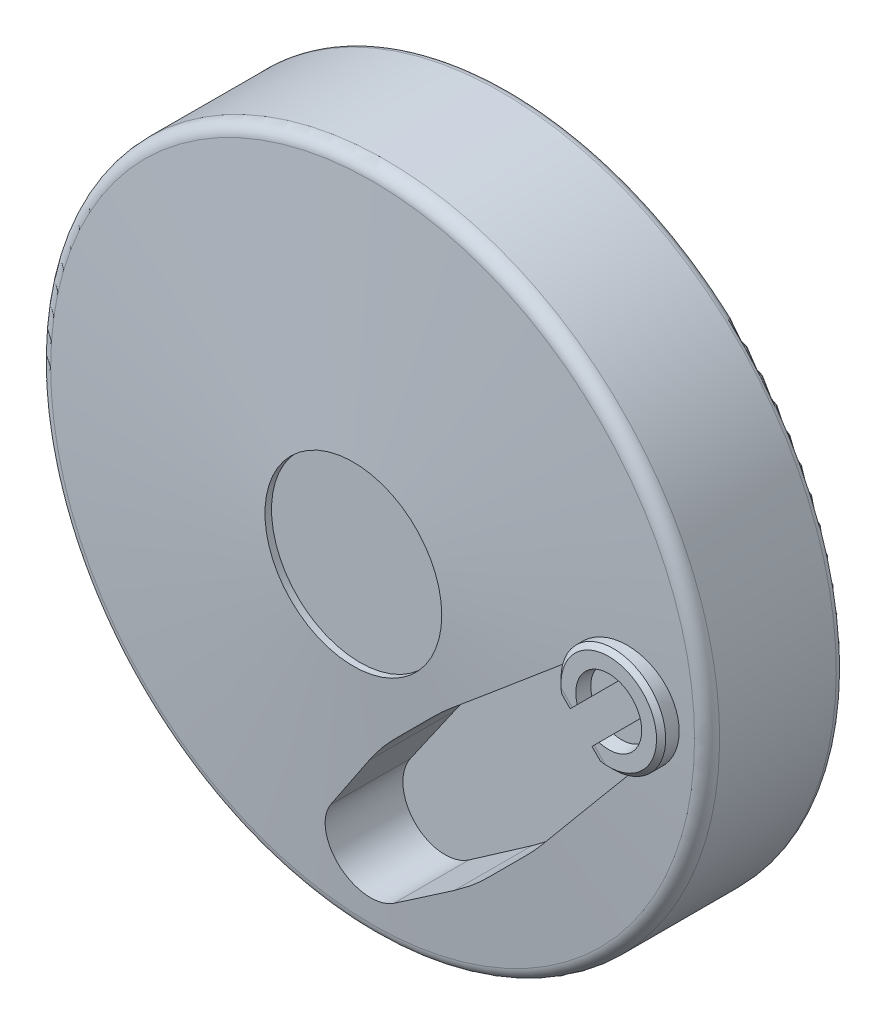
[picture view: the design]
ISO-10303-21;
HEADER;
FILE_DESCRIPTION(('STEP AP214'),'2;1');
FILE_NAME('part.step','',(''),(''),'','','');
FILE_SCHEMA(('AUTOMOTIVE_DESIGN { 1 0 10303 214 1 1 1 1 }'));
ENDSEC;
DATA;
#1=APPLICATION_CONTEXT('core data for automotive mechanical design processes');
#2=APPLICATION_PROTOCOL_DEFINITION('international standard','automotive_design',2000,#1);
#3=PRODUCT_CONTEXT('',#1,'mechanical');
#4=PRODUCT('Part','Part','',(#3));
#5=PRODUCT_RELATED_PRODUCT_CATEGORY('part','',(#4));
#6=PRODUCT_DEFINITION_FORMATION('','',#4);
#7=PRODUCT_DEFINITION_CONTEXT('part definition',#1,'design');
#8=PRODUCT_DEFINITION('design','',#6,#7);
#9=PRODUCT_DEFINITION_SHAPE('','',#8);
#10=(LENGTH_UNIT() NAMED_UNIT(*) SI_UNIT(.MILLI.,.METRE.));
#11=(NAMED_UNIT(*) PLANE_ANGLE_UNIT() SI_UNIT($,.RADIAN.));
#12=(NAMED_UNIT(*) SI_UNIT($,.STERADIAN.) SOLID_ANGLE_UNIT());
#13=UNCERTAINTY_MEASURE_WITH_UNIT(LENGTH_MEASURE(1.E-05),#10,'distance_accuracy_value','');
#14=(GEOMETRIC_REPRESENTATION_CONTEXT(3) GLOBAL_UNCERTAINTY_ASSIGNED_CONTEXT((#13)) GLOBAL_UNIT_ASSIGNED_CONTEXT((#10,
#11,#12)) REPRESENTATION_CONTEXT('',''));
#15=CARTESIAN_POINT('',(0.,0.,0.));
#16=DIRECTION('',(0.,0.,1.));
#17=DIRECTION('',(1.,0.,0.));
#18=AXIS2_PLACEMENT_3D('',#15,#16,#17);
#19=CARTESIAN_POINT('',(39.,0.,20.0000000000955));
#20=DIRECTION('',(0.,0.,-1.));
#21=DIRECTION('',(-0.707106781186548,0.707106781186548,0.));
#22=AXIS2_PLACEMENT_3D('',#19,#20,#21);
#23=CONICAL_SURFACE('',#22,1.9999999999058,0.785398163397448);
#24=CARTESIAN_POINT('',(39.,0.,20.0000000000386));
#25=DIRECTION('',(0.,0.,1.));
#26=DIRECTION('',(-0.707106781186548,0.707106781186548,0.));
#27=AXIS2_PLACEMENT_3D('',#24,#25,#26);
#28=CIRCLE('',#27,1.99999999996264);
#29=CARTESIAN_POINT('',(37.5857864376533,1.41421356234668,20.0000000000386));
#30=VERTEX_POINT('',#29);
#31=EDGE_CURVE('E739',#30,#30,#28,.F.);
#32=ORIENTED_EDGE('',*,*,#31,.T.);
#33=EDGE_LOOP('',(#32));
#34=FACE_BOUND('',#33,.T.);
#35=CARTESIAN_POINT('',(39.,0.,20.3790000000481));
#36=DIRECTION('',(0.,0.,1.));
#37=DIRECTION('',(-0.707106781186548,-0.707106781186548,0.));
#38=AXIS2_PLACEMENT_3D('',#35,#36,#37);
#39=CIRCLE('',#38,1.62099999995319);
#40=CARTESIAN_POINT('',(37.8537799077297,-1.14622009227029,20.3790000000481));
#41=VERTEX_POINT('',#40);
#42=EDGE_CURVE('E689',#41,#41,#39,.T.);
#43=ORIENTED_EDGE('',*,*,#42,.T.);
#44=EDGE_LOOP('',(#43));
#45=FACE_BOUND('',#44,.T.);
#46=ADVANCED_FACE('F16',(#34,#45),#23,.F.);
#47=CARTESIAN_POINT('',(39.,0.,22.));
#48=DIRECTION('',(0.,0.,-1.));
#49=DIRECTION('',(-0.707106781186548,0.707106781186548,0.));
#50=AXIS2_PLACEMENT_3D('',#47,#48,#49);
#51=CYLINDRICAL_SURFACE('',#50,1.621);
#52=CARTESIAN_POINT('',(39.,0.,23.6209999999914));
#53=DIRECTION('',(0.,0.,-1.));
#54=DIRECTION('',(-0.707106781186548,-0.707106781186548,0.));
#55=AXIS2_PLACEMENT_3D('',#52,#53,#54);
#56=CIRCLE('',#55,1.62100000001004);
#57=CARTESIAN_POINT('',(37.8537799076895,-1.14622009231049,23.6209999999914));
#58=VERTEX_POINT('',#57);
#59=EDGE_CURVE('E692',#58,#58,#56,.T.);
#60=ORIENTED_EDGE('',*,*,#59,.F.);
#61=EDGE_LOOP('',(#60));
#62=FACE_BOUND('',#61,.T.);
#63=ORIENTED_EDGE('',*,*,#42,.F.);
#64=EDGE_LOOP('',(#63));
#65=FACE_BOUND('',#64,.T.);
#66=ADVANCED_FACE('F414',(#62,#65),#51,.F.);
#67=CARTESIAN_POINT('',(39.,0.,20.7));
#68=DIRECTION('',(0.,0.,1.));
#69=DIRECTION('',(0.707106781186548,-0.707106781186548,0.));
#70=AXIS2_PLACEMENT_3D('',#67,#68,#69);
#71=CONICAL_SURFACE('',#70,8.,0.78539816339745);
#72=CARTESIAN_POINT('',(46.296517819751,0.225450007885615,20.));
#73=CARTESIAN_POINT('',(46.3518118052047,0.280743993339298,20.0569771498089));
#74=CARTESIAN_POINT('',(46.4069082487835,0.335840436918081,20.1143364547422));
#75=CARTESIAN_POINT('',(46.5167301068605,0.445662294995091,20.2297502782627));
#76=CARTESIAN_POINT('',(46.5714555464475,0.500387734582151,20.2878047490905));
#77=CARTESIAN_POINT('',(46.680566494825,0.609498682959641,20.4045470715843));
#78=CARTESIAN_POINT('',(46.734952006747,0.663884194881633,20.4632349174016));
#79=CARTESIAN_POINT('',(46.8434116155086,0.77234380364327,20.5811942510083));
#80=CARTESIAN_POINT('',(46.8974856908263,0.826417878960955,20.6404657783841));
#81=CARTESIAN_POINT('',(46.9514143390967,0.880346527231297,20.7));
#82=B_SPLINE_CURVE_WITH_KNOTS('',3,(#72,#73,#74,#75,#76,#77,#78,#79,#80,#81),.UNSPECIFIED.,.F.,
.F.,(4,2,2,2,4),(0.,0.290258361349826,0.580496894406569,0.870732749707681,1.16098842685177),.UNSPECIFIED.);
#83=CARTESIAN_POINT('',(46.296517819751,0.225450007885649,20.));
#84=VERTEX_POINT('',#83);
#85=CARTESIAN_POINT('',(46.9514143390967,0.880346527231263,20.7));
#86=VERTEX_POINT('',#85);
#87=EDGE_CURVE('E797',#84,#86,#82,.T.);
#88=ORIENTED_EDGE('',*,*,#87,.F.);
#89=CARTESIAN_POINT('',(39.,0.,20.));
#90=DIRECTION('',(0.,0.,-1.));
#91=DIRECTION('',(0.707106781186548,-0.707106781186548,0.));
#92=AXIS2_PLACEMENT_3D('',#89,#90,#91);
#93=CIRCLE('',#92,7.3);
#94=CARTESIAN_POINT('',(39.2254500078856,7.29651781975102,20.));
#95=VERTEX_POINT('',#94);
#96=EDGE_CURVE('E869',#95,#84,#93,.T.);
#97=ORIENTED_EDGE('',*,*,#96,.F.);
#98=CARTESIAN_POINT('',(39.8803465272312,7.95141433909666,20.7));
#99=CARTESIAN_POINT('',(39.8264178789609,7.89748569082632,20.6404657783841));
#100=CARTESIAN_POINT('',(39.7723438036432,7.84341161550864,20.5811942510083));
#101=CARTESIAN_POINT('',(39.6638841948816,7.73495200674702,20.4632349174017));
#102=CARTESIAN_POINT('',(39.6094986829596,7.68056649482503,20.4045470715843));
#103=CARTESIAN_POINT('',(39.5003877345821,7.57145554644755,20.2878047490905));
#104=CARTESIAN_POINT('',(39.4456622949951,7.51673010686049,20.2297502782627));
#105=CARTESIAN_POINT('',(39.3358404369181,7.40690824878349,20.1143364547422));
#106=CARTESIAN_POINT('',(39.2807439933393,7.35181180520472,20.056977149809));
#107=CARTESIAN_POINT('',(39.2254500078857,7.29651781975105,20.));
#108=B_SPLINE_CURVE_WITH_KNOTS('',3,(#98,#99,#100,#101,#102,#103,#104,#105,#106,#107),
.UNSPECIFIED.,.F.,.F.,(4,2,2,2,4),(0.,0.290255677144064,0.580491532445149,0.870730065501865,
1.16098842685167),.UNSPECIFIED.);
#109=CARTESIAN_POINT('',(39.8803465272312,7.95141433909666,20.7));
#110=VERTEX_POINT('',#109);
#111=EDGE_CURVE('E598',#110,#95,#108,.T.);
#112=ORIENTED_EDGE('',*,*,#111,.F.);
#113=CARTESIAN_POINT('',(39.,0.,20.7));
#114=DIRECTION('',(0.,0.,1.));
#115=DIRECTION('',(-0.707106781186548,0.707106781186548,0.));
#116=AXIS2_PLACEMENT_3D('',#113,#114,#115);
#117=CIRCLE('',#116,8.);
#118=EDGE_CURVE('E787',#110,#86,#117,.F.);
#119=ORIENTED_EDGE('',*,*,#118,.T.);
#120=EDGE_LOOP('',(#88,#97,#112,#119));
#121=FACE_BOUND('',#120,.T.);
#122=ADVANCED_FACE('F421',(#121),#71,.T.);
#123=CARTESIAN_POINT('',(39.,0.,27.));
#124=DIRECTION('',(0.,0.,-1.));
#125=DIRECTION('',(-0.707106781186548,0.707106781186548,0.));
#126=AXIS2_PLACEMENT_3D('',#123,#124,#125);
#127=CYLINDRICAL_SURFACE('',#126,8.);
#128=CARTESIAN_POINT('',(39.,0.,21.7));
#129=DIRECTION('',(0.,0.,1.));
#130=DIRECTION('',(-0.707106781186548,0.707106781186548,0.));
#131=AXIS2_PLACEMENT_3D('',#128,#129,#130);
#132=CIRCLE('',#131,8.);
#133=CARTESIAN_POINT('',(31.0485856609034,-0.880346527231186,21.7));
#134=VERTEX_POINT('',#133);
#135=CARTESIAN_POINT('',(31.2290449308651,1.90059393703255,21.7));
#136=VERTEX_POINT('',#135);
#137=EDGE_CURVE('E1031',#134,#136,#132,.F.);
#138=ORIENTED_EDGE('',*,*,#137,.F.);
#139=DIRECTION('',(0.,0.,1.));
#140=VECTOR('',#139,1.);
#141=CARTESIAN_POINT('',(31.0485856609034,-0.880346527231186,21.7));
#142=LINE('',#141,#140);
#143=CARTESIAN_POINT('',(31.0485856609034,-0.880346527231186,20.7));
#144=VERTEX_POINT('',#143);
#145=EDGE_CURVE('E686',#144,#134,#142,.T.);
#146=ORIENTED_EDGE('',*,*,#145,.F.);
#147=CARTESIAN_POINT('',(39.,0.,20.7));
#148=DIRECTION('',(0.,0.,1.));
#149=DIRECTION('',(-0.707106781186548,0.707106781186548,0.));
#150=AXIS2_PLACEMENT_3D('',#147,#148,#149);
#151=CIRCLE('',#150,8.);
#152=CARTESIAN_POINT('',(31.3116397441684,-2.21113468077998,20.7));
#153=VERTEX_POINT('',#152);
#154=EDGE_CURVE('E732',#153,#144,#151,.F.);
#155=ORIENTED_EDGE('',*,*,#154,.F.);
#156=DIRECTION('',(0.,0.,1.));
#157=VECTOR('',#156,1.);
#158=CARTESIAN_POINT('',(31.3116397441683,-2.21113468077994,32.5));
#159=LINE('',#158,#157);
#160=CARTESIAN_POINT('',(31.3116397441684,-2.21113468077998,32.5));
#161=VERTEX_POINT('',#160);
#162=EDGE_CURVE('E796',#161,#153,#159,.F.);
#163=ORIENTED_EDGE('',*,*,#162,.F.);
#164=CARTESIAN_POINT('',(31.3116397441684,-2.21113468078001,32.5));
#165=CARTESIAN_POINT('',(31.3116427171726,-2.21114242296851,32.5227173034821));
#166=CARTESIAN_POINT('',(31.3113448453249,-2.21010946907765,32.5454212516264));
#167=CARTESIAN_POINT('',(31.3101749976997,-2.20603682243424,32.5906042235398));
#168=CARTESIAN_POINT('',(31.3093037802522,-2.20299978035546,32.6130835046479));
#169=CARTESIAN_POINT('',(31.3059063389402,-2.1911165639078,32.6792728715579));
#170=CARTESIAN_POINT('',(31.3025944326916,-2.17949295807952,32.7224622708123));
#171=CARTESIAN_POINT('',(31.2931287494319,-2.14581287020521,32.8180990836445));
#172=CARTESIAN_POINT('',(31.2864398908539,-2.12175040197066,32.8697675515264));
#173=CARTESIAN_POINT('',(31.2712617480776,-2.06578125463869,32.9689084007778));
#174=CARTESIAN_POINT('',(31.2627552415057,-2.03379903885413,33.0163340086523));
#175=CARTESIAN_POINT('',(31.2450338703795,-1.96512617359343,33.1055959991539));
#176=CARTESIAN_POINT('',(31.2358401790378,-1.92856287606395,33.1475370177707));
#177=CARTESIAN_POINT('',(31.2172452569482,-1.8521046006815,33.2268366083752));
#178=CARTESIAN_POINT('',(31.2078502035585,-1.81227675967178,33.2642609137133));
#179=CARTESIAN_POINT('',(31.1985194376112,-1.77112987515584,33.3));
#180=B_SPLINE_CURVE_WITH_KNOTS('',3,(#164,#165,#166,#167,#168,#169,#170,#171,#172,#173,#174,
#175,#176,#177,#178,#179),.UNSPECIFIED.,.F.,.F.,(4,2,2,2,2,2,2,4),(0.,0.0681022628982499,
0.13611463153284,0.269988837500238,0.441214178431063,0.614140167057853,0.783029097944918,
0.949049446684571),.UNSPECIFIED.);
#181=CARTESIAN_POINT('',(31.1985194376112,-1.77112987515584,33.3));
#182=VERTEX_POINT('',#181);
#183=EDGE_CURVE('E519',#161,#182,#180,.T.);
#184=ORIENTED_EDGE('',*,*,#183,.T.);
#185=CARTESIAN_POINT('',(39.,0.,33.3));
#186=DIRECTION('',(0.,0.,1.));
#187=DIRECTION('',(-0.707106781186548,0.707106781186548,0.));
#188=AXIS2_PLACEMENT_3D('',#185,#186,#187);
#189=CIRCLE('',#188,8.);
#190=CARTESIAN_POINT('',(37.2288701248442,-7.80148056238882,33.3));
#191=VERTEX_POINT('',#190);
#192=EDGE_CURVE('E809',#191,#182,#189,.T.);
#193=ORIENTED_EDGE('',*,*,#192,.F.);
#194=CARTESIAN_POINT('',(37.2288701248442,-7.80148056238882,33.3));
#195=CARTESIAN_POINT('',(37.2037214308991,-7.79577165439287,33.2781899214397));
#196=CARTESIAN_POINT('',(37.1791163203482,-7.7900570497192,33.2557657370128));
#197=CARTESIAN_POINT('',(37.1311438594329,-7.77868792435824,33.2095314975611));
#198=CARTESIAN_POINT('',(37.1077788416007,-7.77303353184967,33.1857189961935));
#199=CARTESIAN_POINT('',(37.0390422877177,-7.75608687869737,33.1111472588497));
#200=CARTESIAN_POINT('',(36.996006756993,-7.74503578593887,33.0580775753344));
#201=CARTESIAN_POINT('',(36.9282187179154,-7.72713744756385,32.9586689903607));
#202=CARTESIAN_POINT('',(36.9015504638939,-7.71991465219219,32.9137163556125));
#203=CARTESIAN_POINT('',(36.8556321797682,-7.70728538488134,32.8203594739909));
#204=CARTESIAN_POINT('',(36.8363113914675,-7.70186165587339,32.7719937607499));
#205=CARTESIAN_POINT('',(36.8110494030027,-7.69471405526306,32.6864246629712));
#206=CARTESIAN_POINT('',(36.8028688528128,-7.69237742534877,32.6499379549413));
#207=CARTESIAN_POINT('',(36.7917114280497,-7.68917895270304,32.5756695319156));
#208=CARTESIAN_POINT('',(36.7887991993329,-7.68833543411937,32.5378774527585));
#209=CARTESIAN_POINT('',(36.7888653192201,-7.68836025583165,32.5));
#210=B_SPLINE_CURVE_WITH_KNOTS('',3,(#194,#195,#196,#197,#198,#199,#200,#201,#202,#203,#204,
#205,#206,#207,#208,#209),.UNSPECIFIED.,.F.,.F.,(4,2,2,2,2,2,2,4),(0.,0.101292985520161,
0.202770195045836,0.409597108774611,0.56739941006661,0.723641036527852,0.83564649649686,
0.949017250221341),.UNSPECIFIED.);
#211=CARTESIAN_POINT('',(36.7888653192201,-7.68836025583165,32.5));
#212=VERTEX_POINT('',#211);
#213=EDGE_CURVE('E536',#191,#212,#210,.T.);
#214=ORIENTED_EDGE('',*,*,#213,.T.);
#215=DIRECTION('',(0.,0.,-1.));
#216=VECTOR('',#215,1.);
#217=CARTESIAN_POINT('',(36.7888653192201,-7.68836025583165,27.));
#218=LINE('',#217,#216);
#219=CARTESIAN_POINT('',(36.7888653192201,-7.68836025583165,20.7));
#220=VERTEX_POINT('',#219);
#221=EDGE_CURVE('E806',#220,#212,#218,.F.);
#222=ORIENTED_EDGE('',*,*,#221,.F.);
#223=CARTESIAN_POINT('',(39.,0.,20.7));
#224=DIRECTION('',(0.,0.,-1.));
#225=DIRECTION('',(-0.707106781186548,-0.707106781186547,0.));
#226=AXIS2_PLACEMENT_3D('',#223,#224,#225);
#227=CIRCLE('',#226,8.);
#228=CARTESIAN_POINT('',(38.1196534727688,-7.95141433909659,20.7));
#229=VERTEX_POINT('',#228);
#230=EDGE_CURVE('E743',#220,#229,#227,.F.);
#231=ORIENTED_EDGE('',*,*,#230,.T.);
#232=DIRECTION('',(0.,0.,1.));
#233=VECTOR('',#232,1.);
#234=CARTESIAN_POINT('',(38.1196534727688,-7.95141433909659,20.));
#235=LINE('',#234,#233);
#236=CARTESIAN_POINT('',(38.1196534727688,-7.95141433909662,21.7));
#237=VERTEX_POINT('',#236);
#238=EDGE_CURVE('E725',#237,#229,#235,.F.);
#239=ORIENTED_EDGE('',*,*,#238,.F.);
#240=CARTESIAN_POINT('',(39.,0.,21.7));
#241=DIRECTION('',(0.,0.,1.));
#242=DIRECTION('',(-0.707106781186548,0.707106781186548,0.));
#243=AXIS2_PLACEMENT_3D('',#240,#241,#242);
#244=CIRCLE('',#243,8.);
#245=CARTESIAN_POINT('',(40.9005939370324,-7.77095506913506,21.7));
#246=VERTEX_POINT('',#245);
#247=EDGE_CURVE('E792',#246,#237,#244,.F.);
#248=ORIENTED_EDGE('',*,*,#247,.F.);
#249=DIRECTION('',(0.,0.,-1.));
#250=VECTOR('',#249,1.);
#251=CARTESIAN_POINT('',(40.9005939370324,-7.77095506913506,27.));
#252=LINE('',#251,#250);
#253=CARTESIAN_POINT('',(40.9005939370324,-7.77095506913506,31.6812185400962));
#254=VERTEX_POINT('',#253);
#255=EDGE_CURVE('E485',#254,#246,#252,.T.);
#256=ORIENTED_EDGE('',*,*,#255,.F.);
#257=CARTESIAN_POINT('',(31.7898495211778,-3.46608281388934,32.4769445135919));
#258=CARTESIAN_POINT('',(31.6928486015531,-3.26435756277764,32.4866964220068));
#259=CARTESIAN_POINT('',(31.6043429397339,-3.05851151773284,32.4956463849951));
#260=CARTESIAN_POINT('',(31.4448682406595,-2.64007722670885,32.5118412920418));
#261=CARTESIAN_POINT('',(31.3738986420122,-2.42748919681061,32.5190862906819));
#262=CARTESIAN_POINT('',(31.2500780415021,-1.99720366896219,32.5317664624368));
#263=CARTESIAN_POINT('',(31.1972147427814,-1.77950974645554,32.5372028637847));
#264=CARTESIAN_POINT('',(31.109919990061,-1.34042289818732,32.5461989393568));
#265=CARTESIAN_POINT('',(31.0754882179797,-1.11903003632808,32.549758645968));
#266=CARTESIAN_POINT('',(31.0252958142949,-0.673993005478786,32.5549527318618));
#267=CARTESIAN_POINT('',(31.0095453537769,-0.450347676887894,32.5565860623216));
#268=CARTESIAN_POINT('',(30.9968648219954,-0.00251492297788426,32.5579007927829));
#269=CARTESIAN_POINT('',(30.9999350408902,0.221672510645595,32.5575821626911));
#270=CARTESIAN_POINT('',(31.0248711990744,0.668936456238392,32.5549977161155));
#271=CARTESIAN_POINT('',(31.0467328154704,0.892013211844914,32.5527323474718));
#272=CARTESIAN_POINT('',(31.1090851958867,1.33551840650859,32.5462870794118));
#273=CARTESIAN_POINT('',(31.1495758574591,1.55594686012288,32.5421071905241));
#274=CARTESIAN_POINT('',(31.2488312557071,1.9923343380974,32.5318971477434));
#275=CARTESIAN_POINT('',(31.3075745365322,2.20829829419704,32.5258691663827));
#276=CARTESIAN_POINT('',(31.4429458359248,2.634569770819,32.5120408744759));
#277=CARTESIAN_POINT('',(31.5195800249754,2.84487531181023,32.5042399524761));
#278=CARTESIAN_POINT('',(31.690165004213,3.25826796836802,32.4869700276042));
#279=CARTESIAN_POINT('',(31.7841156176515,3.46135515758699,32.4775010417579));
#280=CARTESIAN_POINT('',(31.988657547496,3.85889187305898,32.4570152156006));
#281=CARTESIAN_POINT('',(32.0992491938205,4.05334122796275,32.445998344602));
#282=CARTESIAN_POINT('',(32.3365809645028,4.43272363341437,32.4225211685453));
#283=CARTESIAN_POINT('',(32.4633616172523,4.61763110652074,32.4100572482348));
#284=CARTESIAN_POINT('',(32.7319427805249,4.9761048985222,32.3838539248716));
#285=CARTESIAN_POINT('',(32.8737436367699,5.14967095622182,32.3701144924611));
#286=CARTESIAN_POINT('',(33.1713144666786,5.48420718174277,32.341516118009));
#287=CARTESIAN_POINT('',(33.3270810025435,5.64518043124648,32.3266574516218));
#288=CARTESIAN_POINT('',(33.6515638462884,5.95351478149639,32.2959680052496));
#289=CARTESIAN_POINT('',(33.8202846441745,6.10087112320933,32.2801368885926));
#290=CARTESIAN_POINT('',(34.1701796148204,6.38148422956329,32.2475947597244));
#291=CARTESIAN_POINT('',(34.3514037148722,6.51467834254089,32.230880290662));
#292=CARTESIAN_POINT('',(34.7244430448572,6.76536265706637,32.1967847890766));
#293=CARTESIAN_POINT('',(34.9162621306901,6.88284708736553,32.1794035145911));
#294=CARTESIAN_POINT('',(35.3090563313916,7.10122696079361,32.1441358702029));
#295=CARTESIAN_POINT('',(35.5100306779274,7.20212379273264,32.1262495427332));
#296=CARTESIAN_POINT('',(35.9197341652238,7.38663934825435,32.0901197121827));
#297=CARTESIAN_POINT('',(36.1284635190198,7.47025759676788,32.0718761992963));
#298=CARTESIAN_POINT('',(36.557680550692,7.6215603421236,32.034701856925));
#299=CARTESIAN_POINT('',(36.7783326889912,7.68877738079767,32.0157654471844));
#300=CARTESIAN_POINT('',(37.2246179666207,7.80391756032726,31.977816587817));
#301=CARTESIAN_POINT('',(37.4502513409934,7.85183978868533,31.958804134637));
#302=CARTESIAN_POINT('',(37.9047723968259,7.92802398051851,31.9208488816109));
#303=CARTESIAN_POINT('',(38.1336594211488,7.95628985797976,31.9019060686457));
#304=CARTESIAN_POINT('',(38.5931160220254,7.99297028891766,31.8642129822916));
#305=CARTESIAN_POINT('',(38.8236861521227,8.00137798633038,31.8454627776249));
#306=CARTESIAN_POINT('',(39.2794787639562,7.99829026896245,31.8087096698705));
#307=CARTESIAN_POINT('',(39.5047038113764,7.98724238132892,31.7906994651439));
#308=CARTESIAN_POINT('',(39.9534539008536,7.94617458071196,31.7550990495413));
#309=CARTESIAN_POINT('',(40.1769789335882,7.91615456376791,31.7375088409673));
#310=CARTESIAN_POINT('',(40.6207167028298,7.83734978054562,31.7028530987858));
#311=CARTESIAN_POINT('',(40.8409297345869,7.78856669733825,31.6857875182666));
#312=CARTESIAN_POINT('',(41.2765020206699,7.67257025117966,31.6522747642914));
#313=CARTESIAN_POINT('',(41.4918611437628,7.60535639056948,31.6358276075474));
#314=CARTESIAN_POINT('',(41.9161678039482,7.45297097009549,31.6036423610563));
#315=CARTESIAN_POINT('',(42.1251157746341,7.36780062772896,31.5879042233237));
#316=CARTESIAN_POINT('',(42.5351931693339,7.1800612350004,31.5572128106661));
#317=CARTESIAN_POINT('',(42.7363198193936,7.07748607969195,31.542259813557));
#318=CARTESIAN_POINT('',(43.1291568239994,6.85572163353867,31.5132263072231));
#319=CARTESIAN_POINT('',(43.3208708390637,6.73653887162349,31.499145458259));
#320=CARTESIAN_POINT('',(43.6936741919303,6.48231046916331,31.4719132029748));
#321=CARTESIAN_POINT('',(43.8747586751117,6.34725766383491,31.4587622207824));
#322=CARTESIAN_POINT('',(44.224597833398,6.06253678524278,31.4334821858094));
#323=CARTESIAN_POINT('',(44.3933734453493,5.91289459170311,31.4213513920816));
#324=CARTESIAN_POINT('',(44.7176529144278,5.59992840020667,31.3981484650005));
#325=CARTESIAN_POINT('',(44.8731627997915,5.43661068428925,31.3870758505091));
#326=CARTESIAN_POINT('',(45.1699342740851,5.09732556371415,31.3660298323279));
#327=CARTESIAN_POINT('',(45.3111902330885,4.92135320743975,31.3560568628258));
#328=CARTESIAN_POINT('',(45.5783155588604,4.55813203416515,31.337263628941));
#329=CARTESIAN_POINT('',(45.7041903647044,4.37088723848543,31.3284429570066));
#330=CARTESIAN_POINT('',(45.9394195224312,3.98685824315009,31.3120091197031));
#331=CARTESIAN_POINT('',(46.048812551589,3.79009785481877,31.3043931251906));
#332=CARTESIAN_POINT('',(46.2506449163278,3.38802976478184,31.2903768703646));
#333=CARTESIAN_POINT('',(46.3430846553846,3.18272226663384,31.2839765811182));
#334=CARTESIAN_POINT('',(46.5103463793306,2.76501566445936,31.2724192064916));
#335=CARTESIAN_POINT('',(46.585168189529,2.55261649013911,31.2672621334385));
#336=CARTESIAN_POINT('',(46.7166504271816,2.12224682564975,31.2582135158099));
#337=CARTESIAN_POINT('',(46.7733111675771,1.90427643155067,31.2543219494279));
#338=CARTESIAN_POINT('',(46.8679769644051,1.46471536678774,31.2478267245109));
#339=CARTESIAN_POINT('',(46.9060155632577,1.24313195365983,31.2452207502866));
#340=CARTESIAN_POINT('',(46.9633053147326,0.797616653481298,31.2412979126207));
#341=CARTESIAN_POINT('',(46.9825630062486,0.573685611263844,31.2399806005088));
#342=CARTESIAN_POINT('',(47.0021766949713,0.124953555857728,31.2386389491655));
#343=CARTESIAN_POINT('',(47.0025293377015,-0.0998476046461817,31.2386148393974));
#344=CARTESIAN_POINT('',(46.9843221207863,-0.5486741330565,31.2398602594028));
#345=CARTESIAN_POINT('',(46.9657626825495,-0.77269951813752,31.2411297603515));
#346=CARTESIAN_POINT('',(46.9098901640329,-1.21819142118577,31.244955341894));
#347=CARTESIAN_POINT('',(46.8725932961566,-1.43965998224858,31.2475103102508));
#348=CARTESIAN_POINT('',(46.7795236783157,-1.87865799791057,31.2538954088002));
#349=CARTESIAN_POINT('',(46.7237512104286,-2.09618751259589,31.2577255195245));
#350=CARTESIAN_POINT('',(46.5941198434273,-2.52580625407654,31.266645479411));
#351=CARTESIAN_POINT('',(46.5202576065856,-2.7378944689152,31.2717355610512));
#352=CARTESIAN_POINT('',(46.3550120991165,-3.1550123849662,31.2831513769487));
#353=CARTESIAN_POINT('',(46.2636348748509,-3.36004449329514,31.2894766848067));
#354=CARTESIAN_POINT('',(46.0639359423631,-3.76180319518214,31.3033412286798));
#355=CARTESIAN_POINT('',(45.9556035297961,-3.95852444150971,31.310881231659));
#356=CARTESIAN_POINT('',(45.7228167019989,-4.34212733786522,31.327139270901));
#357=CARTESIAN_POINT('',(45.5983626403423,-4.5290092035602,31.3358572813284));
#358=CARTESIAN_POINT('',(45.3342225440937,-4.89161924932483,31.3544330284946));
#359=CARTESIAN_POINT('',(45.1945364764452,-5.06734740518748,31.3642907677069));
#360=CARTESIAN_POINT('',(44.9009341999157,-5.40640975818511,31.3851016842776));
#361=CARTESIAN_POINT('',(44.7470181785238,-5.56974411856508,31.3960548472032));
#362=CARTESIAN_POINT('',(44.4257618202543,-5.88315888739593,31.4190277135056));
#363=CARTESIAN_POINT('',(44.2583976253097,-6.03321470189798,31.4310493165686));
#364=CARTESIAN_POINT('',(43.9117451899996,-6.31863516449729,31.4560817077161));
#365=CARTESIAN_POINT('',(43.7324610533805,-6.45400482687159,31.469092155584));
#366=CARTESIAN_POINT('',(43.3631491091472,-6.70919675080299,31.4960473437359));
#367=CARTESIAN_POINT('',(43.1731186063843,-6.82901508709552,31.5099923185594));
#368=CARTESIAN_POINT('',(42.7837117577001,-7.05222587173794,31.5387452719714));
#369=CARTESIAN_POINT('',(42.5843356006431,-7.15561865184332,31.5535532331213));
#370=CARTESIAN_POINT('',(42.1771387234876,-7.34550079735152,31.5839963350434));
#371=CARTESIAN_POINT('',(41.9692980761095,-7.43194711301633,31.5996334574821));
#372=CARTESIAN_POINT('',(41.5471254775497,-7.58700994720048,31.6316192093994));
#373=CARTESIAN_POINT('',(41.3327936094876,-7.6556266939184,31.6479678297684));
#374=CARTESIAN_POINT('',(40.8991488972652,-7.77456003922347,31.6812896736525));
#375=CARTESIAN_POINT('',(40.6798358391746,-7.82487585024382,31.6982629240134));
#376=CARTESIAN_POINT('',(40.237868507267,-7.90684374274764,31.732732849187));
#377=CARTESIAN_POINT('',(40.0152154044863,-7.93850221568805,31.7502293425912));
#378=CARTESIAN_POINT('',(39.5674690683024,-7.98302755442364,31.785697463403));
#379=CARTESIAN_POINT('',(39.3423708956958,-7.99584384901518,31.8036702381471));
#380=CARTESIAN_POINT('',(38.8919205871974,-8.00244066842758,31.8399365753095));
#381=CARTESIAN_POINT('',(38.6665684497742,-7.99622107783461,31.858230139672));
#382=CARTESIAN_POINT('',(38.2171627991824,-7.96479217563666,31.8950253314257));
#383=CARTESIAN_POINT('',(37.9931095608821,-7.93957898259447,31.9135270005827));
#384=CARTESIAN_POINT('',(37.5479391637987,-7.87034064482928,31.950610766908));
#385=CARTESIAN_POINT('',(37.3268219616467,-7.82631577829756,31.969192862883));
#386=CARTESIAN_POINT('',(36.8888192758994,-7.71970071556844,32.006329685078));
#387=CARTESIAN_POINT('',(36.6719392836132,-7.65708793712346,32.0248843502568));
#388=CARTESIAN_POINT('',(36.244226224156,-7.51375999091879,32.0618055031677));
#389=CARTESIAN_POINT('',(36.0333932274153,-7.43304461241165,32.0801719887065));
#390=CARTESIAN_POINT('',(35.6191337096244,-7.25401042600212,32.1165849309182));
#391=CARTESIAN_POINT('',(35.4157124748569,-7.15567933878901,32.1346311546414));
#392=CARTESIAN_POINT('',(35.0178590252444,-6.94216304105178,32.1702394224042));
#393=CARTESIAN_POINT('',(34.823427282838,-6.8269769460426,32.187801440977));
#394=CARTESIAN_POINT('',(34.6342146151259,-6.70372418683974,32.2050449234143));
#395=B_SPLINE_CURVE_WITH_KNOTS('',3,(#257,#258,#259,#260,#261,#262,#263,#264,#265,#266,#267,
#268,#269,#270,#271,#272,#273,#274,#275,#276,#277,#278,#279,#280,#281,#282,#283,#284,#285,#286,
#287,#288,#289,#290,#291,#292,#293,#294,#295,#296,#297,#298,#299,#300,#301,#302,#303,#304,#305,
#306,#307,#308,#309,#310,#311,#312,#313,#314,#315,#316,#317,#318,#319,#320,#321,#322,#323,#324,
#325,#326,#327,#328,#329,#330,#331,#332,#333,#334,#335,#336,#337,#338,#339,#340,#341,#342,#343,
#344,#345,#346,#347,#348,#349,#350,#351,#352,#353,#354,#355,#356,#357,#358,#359,#360,#361,#362,
#363,#364,#365,#366,#367,#368,#369,#370,#371,#372,#373,#374,#375,#376,#377,#378,#379,#380,#381,
#382,#383,#384,#385,#386,#387,#388,#389,#390,#391,#392,#393,#394),.UNSPECIFIED.,.F.,.F.,(4,2,2,
2,2,2,2,2,2,2,2,2,2,2,2,2,2,2,2,2,2,2,2,2,2,2,2,2,2,2,2,2,2,2,2,2,2,2,2,2,2,2,2,2,2,2,2,2,2,2,2,
2,2,2,2,2,2,2,2,2,2,2,2,2,2,2,2,2,4),(0.,0.671941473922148,1.34386143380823,2.01532415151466,
2.68677528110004,3.3585918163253,4.03041870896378,4.70209109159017,5.37375978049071,
6.04464189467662,6.71575573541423,7.38686272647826,8.05798302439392,8.7308176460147,
9.40366775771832,10.0763526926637,10.7492718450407,11.4250538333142,12.1010834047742,
12.7770563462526,13.4530478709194,14.1465036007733,14.8399921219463,15.5333425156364,
16.2269322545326,16.9047754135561,17.5826222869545,18.2604083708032,18.9382127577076,
19.6159712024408,20.2939678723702,20.9716987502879,21.6497367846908,22.3265932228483,
23.0031404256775,23.6799538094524,24.3565271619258,25.0314872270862,25.7064312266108,
26.3813819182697,27.0563209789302,27.7300398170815,28.4035240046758,29.0771276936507,
29.7507163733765,30.4237232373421,31.0967198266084,31.7698406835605,32.4427295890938,
33.116045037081,33.7893457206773,34.4626478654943,35.1359411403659,35.8104564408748,
36.4847407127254,37.1591948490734,37.8336353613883,38.5097675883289,39.1858911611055,
39.8620438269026,40.5379647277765,41.2156964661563,41.8934323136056,42.5713066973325,
43.2491710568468,43.9278623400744,44.6065615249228,45.2857356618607,45.9649454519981),.UNSPECIFIED.);
#396=CARTESIAN_POINT('',(31.2290449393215,1.90059397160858,32.5339343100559));
#397=VERTEX_POINT('',#396);
#398=EDGE_CURVE('E488',#254,#397,#395,.F.);
#399=ORIENTED_EDGE('',*,*,#398,.T.);
#400=DIRECTION('',(0.,0.,-1.));
#401=VECTOR('',#400,1.);
#402=CARTESIAN_POINT('',(31.2290449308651,1.90059393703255,27.));
#403=LINE('',#402,#401);
#404=EDGE_CURVE('E483',#136,#397,#403,.F.);
#405=ORIENTED_EDGE('',*,*,#404,.F.);
#406=EDGE_LOOP('',(#138,#146,#155,#163,#184,#193,#214,#222,#231,#239,#248,#256,#399,#405));
#407=FACE_BOUND('',#406,.T.);
#408=ADVANCED_FACE('F499',(#407),#127,.T.);
#409=CARTESIAN_POINT('',(20.6152236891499,-4.24264068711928,21.7));
#410=DIRECTION('',(0.,0.,1.));
#411=DIRECTION('',(0.707106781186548,-0.707106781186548,0.));
#412=AXIS2_PLACEMENT_3D('',#409,#410,#411);
#413=PLANE('',#412);
#414=DIRECTION('',(-0.707106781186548,-0.707106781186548,0.));
#415=VECTOR('',#414,1.);
#416=CARTESIAN_POINT('',(24.1507575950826,-7.77817459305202,21.7));
#417=LINE('',#416,#415);
#418=CARTESIAN_POINT('',(39.8803465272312,7.95141433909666,21.7));
#419=VERTEX_POINT('',#418);
#420=EDGE_CURVE('E596',#419,#134,#417,.T.);
#421=ORIENTED_EDGE('',*,*,#420,.T.);
#422=ORIENTED_EDGE('',*,*,#137,.T.);
#423=EDGE_CURVE('E141',#136,#419,#132,.F.);
#424=ORIENTED_EDGE('',*,*,#423,.T.);
#425=EDGE_LOOP('',(#421,#422,#424));
#426=FACE_BOUND('',#425,.T.);
#427=ADVANCED_FACE('F503',(#426),#413,.F.);
#428=CARTESIAN_POINT('',(31.2218254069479,-14.8492424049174,21.7));
#429=DIRECTION('',(0.,0.,1.));
#430=DIRECTION('',(0.707106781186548,-0.707106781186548,0.));
#431=AXIS2_PLACEMENT_3D('',#428,#429,#430);
#432=PLANE('',#431);
#433=DIRECTION('',(-0.707106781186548,-0.707106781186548,0.));
#434=VECTOR('',#433,1.);
#435=CARTESIAN_POINT('',(31.2218254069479,-14.8492424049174,21.7));
#436=LINE('',#435,#434);
#437=CARTESIAN_POINT('',(46.9514143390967,0.880346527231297,21.7));
#438=VERTEX_POINT('',#437);
#439=EDGE_CURVE('E793',#237,#438,#436,.F.);
#440=ORIENTED_EDGE('',*,*,#439,.T.);
#441=EDGE_CURVE('E810',#438,#246,#244,.F.);
#442=ORIENTED_EDGE('',*,*,#441,.T.);
#443=ORIENTED_EDGE('',*,*,#247,.T.);
#444=EDGE_LOOP('',(#440,#442,#443));
#445=FACE_BOUND('',#444,.T.);
#446=ADVANCED_FACE('F859',(#445),#432,.F.);
#447=CARTESIAN_POINT('',(31.2218254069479,-14.8492424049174,20.));
#448=DIRECTION('',(-0.707106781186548,0.707106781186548,0.));
#449=DIRECTION('',(0.707106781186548,0.707106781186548,0.));
#450=AXIS2_PLACEMENT_3D('',#447,#448,#449);
#451=PLANE('',#450);
#452=ORIENTED_EDGE('',*,*,#87,.T.);
#453=DIRECTION('',(0.,0.,1.));
#454=VECTOR('',#453,1.);
#455=CARTESIAN_POINT('',(46.9514143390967,0.880346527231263,20.));
#456=LINE('',#455,#454);
#457=EDGE_CURVE('E728',#86,#438,#456,.T.);
#458=ORIENTED_EDGE('',*,*,#457,.T.);
#459=ORIENTED_EDGE('',*,*,#439,.F.);
#460=ORIENTED_EDGE('',*,*,#238,.T.);
#461=CARTESIAN_POINT('',(38.1196534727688,-7.95141433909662,20.7));
#462=CARTESIAN_POINT('',(38.1735821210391,-7.89748569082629,20.6404657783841));
#463=CARTESIAN_POINT('',(38.2276561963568,-7.84341161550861,20.5811942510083));
#464=CARTESIAN_POINT('',(38.3361158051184,-7.73495200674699,20.4632349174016));
#465=CARTESIAN_POINT('',(38.3905013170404,-7.680566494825,20.4045470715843));
#466=CARTESIAN_POINT('',(38.4996122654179,-7.57145554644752,20.2878047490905));
#467=CARTESIAN_POINT('',(38.5543377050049,-7.51673010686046,20.2297502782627));
#468=CARTESIAN_POINT('',(38.6641595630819,-7.40690824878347,20.1143364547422));
#469=CARTESIAN_POINT('',(38.7192560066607,-7.3518118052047,20.0569771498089));
#470=CARTESIAN_POINT('',(38.7745499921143,-7.29651781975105,20.));
#471=B_SPLINE_CURVE_WITH_KNOTS('',3,(#461,#462,#463,#464,#465,#466,#467,#468,#469,#470),
.UNSPECIFIED.,.F.,.F.,(4,2,2,2,4),(0.,0.290255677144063,0.580491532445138,0.870730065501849,
1.16098842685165),.UNSPECIFIED.);
#472=CARTESIAN_POINT('',(38.7745499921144,-7.29651781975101,20.));
#473=VERTEX_POINT('',#472);
#474=EDGE_CURVE('E746',#229,#473,#471,.T.);
#475=ORIENTED_EDGE('',*,*,#474,.T.);
#476=DIRECTION('',(-0.707106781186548,-0.707106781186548,0.));
#477=VECTOR('',#476,1.);
#478=CARTESIAN_POINT('',(39.9545941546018,-6.11647365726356,20.));
#479=LINE('',#478,#477);
#480=EDGE_CURVE('E735',#473,#84,#479,.F.);
#481=ORIENTED_EDGE('',*,*,#480,.T.);
#482=EDGE_LOOP('',(#452,#458,#459,#460,#475,#481));
#483=FACE_BOUND('',#482,.T.);
#484=ADVANCED_FACE('F875',(#483),#451,.F.);
#485=CARTESIAN_POINT('',(39.,0.,20.7));
#486=DIRECTION('',(0.,0.,1.));
#487=DIRECTION('',(0.707106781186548,-0.707106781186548,0.));
#488=AXIS2_PLACEMENT_3D('',#485,#486,#487);
#489=CONICAL_SURFACE('',#488,8.,0.78539816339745);
#490=ORIENTED_EDGE('',*,*,#474,.F.);
#491=ORIENTED_EDGE('',*,*,#230,.F.);
#492=CARTESIAN_POINT('',(35.5148343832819,-6.41432931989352,20.));
#493=CARTESIAN_POINT('',(35.6246881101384,-6.52418304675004,20.0440794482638));
#494=CARTESIAN_POINT('',(35.7336630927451,-6.63315802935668,20.0923666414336));
#495=CARTESIAN_POINT('',(35.9496178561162,-6.84911279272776,20.1963057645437));
#496=CARTESIAN_POINT('',(36.0566010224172,-6.95609595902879,20.2519435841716));
#497=CARTESIAN_POINT('',(36.268720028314,-7.16821496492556,20.369690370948));
#498=CARTESIAN_POINT('',(36.3738563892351,-7.27335132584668,20.4317974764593));
#499=CARTESIAN_POINT('',(36.5825698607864,-7.48206479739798,20.5617890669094));
#500=CARTESIAN_POINT('',(36.6861436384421,-7.58563857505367,20.629684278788));
#501=CARTESIAN_POINT('',(36.7888653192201,-7.68836025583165,20.7));
#502=B_SPLINE_CURVE_WITH_KNOTS('',3,(#492,#493,#494,#495,#496,#497,#498,#499,#500,#501),
.UNSPECIFIED.,.F.,.F.,(4,2,2,2,4),(0.,0.484340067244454,0.967763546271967,1.45104829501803,
1.93524902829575),.UNSPECIFIED.);
#503=CARTESIAN_POINT('',(35.5148343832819,-6.41432931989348,20.));
#504=VERTEX_POINT('',#503);
#505=EDGE_CURVE('E573',#504,#220,#502,.T.);
#506=ORIENTED_EDGE('',*,*,#505,.F.);
#507=CARTESIAN_POINT('',(39.,0.,20.));
#508=DIRECTION('',(0.,0.,-1.));
#509=DIRECTION('',(0.707106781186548,-0.707106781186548,0.));
#510=AXIS2_PLACEMENT_3D('',#507,#508,#509);
#511=CIRCLE('',#510,7.3);
#512=EDGE_CURVE('E891',#473,#504,#511,.T.);
#513=ORIENTED_EDGE('',*,*,#512,.F.);
#514=EDGE_LOOP('',(#490,#491,#506,#513));
#515=FACE_BOUND('',#514,.T.);
#516=ADVANCED_FACE('F879',(#515),#489,.T.);
#517=CARTESIAN_POINT('',(45.3639610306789,-16.2634559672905,32.5));
#518=DIRECTION('',(0.707106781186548,0.707106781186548,0.));
#519=DIRECTION('',(0.707106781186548,-0.707106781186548,0.));
#520=AXIS2_PLACEMENT_3D('',#517,#518,#519);
#521=PLANE('',#520);
#522=DIRECTION('',(0.707106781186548,-0.707106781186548,0.));
#523=VECTOR('',#522,1.);
#524=CARTESIAN_POINT('',(45.3639610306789,-16.2634559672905,24.));
#525=LINE('',#524,#523);
#526=CARTESIAN_POINT('',(35.7119534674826,-6.61144840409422,24.));
#527=VERTEX_POINT('',#526);
#528=CARTESIAN_POINT('',(32.3885515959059,-3.28804653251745,24.));
#529=VERTEX_POINT('',#528);
#530=EDGE_CURVE('E752',#527,#529,#525,.F.);
#531=ORIENTED_EDGE('',*,*,#530,.T.);
#532=DIRECTION('',(0.,0.,1.));
#533=VECTOR('',#532,1.);
#534=CARTESIAN_POINT('',(32.3885515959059,-3.28804653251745,32.5));
#535=LINE('',#534,#533);
#536=CARTESIAN_POINT('',(32.3885515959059,-3.28804653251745,32.5));
#537=VERTEX_POINT('',#536);
#538=EDGE_CURVE('E572',#529,#537,#535,.T.);
#539=ORIENTED_EDGE('',*,*,#538,.T.);
#540=DIRECTION('',(0.707106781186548,-0.707106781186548,0.));
#541=VECTOR('',#540,1.);
#542=CARTESIAN_POINT('',(45.3639610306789,-16.2634559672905,32.5));
#543=LINE('',#542,#541);
#544=EDGE_CURVE('E720',#537,#161,#543,.F.);
#545=ORIENTED_EDGE('',*,*,#544,.T.);
#546=ORIENTED_EDGE('',*,*,#162,.T.);
#547=CARTESIAN_POINT('',(31.3116397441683,-2.21113468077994,20.7));
#548=CARTESIAN_POINT('',(31.4143614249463,-2.31385636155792,20.629684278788));
#549=CARTESIAN_POINT('',(31.517935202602,-2.41743013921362,20.5617890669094));
#550=CARTESIAN_POINT('',(31.7266486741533,-2.62614361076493,20.4317974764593));
#551=CARTESIAN_POINT('',(31.8317850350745,-2.73127997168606,20.369690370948));
#552=CARTESIAN_POINT('',(32.0439040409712,-2.94339897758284,20.2519435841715));
#553=CARTESIAN_POINT('',(32.1508872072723,-3.05038214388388,20.1963057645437));
#554=CARTESIAN_POINT('',(32.3668419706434,-3.26633690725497,20.0923666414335));
#555=CARTESIAN_POINT('',(32.47581695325,-3.37531188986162,20.0440794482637));
#556=CARTESIAN_POINT('',(32.5856706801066,-3.48516561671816,20.));
#557=B_SPLINE_CURVE_WITH_KNOTS('',3,(#547,#548,#549,#550,#551,#552,#553,#554,#555,#556),
.UNSPECIFIED.,.F.,.F.,(4,2,2,2,4),(0.,0.484200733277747,0.967485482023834,1.45090896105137,
1.93524902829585),.UNSPECIFIED.);
#558=CARTESIAN_POINT('',(32.5856706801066,-3.48516561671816,20.));
#559=VERTEX_POINT('',#558);
#560=EDGE_CURVE('E802',#153,#559,#557,.T.);
#561=ORIENTED_EDGE('',*,*,#560,.T.);
#562=DIRECTION('',(0.707106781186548,-0.707106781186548,0.));
#563=VECTOR('',#562,1.);
#564=CARTESIAN_POINT('',(45.3639610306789,-16.2634559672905,20.));
#565=LINE('',#564,#563);
#566=EDGE_CURVE('E803',#559,#504,#565,.T.);
#567=ORIENTED_EDGE('',*,*,#566,.T.);
#568=ORIENTED_EDGE('',*,*,#505,.T.);
#569=ORIENTED_EDGE('',*,*,#221,.T.);
#570=DIRECTION('',(0.707106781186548,-0.707106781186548,0.));
#571=VECTOR('',#570,1.);
#572=CARTESIAN_POINT('',(45.3639610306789,-16.2634559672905,32.5));
#573=LINE('',#572,#571);
#574=CARTESIAN_POINT('',(35.7119534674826,-6.61144840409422,32.5));
#575=VERTEX_POINT('',#574);
#576=EDGE_CURVE('E753',#212,#575,#573,.F.);
#577=ORIENTED_EDGE('',*,*,#576,.T.);
#578=DIRECTION('',(0.,0.,1.));
#579=VECTOR('',#578,1.);
#580=CARTESIAN_POINT('',(35.7119534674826,-6.61144840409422,32.5));
#581=LINE('',#580,#579);
#582=EDGE_CURVE('E749',#575,#527,#581,.F.);
#583=ORIENTED_EDGE('',*,*,#582,.T.);
#584=EDGE_LOOP('',(#531,#539,#545,#546,#561,#567,#568,#569,#577,#583));
#585=FACE_BOUND('',#584,.T.);
#586=ADVANCED_FACE('F554',(#585),#521,.F.);
#587=CARTESIAN_POINT('',(46.4246212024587,-15.2027957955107,32.5));
#588=DIRECTION('',(0.707106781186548,-0.707106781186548,0.));
#589=DIRECTION('',(-0.707106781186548,-0.707106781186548,0.));
#590=AXIS2_PLACEMENT_3D('',#587,#588,#589);
#591=CYLINDRICAL_SURFACE('',#590,1.5);
#592=ORIENTED_EDGE('',*,*,#213,.F.);
#593=CARTESIAN_POINT('',(37.2288701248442,-7.80148056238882,33.3));
#594=CARTESIAN_POINT('',(37.2238322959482,-7.77054921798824,33.3290432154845));
#595=CARTESIAN_POINT('',(37.2212164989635,-7.73947215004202,33.3587477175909));
#596=CARTESIAN_POINT('',(37.2223140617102,-7.67778852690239,33.419103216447));
#597=CARTESIAN_POINT('',(37.2260929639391,-7.64719012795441,33.449760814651));
#598=CARTESIAN_POINT('',(37.239984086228,-7.59419229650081,33.5045258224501));
#599=CARTESIAN_POINT('',(37.2485838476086,-7.57142987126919,33.5286440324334));
#600=CARTESIAN_POINT('',(37.2711456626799,-7.52798820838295,33.5760434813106));
#601=CARTESIAN_POINT('',(37.2850819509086,-7.50729955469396,33.5993281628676));
#602=CARTESIAN_POINT('',(37.3182324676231,-7.46854551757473,33.6444545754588));
#603=CARTESIAN_POINT('',(37.3374644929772,-7.45048929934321,33.6662911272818));
#604=CARTESIAN_POINT('',(37.3804320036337,-7.41745322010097,33.7078125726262));
#605=CARTESIAN_POINT('',(37.4041767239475,-7.40247980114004,33.7274929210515));
#606=CARTESIAN_POINT('',(37.4627718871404,-7.37154051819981,33.7699362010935));
#607=CARTESIAN_POINT('',(37.4988084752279,-7.35664594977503,33.7918292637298));
#608=CARTESIAN_POINT('',(37.5745087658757,-7.33130494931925,33.8314763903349));
#609=CARTESIAN_POINT('',(37.6141799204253,-7.32086791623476,33.8492216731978));
#610=CARTESIAN_POINT('',(37.724271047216,-7.29737476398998,33.8922398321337));
#611=CARTESIAN_POINT('',(37.796717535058,-7.28762782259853,33.9140458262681));
#612=CARTESIAN_POINT('',(37.9442266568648,-7.27463891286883,33.9495046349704));
#613=CARTESIAN_POINT('',(38.019299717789,-7.27142682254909,33.9631198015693));
#614=CARTESIAN_POINT('',(38.1632307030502,-7.26952589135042,33.9827869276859));
#615=CARTESIAN_POINT('',(38.2320081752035,-7.27043958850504,33.9894303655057));
#616=CARTESIAN_POINT('',(38.3689165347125,-7.27501229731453,33.997986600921));
#617=CARTESIAN_POINT('',(38.4370447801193,-7.27863690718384,33.999957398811));
#618=CARTESIAN_POINT('',(38.5050252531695,-7.28319984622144,34.));
#619=B_SPLINE_CURVE_WITH_KNOTS('',3,(#593,#594,#595,#596,#597,#598,#599,#600,#601,#602,#603,
#604,#605,#606,#607,#608,#609,#610,#611,#612,#613,#614,#615,#616,#617,#618),.UNSPECIFIED.,.F.,
.F.,(4,2,2,2,2,2,2,2,2,2,2,2,4),(0.,0.128540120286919,0.258405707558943,0.360740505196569,
0.462587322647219,0.564780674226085,0.667185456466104,0.800584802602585,0.934264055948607,
1.16183461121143,1.39044332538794,1.59752440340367,1.80202126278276),.UNSPECIFIED.);
#620=CARTESIAN_POINT('',(38.5050252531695,-7.28319984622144,34.));
#621=VERTEX_POINT('',#620);
#622=EDGE_CURVE('E563',#191,#621,#619,.T.);
#623=ORIENTED_EDGE('',*,*,#622,.T.);
#624=DIRECTION('',(0.707106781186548,-0.707106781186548,0.));
#625=VECTOR('',#624,1.);
#626=CARTESIAN_POINT('',(35.110912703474,-3.88908729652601,34.));
#627=LINE('',#626,#625);
#628=CARTESIAN_POINT('',(36.7726136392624,-5.5507882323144,34.));
#629=VERTEX_POINT('',#628);
#630=EDGE_CURVE('E779',#621,#629,#627,.F.);
#631=ORIENTED_EDGE('',*,*,#630,.T.);
#632=CARTESIAN_POINT('',(36.7726136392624,-5.5507882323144,32.5));
#633=DIRECTION('',(-0.707106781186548,0.707106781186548,0.));
#634=DIRECTION('',(-0.707106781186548,-0.707106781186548,0.));
#635=AXIS2_PLACEMENT_3D('',#632,#633,#634);
#636=CIRCLE('',#635,1.5);
#637=EDGE_CURVE('E545',#575,#629,#636,.T.);
#638=ORIENTED_EDGE('',*,*,#637,.F.);
#639=ORIENTED_EDGE('',*,*,#576,.F.);
#640=EDGE_LOOP('',(#592,#623,#631,#638,#639));
#641=FACE_BOUND('',#640,.T.);
#642=ADVANCED_FACE('F548',(#641),#591,.T.);
#643=CARTESIAN_POINT('',(39.,0.,33.3));
#644=DIRECTION('',(0.,0.,-1.));
#645=DIRECTION('',(-0.707106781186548,0.707106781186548,0.));
#646=AXIS2_PLACEMENT_3D('',#643,#644,#645);
#647=CONICAL_SURFACE('',#646,8.,0.785398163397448);
#648=ORIENTED_EDGE('',*,*,#622,.F.);
#649=ORIENTED_EDGE('',*,*,#192,.T.);
#650=CARTESIAN_POINT('',(31.7168001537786,-0.494974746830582,34.));
#651=CARTESIAN_POINT('',(31.7209944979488,-0.557277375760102,33.9999699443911));
#652=CARTESIAN_POINT('',(31.7243843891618,-0.619691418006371,33.998309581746));
#653=CARTESIAN_POINT('',(31.7289649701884,-0.744866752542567,33.9911783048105));
#654=CARTESIAN_POINT('',(31.7301381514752,-0.807626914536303,33.9856775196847));
#655=CARTESIAN_POINT('',(31.7296027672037,-0.934253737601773,33.9700990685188));
#656=CARTESIAN_POINT('',(31.7278184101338,-0.998106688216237,33.9599060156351));
#657=CARTESIAN_POINT('',(31.7200771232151,-1.12429439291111,33.9340295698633));
#658=CARTESIAN_POINT('',(31.714135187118,-1.18663377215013,33.9183660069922));
#659=CARTESIAN_POINT('',(31.6994390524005,-1.28683460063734,33.8869915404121));
#660=CARTESIAN_POINT('',(31.6924218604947,-1.32555793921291,33.8732552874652));
#661=CARTESIAN_POINT('',(31.6752211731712,-1.40089401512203,33.8425446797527));
#662=CARTESIAN_POINT('',(31.6650460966,-1.43751206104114,33.8255789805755));
#663=CARTESIAN_POINT('',(31.6405761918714,-1.50802176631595,33.7877300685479));
#664=CARTESIAN_POINT('',(31.6262234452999,-1.54186587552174,33.7667933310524));
#665=CARTESIAN_POINT('',(31.5928293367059,-1.60427018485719,33.7211395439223));
#666=CARTESIAN_POINT('',(31.5737999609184,-1.63284357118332,33.6964322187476));
#667=CARTESIAN_POINT('',(31.5329902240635,-1.68055694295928,33.6462311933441));
#668=CARTESIAN_POINT('',(31.5116044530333,-1.70030947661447,33.6210023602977));
#669=CARTESIAN_POINT('',(31.4657132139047,-1.73300372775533,33.5689806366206));
#670=CARTESIAN_POINT('',(31.4412038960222,-1.74593693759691,33.5421858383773));
#671=CARTESIAN_POINT('',(31.3878171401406,-1.76608397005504,33.4856308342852));
#672=CARTESIAN_POINT('',(31.3587456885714,-1.7726450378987,33.4558288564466));
#673=CARTESIAN_POINT('',(31.2995117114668,-1.77910842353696,33.3966628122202));
#674=CARTESIAN_POINT('',(31.2693482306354,-1.77900476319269,33.3672991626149));
#675=CARTESIAN_POINT('',(31.2255531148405,-1.77505985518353,33.3254877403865));
#676=CARTESIAN_POINT('',(31.2120325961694,-1.77332380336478,33.3126919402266));
#677=CARTESIAN_POINT('',(31.1985194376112,-1.77112987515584,33.3));
#678=B_SPLINE_CURVE_WITH_KNOTS('',3,(#650,#651,#652,#653,#654,#655,#656,#657,#658,#659,#660,
#661,#662,#663,#664,#665,#666,#667,#668,#669,#670,#671,#672,#673,#674,#675,#676,#677),
.UNSPECIFIED.,.F.,.F.,(4,2,2,2,2,2,2,2,2,2,2,2,2,4),(0.,0.187392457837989,0.376258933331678,
0.570040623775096,0.763127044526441,0.887947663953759,1.01243833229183,1.13874457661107,
1.26473041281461,1.37952362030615,1.49445970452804,1.62021182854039,1.74607675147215,
1.80212241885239),.UNSPECIFIED.);
#679=CARTESIAN_POINT('',(31.7168001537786,-0.494974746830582,34.));
#680=VERTEX_POINT('',#679);
#681=EDGE_CURVE('E589',#680,#182,#678,.T.);
#682=ORIENTED_EDGE('',*,*,#681,.F.);
#683=CARTESIAN_POINT('',(39.,0.,34.));
#684=DIRECTION('',(0.,0.,1.));
#685=DIRECTION('',(-0.707106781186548,0.707106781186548,0.));
#686=AXIS2_PLACEMENT_3D('',#683,#684,#685);
#687=CIRCLE('',#686,7.3);
#688=EDGE_CURVE('E571',#621,#680,#687,.T.);
#689=ORIENTED_EDGE('',*,*,#688,.F.);
#690=EDGE_LOOP('',(#648,#649,#682,#689));
#691=FACE_BOUND('',#690,.T.);
#692=ADVANCED_FACE('F553',(#691),#647,.T.);
#693=CARTESIAN_POINT('',(46.4246212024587,-15.2027957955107,32.5));
#694=DIRECTION('',(0.707106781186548,-0.707106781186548,0.));
#695=DIRECTION('',(-0.707106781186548,-0.707106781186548,0.));
#696=AXIS2_PLACEMENT_3D('',#693,#694,#695);
#697=CYLINDRICAL_SURFACE('',#696,1.5);
#698=ORIENTED_EDGE('',*,*,#681,.T.);
#699=ORIENTED_EDGE('',*,*,#183,.F.);
#700=ORIENTED_EDGE('',*,*,#544,.F.);
#701=CARTESIAN_POINT('',(33.4492117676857,-2.22738636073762,32.5));
#702=DIRECTION('',(-0.707106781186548,0.707106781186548,0.));
#703=DIRECTION('',(-0.707106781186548,-0.707106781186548,0.));
#704=AXIS2_PLACEMENT_3D('',#701,#702,#703);
#705=CIRCLE('',#704,1.5);
#706=CARTESIAN_POINT('',(33.4492117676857,-2.22738636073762,34.));
#707=VERTEX_POINT('',#706);
#708=EDGE_CURVE('E769',#707,#537,#705,.F.);
#709=ORIENTED_EDGE('',*,*,#708,.F.);
#710=DIRECTION('',(0.707106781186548,-0.707106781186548,0.));
#711=VECTOR('',#710,1.);
#712=CARTESIAN_POINT('',(35.110912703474,-3.88908729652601,34.));
#713=LINE('',#712,#711);
#714=EDGE_CURVE('E776',#707,#680,#713,.F.);
#715=ORIENTED_EDGE('',*,*,#714,.T.);
#716=EDGE_LOOP('',(#698,#699,#700,#709,#715));
#717=FACE_BOUND('',#716,.T.);
#718=ADVANCED_FACE('F583',(#717),#697,.T.);
#719=CARTESIAN_POINT('',(39.,0.,20.7));
#720=DIRECTION('',(0.,0.,1.));
#721=DIRECTION('',(0.707106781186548,-0.707106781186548,0.));
#722=AXIS2_PLACEMENT_3D('',#719,#720,#721);
#723=CONICAL_SURFACE('',#722,8.,0.785398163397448);
#724=CARTESIAN_POINT('',(31.703482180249,-0.225450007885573,20.));
#725=CARTESIAN_POINT('',(31.6481881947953,-0.280743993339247,20.0569771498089));
#726=CARTESIAN_POINT('',(31.5930917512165,-0.335840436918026,20.1143364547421));
#727=CARTESIAN_POINT('',(31.4832698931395,-0.44566229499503,20.2297502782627));
#728=CARTESIAN_POINT('',(31.4285444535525,-0.500387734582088,20.2878047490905));
#729=CARTESIAN_POINT('',(31.319433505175,-0.609498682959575,20.4045470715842));
#730=CARTESIAN_POINT('',(31.265047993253,-0.663884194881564,20.4632349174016));
#731=CARTESIAN_POINT('',(31.1565883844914,-0.772343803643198,20.5811942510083));
#732=CARTESIAN_POINT('',(31.1025143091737,-0.826417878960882,20.6404657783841));
#733=CARTESIAN_POINT('',(31.0485856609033,-0.880346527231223,20.7));
#734=B_SPLINE_CURVE_WITH_KNOTS('',3,(#724,#725,#726,#727,#728,#729,#730,#731,#732,#733),
.UNSPECIFIED.,.F.,.F.,(4,2,2,2,4),(0.,0.290258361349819,0.58049689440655,0.870732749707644,
1.16098842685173),.UNSPECIFIED.);
#735=CARTESIAN_POINT('',(31.703482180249,-0.225450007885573,20.));
#736=VERTEX_POINT('',#735);
#737=EDGE_CURVE('E731',#736,#144,#734,.T.);
#738=ORIENTED_EDGE('',*,*,#737,.F.);
#739=CARTESIAN_POINT('',(39.,0.,20.));
#740=DIRECTION('',(0.,0.,-1.));
#741=DIRECTION('',(0.707106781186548,-0.707106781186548,0.));
#742=AXIS2_PLACEMENT_3D('',#739,#740,#741);
#743=CIRCLE('',#742,7.3);
#744=EDGE_CURVE('E742',#736,#559,#743,.F.);
#745=ORIENTED_EDGE('',*,*,#744,.T.);
#746=ORIENTED_EDGE('',*,*,#560,.F.);
#747=ORIENTED_EDGE('',*,*,#154,.T.);
#748=EDGE_LOOP('',(#738,#745,#746,#747));
#749=FACE_BOUND('',#748,.T.);
#750=ADVANCED_FACE('F610',(#749),#723,.T.);
#751=CARTESIAN_POINT('',(24.1507575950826,-7.77817459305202,21.7));
#752=DIRECTION('',(0.707106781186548,-0.707106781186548,0.));
#753=DIRECTION('',(-0.707106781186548,-0.707106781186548,0.));
#754=AXIS2_PLACEMENT_3D('',#751,#752,#753);
#755=PLANE('',#754);
#756=ORIENTED_EDGE('',*,*,#420,.F.);
#757=DIRECTION('',(0.,0.,1.));
#758=VECTOR('',#757,1.);
#759=CARTESIAN_POINT('',(39.8803465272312,7.95141433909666,21.7));
#760=LINE('',#759,#758);
#761=EDGE_CURVE('E683',#419,#110,#760,.F.);
#762=ORIENTED_EDGE('',*,*,#761,.T.);
#763=ORIENTED_EDGE('',*,*,#111,.T.);
#764=DIRECTION('',(-0.707106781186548,-0.707106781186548,0.));
#765=VECTOR('',#764,1.);
#766=CARTESIAN_POINT('',(32.8835263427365,0.954594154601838,20.));
#767=LINE('',#766,#765);
#768=EDGE_CURVE('E738',#95,#736,#767,.T.);
#769=ORIENTED_EDGE('',*,*,#768,.T.);
#770=ORIENTED_EDGE('',*,*,#737,.T.);
#771=ORIENTED_EDGE('',*,*,#145,.T.);
#772=EDGE_LOOP('',(#756,#762,#763,#769,#770,#771));
#773=FACE_BOUND('',#772,.T.);
#774=ADVANCED_FACE('F428',(#773),#755,.F.);
#775=CARTESIAN_POINT('',(39.,0.,24.));
#776=DIRECTION('',(0.,0.,1.));
#777=DIRECTION('',(0.707106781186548,-0.707106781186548,0.));
#778=AXIS2_PLACEMENT_3D('',#775,#776,#777);
#779=PLANE('',#778);
#780=CARTESIAN_POINT('',(42.0759144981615,1.1667261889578,24.));
#781=DIRECTION('',(0.,0.,1.));
#782=DIRECTION('',(-0.707106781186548,0.707106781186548,0.));
#783=AXIS2_PLACEMENT_3D('',#780,#781,#782);
#784=CIRCLE('',#783,1.);
#785=CARTESIAN_POINT('',(42.7830212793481,1.87383297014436,24.));
#786=VERTEX_POINT('',#785);
#787=CARTESIAN_POINT('',(42.7830212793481,0.459619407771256,24.));
#788=VERTEX_POINT('',#787);
#789=EDGE_CURVE('E497',#786,#788,#784,.F.);
#790=ORIENTED_EDGE('',*,*,#789,.F.);
#791=DIRECTION('',(0.707106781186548,-0.707106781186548,0.));
#792=VECTOR('',#791,1.);
#793=CARTESIAN_POINT('',(41.8284271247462,2.8284271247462,24.));
#794=LINE('',#793,#792);
#795=CARTESIAN_POINT('',(40.8738329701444,3.78302127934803,24.));
#796=VERTEX_POINT('',#795);
#797=EDGE_CURVE('E754',#796,#786,#794,.T.);
#798=ORIENTED_EDGE('',*,*,#797,.F.);
#799=CARTESIAN_POINT('',(40.1667261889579,3.07591449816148,24.));
#800=DIRECTION('',(0.,0.,1.));
#801=DIRECTION('',(-0.707106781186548,0.707106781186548,0.));
#802=AXIS2_PLACEMENT_3D('',#799,#800,#801);
#803=CIRCLE('',#802,1.);
#804=CARTESIAN_POINT('',(39.4596194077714,3.78302127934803,24.));
#805=VERTEX_POINT('',#804);
#806=EDGE_CURVE('E676',#805,#796,#803,.F.);
#807=ORIENTED_EDGE('',*,*,#806,.F.);
#808=DIRECTION('',(0.707106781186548,0.707106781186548,0.));
#809=VECTOR('',#808,1.);
#810=CARTESIAN_POINT('',(39.4596194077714,3.78302127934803,24.));
#811=LINE('',#810,#809);
#812=EDGE_CURVE('E716',#529,#805,#811,.T.);
#813=ORIENTED_EDGE('',*,*,#812,.F.);
#814=ORIENTED_EDGE('',*,*,#530,.F.);
#815=DIRECTION('',(-0.707106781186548,-0.707106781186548,0.));
#816=VECTOR('',#815,1.);
#817=CARTESIAN_POINT('',(40.6617009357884,-1.66170093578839,24.));
#818=LINE('',#817,#816);
#819=EDGE_CURVE('E756',#788,#527,#818,.T.);
#820=ORIENTED_EDGE('',*,*,#819,.F.);
#821=EDGE_LOOP('',(#790,#798,#807,#813,#814,#820));
#822=FACE_BOUND('',#821,.T.);
#823=CARTESIAN_POINT('',(39.,0.,24.0000000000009));
#824=DIRECTION('',(0.,0.,-1.));
#825=DIRECTION('',(0.707106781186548,-0.707106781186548,0.));
#826=AXIS2_PLACEMENT_3D('',#823,#824,#825);
#827=CIRCLE('',#826,1.99999999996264);
#828=CARTESIAN_POINT('',(40.4142135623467,-1.41421356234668,24.0000000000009));
#829=VERTEX_POINT('',#828);
#830=EDGE_CURVE('E673',#829,#829,#827,.F.);
#831=ORIENTED_EDGE('',*,*,#830,.F.);
#832=EDGE_LOOP('',(#831));
#833=FACE_BOUND('',#832,.T.);
#834=ADVANCED_FACE('F901',(#822,#833),#779,.T.);
#835=CARTESIAN_POINT('',(32.1764195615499,-10.146982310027,24.));
#836=DIRECTION('',(0.707106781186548,-0.707106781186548,0.));
#837=DIRECTION('',(-0.707106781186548,-0.707106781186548,0.));
#838=AXIS2_PLACEMENT_3D('',#835,#836,#837);
#839=PLANE('',#838);
#840=CARTESIAN_POINT('',(37.516126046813,-4.80727582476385,33.9999999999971));
#841=CARTESIAN_POINT('',(37.5535863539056,-4.76981551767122,33.6665945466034));
#842=CARTESIAN_POINT('',(37.5912057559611,-4.73219611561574,33.3332251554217));
#843=CARTESIAN_POINT('',(37.6667627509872,-4.65663912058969,32.6665584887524));
#844=CARTESIAN_POINT('',(37.7047003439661,-4.61870152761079,32.3332612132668));
#845=CARTESIAN_POINT('',(37.7427970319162,-4.5806048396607,31.999999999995));
#846=B_SPLINE_CURVE_WITH_KNOTS('',3,(#840,#841,#842,#843,#844,#845),.UNSPECIFIED.,.F.,.F.,(4,2,
4),(0.,1.01276369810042,2.02552742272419),.UNSPECIFIED.);
#847=CARTESIAN_POINT('',(37.5161260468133,-4.80727582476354,33.9999999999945));
#848=VERTEX_POINT('',#847);
#849=CARTESIAN_POINT('',(37.7427970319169,-4.58060483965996,31.9999999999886));
#850=VERTEX_POINT('',#849);
#851=EDGE_CURVE('E662',#848,#850,#846,.T.);
#852=ORIENTED_EDGE('',*,*,#851,.T.);
#853=DIRECTION('',(-0.707106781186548,-0.707106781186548,0.));
#854=VECTOR('',#853,1.);
#855=CARTESIAN_POINT('',(32.1764195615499,-10.146982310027,32.));
#856=LINE('',#855,#854);
#857=CARTESIAN_POINT('',(42.7830212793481,0.459619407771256,32.));
#858=VERTEX_POINT('',#857);
#859=EDGE_CURVE('E667',#850,#858,#856,.F.);
#860=ORIENTED_EDGE('',*,*,#859,.T.);
#861=DIRECTION('',(0.,0.,1.));
#862=VECTOR('',#861,1.);
#863=CARTESIAN_POINT('',(42.7830212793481,0.459619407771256,24.));
#864=LINE('',#863,#862);
#865=EDGE_CURVE('E648',#858,#788,#864,.F.);
#866=ORIENTED_EDGE('',*,*,#865,.T.);
#867=ORIENTED_EDGE('',*,*,#819,.T.);
#868=ORIENTED_EDGE('',*,*,#582,.F.);
#869=ORIENTED_EDGE('',*,*,#637,.T.);
#870=DIRECTION('',(-0.707106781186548,-0.707106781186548,0.));
#871=VECTOR('',#870,1.);
#872=CARTESIAN_POINT('',(36.3020052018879,-6.02139666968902,34.));
#873=LINE('',#872,#871);
#874=EDGE_CURVE('E782',#629,#848,#873,.F.);
#875=ORIENTED_EDGE('',*,*,#874,.T.);
#876=EDGE_LOOP('',(#852,#860,#866,#867,#868,#869,#875));
#877=FACE_BOUND('',#876,.T.);
#878=CARTESIAN_POINT('',(40.6617009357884,-1.66170093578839,28.));
#879=DIRECTION('',(0.707106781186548,-0.707106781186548,0.));
#880=DIRECTION('',(0.707106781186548,0.707106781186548,0.));
#881=AXIS2_PLACEMENT_3D('',#878,#879,#880);
#882=CIRCLE('',#881,1.5);
#883=CARTESIAN_POINT('',(41.7223611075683,-0.601040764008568,28.));
#884=VERTEX_POINT('',#883);
#885=EDGE_CURVE('E663',#884,#884,#882,.T.);
#886=ORIENTED_EDGE('',*,*,#885,.T.);
#887=EDGE_LOOP('',(#886));
#888=FACE_BOUND('',#887,.T.);
#889=ADVANCED_FACE('F668',(#877,#888),#839,.F.);
#890=CARTESIAN_POINT('',(39.4596194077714,3.78302127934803,24.));
#891=DIRECTION('',(-0.707106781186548,0.707106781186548,0.));
#892=DIRECTION('',(0.707106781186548,0.707106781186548,0.));
#893=AXIS2_PLACEMENT_3D('',#890,#891,#892);
#894=PLANE('',#893);
#895=DIRECTION('',(0.,0.,1.));
#896=VECTOR('',#895,1.);
#897=CARTESIAN_POINT('',(39.4596194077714,3.78302127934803,24.));
#898=LINE('',#897,#896);
#899=CARTESIAN_POINT('',(39.4596194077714,3.78302127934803,32.));
#900=VERTEX_POINT('',#899);
#901=EDGE_CURVE('E713',#805,#900,#898,.T.);
#902=ORIENTED_EDGE('',*,*,#901,.T.);
#903=DIRECTION('',(0.707106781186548,0.707106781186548,0.));
#904=VECTOR('',#903,1.);
#905=CARTESIAN_POINT('',(39.4596194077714,3.78302127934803,32.));
#906=LINE('',#905,#904);
#907=CARTESIAN_POINT('',(34.4193951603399,-1.25720296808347,31.9999999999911));
#908=VERTEX_POINT('',#907);
#909=EDGE_CURVE('E710',#900,#908,#906,.F.);
#910=ORIENTED_EDGE('',*,*,#909,.T.);
#911=CARTESIAN_POINT('',(34.4193951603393,-1.25720296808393,31.999999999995));
#912=CARTESIAN_POINT('',(34.3812984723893,-1.29529965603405,32.3332612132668));
#913=CARTESIAN_POINT('',(34.3433608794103,-1.33323724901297,32.6665584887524));
#914=CARTESIAN_POINT('',(34.2678038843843,-1.40879424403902,33.3332251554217));
#915=CARTESIAN_POINT('',(34.2301844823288,-1.44641364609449,33.6665945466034));
#916=CARTESIAN_POINT('',(34.1927241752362,-1.48387395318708,33.9999999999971));
#917=B_SPLINE_CURVE_WITH_KNOTS('',3,(#911,#912,#913,#914,#915,#916),.UNSPECIFIED.,.F.,.F.,(4,2,
4),(0.,1.01276372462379,2.02552742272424),.UNSPECIFIED.);
#918=CARTESIAN_POINT('',(34.1927241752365,-1.4838739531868,33.9999999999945));
#919=VERTEX_POINT('',#918);
#920=EDGE_CURVE('E1076',#908,#919,#917,.T.);
#921=ORIENTED_EDGE('',*,*,#920,.T.);
#922=DIRECTION('',(-0.707106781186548,-0.707106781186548,0.));
#923=VECTOR('',#922,1.);
#924=CARTESIAN_POINT('',(32.9786033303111,-2.69799479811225,34.));
#925=LINE('',#924,#923);
#926=EDGE_CURVE('E544',#919,#707,#925,.T.);
#927=ORIENTED_EDGE('',*,*,#926,.T.);
#928=ORIENTED_EDGE('',*,*,#708,.T.);
#929=ORIENTED_EDGE('',*,*,#538,.F.);
#930=ORIENTED_EDGE('',*,*,#812,.T.);
#931=EDGE_LOOP('',(#902,#910,#921,#927,#928,#929,#930));
#932=FACE_BOUND('',#931,.T.);
#933=CARTESIAN_POINT('',(37.3382990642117,1.66170093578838,28.));
#934=DIRECTION('',(0.707106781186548,-0.707106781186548,0.));
#935=DIRECTION('',(0.707106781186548,0.707106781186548,0.));
#936=AXIS2_PLACEMENT_3D('',#933,#934,#935);
#937=CIRCLE('',#936,1.5);
#938=CARTESIAN_POINT('',(38.3989592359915,2.72236110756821,28.));
#939=VERTEX_POINT('',#938);
#940=EDGE_CURVE('E760',#939,#939,#937,.F.);
#941=ORIENTED_EDGE('',*,*,#940,.T.);
#942=EDGE_LOOP('',(#941));
#943=FACE_BOUND('',#942,.T.);
#944=ADVANCED_FACE('F558',(#932,#943),#894,.F.);
#945=CARTESIAN_POINT('',(34.6403042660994,-4.35969573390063,34.));
#946=DIRECTION('',(0.,0.,1.));
#947=DIRECTION('',(0.707106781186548,-0.707106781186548,0.));
#948=AXIS2_PLACEMENT_3D('',#945,#946,#947);
#949=PLANE('',#948);
#950=ORIENTED_EDGE('',*,*,#874,.F.);
#951=ORIENTED_EDGE('',*,*,#630,.F.);
#952=ORIENTED_EDGE('',*,*,#688,.T.);
#953=ORIENTED_EDGE('',*,*,#714,.F.);
#954=ORIENTED_EDGE('',*,*,#926,.F.);
#955=CARTESIAN_POINT('',(39.,0.,33.9999999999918));
#956=DIRECTION('',(0.,0.,-1.));
#957=DIRECTION('',(0.707106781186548,-0.707106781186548,0.));
#958=AXIS2_PLACEMENT_3D('',#955,#956,#957);
#959=CIRCLE('',#958,5.03108166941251);
#960=EDGE_CURVE('E546',#848,#919,#959,.F.);
#961=ORIENTED_EDGE('',*,*,#960,.F.);
#962=EDGE_LOOP('',(#950,#951,#952,#953,#954,#961));
#963=FACE_BOUND('',#962,.T.);
#964=ADVANCED_FACE('F556',(#963),#949,.T.);
#965=CARTESIAN_POINT('',(42.0759144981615,1.1667261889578,24.));
#966=DIRECTION('',(0.,0.,-1.));
#967=DIRECTION('',(-0.707106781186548,0.707106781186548,0.));
#968=AXIS2_PLACEMENT_3D('',#965,#966,#967);
#969=CYLINDRICAL_SURFACE('',#968,1.);
#970=ORIENTED_EDGE('',*,*,#865,.F.);
#971=CARTESIAN_POINT('',(42.0759144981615,1.1667261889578,32.));
#972=DIRECTION('',(0.,0.,1.));
#973=DIRECTION('',(-0.707106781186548,0.707106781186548,0.));
#974=AXIS2_PLACEMENT_3D('',#971,#972,#973);
#975=CIRCLE('',#974,1.);
#976=CARTESIAN_POINT('',(42.7830212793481,1.87383297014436,32.));
#977=VERTEX_POINT('',#976);
#978=EDGE_CURVE('E653',#858,#977,#975,.T.);
#979=ORIENTED_EDGE('',*,*,#978,.T.);
#980=DIRECTION('',(0.,0.,1.));
#981=VECTOR('',#980,1.);
#982=CARTESIAN_POINT('',(42.7830212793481,1.87383297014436,24.));
#983=LINE('',#982,#981);
#984=EDGE_CURVE('E695',#786,#977,#983,.T.);
#985=ORIENTED_EDGE('',*,*,#984,.F.);
#986=ORIENTED_EDGE('',*,*,#789,.T.);
#987=EDGE_LOOP('',(#970,#979,#985,#986));
#988=FACE_BOUND('',#987,.T.);
#989=ADVANCED_FACE('F624',(#988),#969,.F.);
#990=CARTESIAN_POINT('',(40.1667261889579,3.07591449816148,24.));
#991=DIRECTION('',(0.,0.,-1.));
#992=DIRECTION('',(-0.707106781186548,0.707106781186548,0.));
#993=AXIS2_PLACEMENT_3D('',#990,#991,#992);
#994=CYLINDRICAL_SURFACE('',#993,1.);
#995=DIRECTION('',(0.,0.,-1.));
#996=VECTOR('',#995,1.);
#997=CARTESIAN_POINT('',(40.8738329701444,3.78302127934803,24.));
#998=LINE('',#997,#996);
#999=CARTESIAN_POINT('',(40.8738329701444,3.78302127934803,32.));
#1000=VERTEX_POINT('',#999);
#1001=EDGE_CURVE('E681',#796,#1000,#998,.F.);
#1002=ORIENTED_EDGE('',*,*,#1001,.T.);
#1003=CARTESIAN_POINT('',(40.1667261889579,3.07591449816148,32.));
#1004=DIRECTION('',(0.,0.,1.));
#1005=DIRECTION('',(-0.707106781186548,0.707106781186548,0.));
#1006=AXIS2_PLACEMENT_3D('',#1003,#1004,#1005);
#1007=CIRCLE('',#1006,1.);
#1008=EDGE_CURVE('E719',#1000,#900,#1007,.T.);
#1009=ORIENTED_EDGE('',*,*,#1008,.T.);
#1010=ORIENTED_EDGE('',*,*,#901,.F.);
#1011=ORIENTED_EDGE('',*,*,#806,.T.);
#1012=EDGE_LOOP('',(#1002,#1009,#1010,#1011));
#1013=FACE_BOUND('',#1012,.T.);
#1014=ADVANCED_FACE('F620',(#1013),#994,.F.);
#1015=CARTESIAN_POINT('',(42.7830212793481,1.87383297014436,24.));
#1016=DIRECTION('',(0.707106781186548,0.707106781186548,0.));
#1017=DIRECTION('',(0.707106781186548,-0.707106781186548,0.));
#1018=AXIS2_PLACEMENT_3D('',#1015,#1016,#1017);
#1019=PLANE('',#1018);
#1020=ORIENTED_EDGE('',*,*,#984,.T.);
#1021=DIRECTION('',(0.707106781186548,-0.707106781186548,0.));
#1022=VECTOR('',#1021,1.);
#1023=CARTESIAN_POINT('',(41.8284271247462,2.8284271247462,32.));
#1024=LINE('',#1023,#1022);
#1025=EDGE_CURVE('E717',#977,#1000,#1024,.F.);
#1026=ORIENTED_EDGE('',*,*,#1025,.T.);
#1027=ORIENTED_EDGE('',*,*,#1001,.F.);
#1028=ORIENTED_EDGE('',*,*,#797,.T.);
#1029=EDGE_LOOP('',(#1020,#1026,#1027,#1028));
#1030=FACE_BOUND('',#1029,.T.);
#1031=ADVANCED_FACE('F623',(#1030),#1019,.F.);
#1032=CARTESIAN_POINT('',(39.,0.,24.0000000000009));
#1033=DIRECTION('',(0.,0.,1.));
#1034=DIRECTION('',(0.707106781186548,-0.707106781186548,0.));
#1035=AXIS2_PLACEMENT_3D('',#1032,#1033,#1034);
#1036=CONICAL_SURFACE('',#1035,1.99999999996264,0.785398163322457);
#1037=ORIENTED_EDGE('',*,*,#830,.T.);
#1038=EDGE_LOOP('',(#1037));
#1039=FACE_BOUND('',#1038,.T.);
#1040=ORIENTED_EDGE('',*,*,#59,.T.);
#1041=EDGE_LOOP('',(#1040));
#1042=FACE_BOUND('',#1041,.T.);
#1043=ADVANCED_FACE('F632',(#1039,#1042),#1036,.F.);
#1044=CARTESIAN_POINT('',(39.,0.,33.9999999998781));
#1045=DIRECTION('',(0.,0.,1.));
#1046=DIRECTION('',(0.707106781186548,-0.707106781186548,0.));
#1047=AXIS2_PLACEMENT_3D('',#1044,#1045,#1046);
#1048=CONICAL_SURFACE('',#1047,5.03108166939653,0.13962634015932);
#1049=CARTESIAN_POINT('',(39.,0.,31.9999999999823));
#1050=DIRECTION('',(0.,0.,-1.));
#1051=DIRECTION('',(0.707106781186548,-0.707106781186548,0.));
#1052=AXIS2_PLACEMENT_3D('',#1049,#1050,#1051);
#1053=CIRCLE('',#1052,4.75000000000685);
#1054=EDGE_CURVE('E605',#908,#850,#1053,.T.);
#1055=ORIENTED_EDGE('',*,*,#1054,.T.);
#1056=ORIENTED_EDGE('',*,*,#851,.F.);
#1057=ORIENTED_EDGE('',*,*,#960,.T.);
#1058=ORIENTED_EDGE('',*,*,#920,.F.);
#1059=EDGE_LOOP('',(#1055,#1056,#1057,#1058));
#1060=FACE_BOUND('',#1059,.T.);
#1061=ADVANCED_FACE('F612',(#1060),#1048,.F.);
#1062=CARTESIAN_POINT('',(37.320621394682,-1.67937860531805,32.));
#1063=DIRECTION('',(0.,0.,1.));
#1064=DIRECTION('',(0.707106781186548,-0.707106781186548,0.));
#1065=AXIS2_PLACEMENT_3D('',#1062,#1063,#1064);
#1066=PLANE('',#1065);
#1067=ORIENTED_EDGE('',*,*,#1025,.F.);
#1068=ORIENTED_EDGE('',*,*,#978,.F.);
#1069=ORIENTED_EDGE('',*,*,#859,.F.);
#1070=ORIENTED_EDGE('',*,*,#1054,.F.);
#1071=ORIENTED_EDGE('',*,*,#909,.F.);
#1072=ORIENTED_EDGE('',*,*,#1008,.F.);
#1073=EDGE_LOOP('',(#1067,#1068,#1069,#1070,#1071,#1072));
#1074=FACE_BOUND('',#1073,.T.);
#1075=ADVANCED_FACE('F614',(#1074),#1066,.T.);
#1076=CARTESIAN_POINT('',(39.,0.,28.));
#1077=DIRECTION('',(-0.707106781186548,0.707106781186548,0.));
#1078=DIRECTION('',(0.707106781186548,0.707106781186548,0.));
#1079=AXIS2_PLACEMENT_3D('',#1076,#1077,#1078);
#1080=CYLINDRICAL_SURFACE('',#1079,1.5);
#1081=ORIENTED_EDGE('',*,*,#940,.F.);
#1082=EDGE_LOOP('',(#1081));
#1083=FACE_BOUND('',#1082,.T.);
#1084=ORIENTED_EDGE('',*,*,#885,.F.);
#1085=EDGE_LOOP('',(#1084));
#1086=FACE_BOUND('',#1085,.T.);
#1087=ADVANCED_FACE('F618',(#1083,#1086),#1080,.T.);
#1088=CARTESIAN_POINT('',(0.,0.,20.));
#1089=DIRECTION('',(0.,0.,1.));
#1090=DIRECTION('',(0.707106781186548,-0.707106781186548,0.));
#1091=AXIS2_PLACEMENT_3D('',#1088,#1089,#1090);
#1092=PLANE('',#1091);
#1093=ORIENTED_EDGE('',*,*,#31,.F.);
#1094=EDGE_LOOP('',(#1093));
#1095=FACE_BOUND('',#1094,.T.);
#1096=ADVANCED_FACE('F628',(#1095),#1092,.T.);
#1097=CARTESIAN_POINT('',(0.,0.,31.0603978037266));
#1098=DIRECTION('',(0.,0.,-1.));
#1099=DIRECTION('',(-0.707106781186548,0.707106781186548,0.));
#1100=AXIS2_PLACEMENT_3D('',#1097,#1098,#1099);
#1101=CONICAL_SURFACE('',#1100,49.1642913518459,1.48855798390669);
#1102=CARTESIAN_POINT('',(0.,0.,34.));
#1103=DIRECTION('',(0.,0.,1.));
#1104=DIRECTION('',(-0.707106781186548,-0.707106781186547,0.));
#1105=AXIS2_PLACEMENT_3D('',#1102,#1103,#1104);
#1106=CIRCLE('',#1105,13.5);
#1107=CARTESIAN_POINT('',(-9.5459415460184,-9.54594154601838,34.));
#1108=VERTEX_POINT('',#1107);
#1109=EDGE_CURVE('E312',#1108,#1108,#1106,.T.);
#1110=ORIENTED_EDGE('',*,*,#1109,.F.);
#1111=EDGE_LOOP('',(#1110));
#1112=FACE_BOUND('',#1111,.T.);
#1113=CARTESIAN_POINT('',(24.594591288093,-27.1333307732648,32.0942534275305));
#1114=CARTESIAN_POINT('',(25.017703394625,-26.7101981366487,32.0966714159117));
#1115=CARTESIAN_POINT('',(25.4306562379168,-26.2777999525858,32.0990143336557));
#1116=CARTESIAN_POINT('',(26.236243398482,-25.3944724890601,32.1035500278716));
#1117=CARTESIAN_POINT('',(26.6288777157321,-24.943543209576,32.1057428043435));
#1118=CARTESIAN_POINT('',(27.0113527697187,-24.4833483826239,32.107860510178));
#1119=B_SPLINE_CURVE_WITH_KNOTS('',3,(#1113,#1114,#1115,#1116,#1117,#1118),.UNSPECIFIED.,.F.,
.F.,(4,2,4),(0.,1.79374846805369,3.5874969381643),.UNSPECIFIED.);
#1120=CARTESIAN_POINT('',(24.5945912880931,-27.1333307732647,32.0942534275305));
#1121=VERTEX_POINT('',#1120);
#1122=CARTESIAN_POINT('',(27.0113527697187,-24.4833483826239,32.107860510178));
#1123=VERTEX_POINT('',#1122);
#1124=EDGE_CURVE('E189',#1121,#1123,#1119,.T.);
#1125=ORIENTED_EDGE('',*,*,#1124,.F.);
#1126=CARTESIAN_POINT('',(18.5636457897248,-33.164276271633,31.9800875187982));
#1127=CARTESIAN_POINT('',(19.0661554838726,-32.6617665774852,31.996002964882));
#1128=CARTESIAN_POINT('',(19.56868976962,-32.1592322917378,32.0103900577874));
#1129=CARTESIAN_POINT('',(20.5737880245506,-31.1541340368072,32.0359939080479));
#1130=CARTESIAN_POINT('',(21.0763519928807,-30.6515700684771,32.0472107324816));
#1131=CARTESIAN_POINT('',(22.0815119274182,-29.6464101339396,32.0663611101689));
#1132=CARTESIAN_POINT('',(22.5841078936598,-29.143814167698,32.0742946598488));
#1133=CARTESIAN_POINT('',(23.589331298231,-28.1385907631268,32.0868075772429));
#1134=CARTESIAN_POINT('',(24.0919587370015,-27.6359633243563,32.0913868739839));
#1135=CARTESIAN_POINT('',(24.594591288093,-27.1333307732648,32.0942534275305));
#1136=B_SPLINE_CURVE_WITH_KNOTS('',3,(#1126,#1127,#1128,#1129,#1130,#1131,#1132,#1133,#1134,
#1135),.UNSPECIFIED.,.F.,.F.,(4,2,2,2,4),(0.,2.13250182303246,4.26495852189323,6.39741754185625,
8.52992168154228),.UNSPECIFIED.);
#1137=CARTESIAN_POINT('',(18.5636457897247,-33.164276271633,31.9800875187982));
#1138=VERTEX_POINT('',#1137);
#1139=EDGE_CURVE('E220',#1138,#1121,#1136,.T.);
#1140=ORIENTED_EDGE('',*,*,#1139,.F.);
#1141=CARTESIAN_POINT('',(13.2708289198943,-37.5934838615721,31.8267125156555));
#1142=CARTESIAN_POINT('',(13.743915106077,-37.264109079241,31.8393331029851));
#1143=CARTESIAN_POINT('',(14.2096872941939,-36.9242329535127,31.8520117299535));
#1144=CARTESIAN_POINT('',(15.1248149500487,-36.2248611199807,31.8774382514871));
#1145=CARTESIAN_POINT('',(15.5742007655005,-35.8654051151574,31.8901859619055));
#1146=CARTESIAN_POINT('',(16.4566257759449,-35.1269617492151,31.9157534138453));
#1147=CARTESIAN_POINT('',(16.8896649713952,-34.7479743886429,31.9285731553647));
#1148=CARTESIAN_POINT('',(17.7393900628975,-33.9704577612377,31.9542867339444));
#1149=CARTESIAN_POINT('',(18.1560422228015,-33.5718916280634,31.9671806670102));
#1150=CARTESIAN_POINT('',(18.5636457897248,-33.164276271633,31.9800875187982));
#1151=B_SPLINE_CURVE_WITH_KNOTS('',3,(#1141,#1142,#1143,#1144,#1145,#1146,#1147,#1148,#1149,
#1150),.UNSPECIFIED.,.F.,.F.,(4,2,2,2,4),(0.,1.72963098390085,3.45587660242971,5.18212217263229,
6.91175310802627),.UNSPECIFIED.);
#1152=CARTESIAN_POINT('',(13.2708289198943,-37.5934838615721,31.8267125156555));
#1153=VERTEX_POINT('',#1152);
#1154=EDGE_CURVE('E227',#1153,#1138,#1151,.T.);
#1155=ORIENTED_EDGE('',*,*,#1154,.F.);
#1156=CARTESIAN_POINT('',(3.67324410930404,-44.2757756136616,31.4507924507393));
#1157=CARTESIAN_POINT('',(4.47279265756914,-43.7190921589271,31.4910701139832));
#1158=CARTESIAN_POINT('',(5.27240961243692,-43.1623610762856,31.5293759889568));
#1159=CARTESIAN_POINT('',(6.87175658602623,-42.0488201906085,31.601641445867));
#1160=CARTESIAN_POINT('',(7.6714866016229,-41.4920103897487,31.6356011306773));
#1161=CARTESIAN_POINT('',(9.27107664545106,-40.3783002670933,31.6987735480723));
#1162=CARTESIAN_POINT('',(10.0709366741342,-39.8213999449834,31.7279862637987));
#1163=CARTESIAN_POINT('',(11.6707903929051,-38.7075062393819,31.7812874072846));
#1164=CARTESIAN_POINT('',(12.4707840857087,-38.1505128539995,31.8053757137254));
#1165=CARTESIAN_POINT('',(13.2708289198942,-37.5934838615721,31.8267125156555));
#1166=B_SPLINE_CURVE_WITH_KNOTS('',3,(#1156,#1157,#1158,#1159,#1160,#1161,#1162,#1163,#1164,
#1165),.UNSPECIFIED.,.F.,.F.,(4,2,2,2,4),(0.,2.92526472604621,5.85046019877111,8.77566605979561,
11.7009411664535),.UNSPECIFIED.);
#1167=CARTESIAN_POINT('',(3.67324410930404,-44.2757756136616,31.4507924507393));
#1168=VERTEX_POINT('',#1167);
#1169=EDGE_CURVE('E234',#1168,#1153,#1166,.T.);
#1170=ORIENTED_EDGE('',*,*,#1169,.F.);
#1171=CARTESIAN_POINT('',(-5.27577561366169,-35.3267558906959,32.168654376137));
#1172=CARTESIAN_POINT('',(-5.37946153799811,-35.4756434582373,32.1552539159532));
#1173=CARTESIAN_POINT('',(-5.47679824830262,-35.6289199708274,32.1415520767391));
#1174=CARTESIAN_POINT('',(-5.65815790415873,-35.9431041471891,32.1136659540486));
#1175=CARTESIAN_POINT('',(-5.74218160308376,-36.1040113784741,32.099481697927));
#1176=CARTESIAN_POINT('',(-5.8962567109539,-36.432210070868,32.0707597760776));
#1177=CARTESIAN_POINT('',(-5.96631806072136,-36.5994968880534,32.056222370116));
#1178=CARTESIAN_POINT('',(-6.09205669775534,-36.9393686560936,32.0269008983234));
#1179=CARTESIAN_POINT('',(-6.14773411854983,-37.1119535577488,32.0121168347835));
#1180=CARTESIAN_POINT('',(-6.24432477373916,-37.4612405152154,31.9824114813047));
#1181=CARTESIAN_POINT('',(-6.2852344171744,-37.6379435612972,31.9674901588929));
#1182=CARTESIAN_POINT('',(-6.35199453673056,-37.994237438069,31.9376176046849));
#1183=CARTESIAN_POINT('',(-6.37783944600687,-38.1738293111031,31.9226663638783));
#1184=CARTESIAN_POINT('',(-6.4142522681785,-38.5344617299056,31.8928527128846));
#1185=CARTESIAN_POINT('',(-6.42482859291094,-38.7155014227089,31.8779902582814));
#1186=CARTESIAN_POINT('',(-6.43065440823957,-39.0779089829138,31.8484404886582));
#1187=CARTESIAN_POINT('',(-6.42589824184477,-39.2592769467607,31.8337532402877));
#1188=CARTESIAN_POINT('',(-6.40107328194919,-39.6210207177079,31.8046517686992));
#1189=CARTESIAN_POINT('',(-6.38100142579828,-39.8013963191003,31.7902376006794));
#1190=CARTESIAN_POINT('',(-6.32566762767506,-40.1599001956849,31.7617701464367));
#1191=CARTESIAN_POINT('',(-6.29040007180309,-40.338027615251,31.7477169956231));
#1192=CARTESIAN_POINT('',(-6.20492719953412,-40.6906550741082,31.7200651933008));
#1193=CARTESIAN_POINT('',(-6.15472525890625,-40.8651559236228,31.706466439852));
#1194=CARTESIAN_POINT('',(-6.03970872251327,-41.209387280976,31.6797947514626));
#1195=CARTESIAN_POINT('',(-5.97488874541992,-41.3791160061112,31.6667220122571));
#1196=CARTESIAN_POINT('',(-5.83122160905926,-41.7122375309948,31.6412035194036));
#1197=CARTESIAN_POINT('',(-5.75239823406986,-41.8756405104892,31.6287567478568));
#1198=CARTESIAN_POINT('',(-5.58117173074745,-42.1952996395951,31.6045308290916));
#1199=CARTESIAN_POINT('',(-5.48876361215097,-42.3515531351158,31.5927519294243));
#1200=CARTESIAN_POINT('',(-5.29106608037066,-42.6556855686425,31.5699331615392));
#1201=CARTESIAN_POINT('',(-5.18578004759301,-42.8035666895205,31.5588931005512));
#1202=CARTESIAN_POINT('',(-4.9630493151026,-43.0899360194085,31.5376065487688));
#1203=CARTESIAN_POINT('',(-4.84560439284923,-43.2284240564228,31.5273600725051));
#1204=CARTESIAN_POINT('',(-4.59969622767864,-43.4946728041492,31.5077382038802));
#1205=CARTESIAN_POINT('',(-4.47126105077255,-43.6224592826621,31.498360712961));
#1206=CARTESIAN_POINT('',(-4.20403196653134,-43.8667668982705,31.4804955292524));
#1207=CARTESIAN_POINT('',(-4.06523807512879,-43.9832880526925,31.4720078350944));
#1208=CARTESIAN_POINT('',(-3.77827305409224,-44.2042266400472,31.4559641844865));
#1209=CARTESIAN_POINT('',(-3.63010167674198,-44.3086437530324,31.4484082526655));
#1210=CARTESIAN_POINT('',(-3.32544324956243,-44.5046127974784,31.4342655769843));
#1211=CARTESIAN_POINT('',(-3.16895639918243,-44.5961650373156,31.4276788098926));
#1212=CARTESIAN_POINT('',(-2.84917224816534,-44.765535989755,31.4155210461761));
#1213=CARTESIAN_POINT('',(-2.68589253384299,-44.8433877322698,31.4099476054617));
#1214=CARTESIAN_POINT('',(-2.35338959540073,-44.9850423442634,31.3998251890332));
#1215=CARTESIAN_POINT('',(-2.18416860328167,-45.0488504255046,31.3952758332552));
#1216=CARTESIAN_POINT('',(-1.84088119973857,-45.1620093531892,31.3872193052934));
#1217=CARTESIAN_POINT('',(-1.66681339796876,-45.211356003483,31.3837124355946));
#1218=CARTESIAN_POINT('',(-1.3151868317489,-45.2951941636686,31.3777602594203));
#1219=CARTESIAN_POINT('',(-1.13762938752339,-45.3296911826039,31.3753145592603));
#1220=CARTESIAN_POINT('',(-0.780540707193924,-45.3835596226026,31.3714976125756));
#1221=CARTESIAN_POINT('',(-0.601013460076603,-45.4029573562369,31.370124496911));
#1222=CARTESIAN_POINT('',(-0.241025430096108,-45.4265825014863,31.3684523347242));
#1223=CARTESIAN_POINT('',(-0.0605650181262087,-45.4308155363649,31.3681528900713));
#1224=CARTESIAN_POINT('',(0.300205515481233,-45.4240938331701,31.3686285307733));
#1225=CARTESIAN_POINT('',(0.480515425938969,-45.4131278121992,31.3694044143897));
#1226=CARTESIAN_POINT('',(0.839499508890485,-45.3760740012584,31.3720280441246));
#1227=CARTESIAN_POINT('',(1.01817426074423,-45.3499917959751,31.373875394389));
#1228=CARTESIAN_POINT('',(1.37274716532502,-45.2828866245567,31.3786338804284));
#1229=CARTESIAN_POINT('',(1.54864430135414,-45.241858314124,31.3815453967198));
#1230=CARTESIAN_POINT('',(1.89628086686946,-45.1451757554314,31.3884172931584));
#1231=CARTESIAN_POINT('',(2.06802184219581,-45.0895270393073,31.3923772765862));
#1232=CARTESIAN_POINT('',(2.40597014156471,-44.9640831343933,31.4013219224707));
#1233=CARTESIAN_POINT('',(2.57218432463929,-44.8943063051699,31.4063052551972));
#1234=CARTESIAN_POINT('',(2.89807311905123,-44.7410882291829,31.4172744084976));
#1235=CARTESIAN_POINT('',(3.05775118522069,-44.657654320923,31.4232596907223));
#1236=CARTESIAN_POINT('',(3.29229340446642,-44.5222820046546,31.4329984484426));
#1237=CARTESIAN_POINT('',(3.37001225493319,-44.4751988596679,31.436389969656));
#1238=CARTESIAN_POINT('',(3.52326416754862,-44.3778588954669,31.4434120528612));
#1239=CARTESIAN_POINT('',(3.59880028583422,-44.3276068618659,31.4470422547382));
#1240=CARTESIAN_POINT('',(3.67324410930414,-44.2757756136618,31.4507924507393));
#1241=B_SPLINE_CURVE_WITH_KNOTS('',3,(#1171,#1172,#1173,#1174,#1175,#1176,#1177,#1178,#1179,
#1180,#1181,#1182,#1183,#1184,#1185,#1186,#1187,#1188,#1189,#1190,#1191,#1192,#1193,#1194,#1195,
#1196,#1197,#1198,#1199,#1200,#1201,#1202,#1203,#1204,#1205,#1206,#1207,#1208,#1209,#1210,#1211,
#1212,#1213,#1214,#1215,#1216,#1217,#1218,#1219,#1220,#1221,#1222,#1223,#1224,#1225,#1226,#1227,
#1228,#1229,#1230,#1231,#1232,#1233,#1234,#1235,#1236,#1237,#1238,#1239,#1240),.UNSPECIFIED.,
.F.,.F.,(4,2,2,2,2,2,2,2,2,2,2,2,2,2,2,2,2,2,2,2,2,2,2,2,2,2,2,2,2,2,2,2,2,2,4),(0.,
0.545616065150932,1.09120124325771,1.6363965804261,2.18158685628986,2.72690961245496,
3.27243375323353,3.81765723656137,4.36308190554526,4.90861567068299,5.45435115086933,
5.99996336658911,6.54577676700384,7.09067183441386,7.63576756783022,8.18072052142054,
8.72568345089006,9.26929401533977,9.81290374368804,10.3565278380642,10.9001388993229,
11.4424208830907,11.9845012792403,12.5267388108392,13.0687750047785,13.6098644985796,
14.1507533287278,14.692043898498,15.2331346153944,15.7744190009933,16.3154988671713,
16.8558800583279,17.3959718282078,17.6686955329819,17.9410168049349),.UNSPECIFIED.);
#1242=CARTESIAN_POINT('',(-5.27577561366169,-35.3267558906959,32.168654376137));
#1243=VERTEX_POINT('',#1242);
#1244=EDGE_CURVE('E241',#1243,#1168,#1241,.T.);
#1245=ORIENTED_EDGE('',*,*,#1244,.F.);
#1246=CARTESIAN_POINT('',(1.40651613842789,-25.7291710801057,32.9888534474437));
#1247=CARTESIAN_POINT('',(0.849462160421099,-26.5292518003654,32.9254753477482));
#1248=CARTESIAN_POINT('',(0.292470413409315,-27.329243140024,32.8604522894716));
#1249=CARTESIAN_POINT('',(-0.821407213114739,-28.9290737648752,32.7277481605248));
#1250=CARTESIAN_POINT('',(-1.37829309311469,-29.7289130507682,32.6600671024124));
#1251=CARTESIAN_POINT('',(-2.49198168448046,-31.32847216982,32.5226784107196));
#1252=CARTESIAN_POINT('',(-3.04878439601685,-32.1281920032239,32.4529707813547));
#1253=CARTESIAN_POINT('',(-4.16232531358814,-33.727539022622,32.3119306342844));
#1254=CARTESIAN_POINT('',(-4.71906351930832,-34.5271662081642,32.2405981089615));
#1255=CARTESIAN_POINT('',(-5.27577561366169,-35.3267558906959,32.168654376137));
#1256=B_SPLINE_CURVE_WITH_KNOTS('',3,(#1246,#1247,#1248,#1249,#1250,#1251,#1252,#1253,#1254,
#1255),.UNSPECIFIED.,.F.,.F.,(4,2,2,2,4),(0.,2.93088230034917,5.86175075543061,8.79261311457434,
11.7234892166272),.UNSPECIFIED.);
#1257=CARTESIAN_POINT('',(1.40651613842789,-25.7291710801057,32.9888534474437));
#1258=VERTEX_POINT('',#1257);
#1259=EDGE_CURVE('E265',#1258,#1243,#1256,.T.);
#1260=ORIENTED_EDGE('',*,*,#1259,.F.);
#1261=CARTESIAN_POINT('',(5.83572372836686,-20.4363542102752,33.3609450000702));
#1262=CARTESIAN_POINT('',(5.42782151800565,-20.8442446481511,33.3378463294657));
#1263=CARTESIAN_POINT('',(5.02905326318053,-21.2611242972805,33.3123534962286));
#1264=CARTESIAN_POINT('',(4.25129424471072,-22.1111543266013,33.2572542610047));
#1265=CARTESIAN_POINT('',(3.87226568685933,-22.5442706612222,33.2276561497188));
#1266=CARTESIAN_POINT('',(3.13386862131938,-23.4266939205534,33.164924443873));
#1267=CARTESIAN_POINT('',(2.77449995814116,-23.8760007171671,33.131790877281));
#1268=CARTESIAN_POINT('',(2.07538735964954,-24.7908299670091,33.0624677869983));
#1269=CARTESIAN_POINT('',(1.73568400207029,-25.2563829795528,33.0262722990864));
#1270=CARTESIAN_POINT('',(1.40651613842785,-25.7291710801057,32.9888534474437));
#1271=B_SPLINE_CURVE_WITH_KNOTS('',3,(#1261,#1262,#1263,#1264,#1265,#1266,#1267,#1268,#1269,
#1270),.UNSPECIFIED.,.F.,.F.,(4,2,2,2,4),(0.,1.73178798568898,3.4601281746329,5.18845469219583,
6.92022890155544),.UNSPECIFIED.);
#1272=CARTESIAN_POINT('',(5.83572372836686,-20.4363542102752,33.3609450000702));
#1273=VERTEX_POINT('',#1272);
#1274=EDGE_CURVE('E272',#1273,#1258,#1271,.T.);
#1275=ORIENTED_EDGE('',*,*,#1274,.F.);
#1276=CARTESIAN_POINT('',(11.866669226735,-14.405408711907,33.5743860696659));
#1277=CARTESIAN_POINT('',(11.3639054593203,-14.9081724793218,33.5687830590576));
#1278=CARTESIAN_POINT('',(10.8611636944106,-15.4109142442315,33.5597935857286));
#1279=CARTESIAN_POINT('',(9.85578826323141,-16.4162896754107,33.5355326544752));
#1280=CARTESIAN_POINT('',(9.3531545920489,-16.9189233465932,33.5202616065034));
#1281=CARTESIAN_POINT('',(8.34799979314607,-17.924078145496,33.483927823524));
#1282=CARTESIAN_POINT('',(7.84547866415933,-18.4265992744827,33.4628651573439));
#1283=CARTESIAN_POINT('',(6.84052391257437,-19.4315540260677,33.4155983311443));
#1284=CARTESIAN_POINT('',(6.3380902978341,-19.933987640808,33.3893938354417));
#1285=CARTESIAN_POINT('',(5.83572372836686,-20.4363542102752,33.3609450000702));
#1286=B_SPLINE_CURVE_WITH_KNOTS('',3,(#1276,#1277,#1278,#1279,#1280,#1281,#1282,#1283,#1284,
#1285),.UNSPECIFIED.,.F.,.F.,(4,2,2,2,4),(0.,2.13309794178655,4.26605669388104,6.39899009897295,
8.53206279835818),.UNSPECIFIED.);
#1287=CARTESIAN_POINT('',(11.866669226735,-14.405408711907,33.5743860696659));
#1288=VERTEX_POINT('',#1287);
#1289=EDGE_CURVE('E279',#1288,#1273,#1286,.T.);
#1290=ORIENTED_EDGE('',*,*,#1289,.F.);
#1291=CARTESIAN_POINT('',(14.5166516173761,-11.9886472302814,33.5609153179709));
#1292=CARTESIAN_POINT('',(14.2866640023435,-12.1797824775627,33.56550582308));
#1293=CARTESIAN_POINT('',(14.0588699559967,-12.3735696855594,33.569240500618));
#1294=CARTESIAN_POINT('',(13.6079138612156,-12.7662327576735,33.5749795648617));
#1295=CARTESIAN_POINT('',(13.3847492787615,-12.9651056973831,33.5769849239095));
#1296=CARTESIAN_POINT('',(12.7220888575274,-13.5694427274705,33.5803858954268));
#1297=CARTESIAN_POINT('',(12.2895236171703,-13.9825441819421,33.5791644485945));
#1298=CARTESIAN_POINT('',(11.8666692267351,-14.4054087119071,33.5743860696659));
#1299=B_SPLINE_CURVE_WITH_KNOTS('',3,(#1291,#1292,#1293,#1294,#1295,#1296,#1297,#1298),
.UNSPECIFIED.,.F.,.F.,(4,2,2,4),(0.,0.897204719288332,1.79390463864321,3.5876835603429),.UNSPECIFIED.);
#1300=CARTESIAN_POINT('',(14.5166516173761,-11.9886472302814,33.5609153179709));
#1301=VERTEX_POINT('',#1300);
#1302=EDGE_CURVE('E286',#1301,#1288,#1299,.T.);
#1303=ORIENTED_EDGE('',*,*,#1302,.F.);
#1304=CARTESIAN_POINT('',(31.2290449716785,1.90059400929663,32.5339342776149));
#1305=CARTESIAN_POINT('',(30.5333694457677,1.32243590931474,32.5940377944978));
#1306=CARTESIAN_POINT('',(29.8376373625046,0.744230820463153,32.6530659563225));
#1307=CARTESIAN_POINT('',(28.4460321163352,-0.412296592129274,32.7683233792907));
#1308=CARTESIAN_POINT('',(27.7501589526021,-0.990618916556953,32.8245526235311));
#1309=CARTESIAN_POINT('',(26.3583617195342,-2.14730587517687,32.9335546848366));
#1310=CARTESIAN_POINT('',(25.6624376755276,-2.72567048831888,32.986328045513));
#1311=CARTESIAN_POINT('',(24.2704020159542,-3.88255559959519,33.0875644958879));
#1312=CARTESIAN_POINT('',(23.5742904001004,-4.46107609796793,33.1360275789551));
#1313=CARTESIAN_POINT('',(22.1817756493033,-5.61835936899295,33.2275960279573));
#1314=CARTESIAN_POINT('',(21.4853724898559,-6.19712216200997,33.2707007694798));
#1315=CARTESIAN_POINT('',(20.0923433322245,-7.35483294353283,33.3502954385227));
#1316=CARTESIAN_POINT('',(19.3957173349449,-7.93378093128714,33.3867853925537));
#1317=CARTESIAN_POINT('',(18.0021363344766,-9.09195033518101,33.4517698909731));
#1318=CARTESIAN_POINT('',(17.3051812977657,-9.67117177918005,33.4802632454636));
#1319=CARTESIAN_POINT('',(16.2595959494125,-10.5401309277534,33.5159838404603));
#1320=CARTESIAN_POINT('',(15.911035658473,-10.8298104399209,33.526720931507));
#1321=CARTESIAN_POINT('',(15.2138729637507,-11.4092044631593,33.5457141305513));
#1322=CARTESIAN_POINT('',(14.8652705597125,-11.6989189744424,33.5539702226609));
#1323=CARTESIAN_POINT('',(14.5166516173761,-11.9886472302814,33.5609153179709));
#1324=B_SPLINE_CURVE_WITH_KNOTS('',3,(#1304,#1305,#1306,#1307,#1308,#1309,#1310,#1311,#1312,
#1313,#1314,#1315,#1316,#1317,#1318,#1319,#1320,#1321,#1322,#1323),.UNSPECIFIED.,.F.,.F.,(4,2,2,
2,2,2,2,2,2,4),(0.,2.71967026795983,5.43935695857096,8.15861480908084,10.8778768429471,
13.5974554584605,16.3170231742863,19.0369953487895,20.3970311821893,21.7570757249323),.UNSPECIFIED.);
#1325=EDGE_CURVE('E39',#397,#1301,#1324,.T.);
#1326=ORIENTED_EDGE('',*,*,#1325,.F.);
#1327=ORIENTED_EDGE('',*,*,#398,.F.);
#1328=CARTESIAN_POINT('',(27.0113527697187,-24.4833483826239,32.107860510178));
#1329=CARTESIAN_POINT('',(27.5902691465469,-23.7867604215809,32.1110818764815));
#1330=CARTESIAN_POINT('',(28.169191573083,-23.0901651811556,32.1114936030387));
#1331=CARTESIAN_POINT('',(29.3270258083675,-21.6969874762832,32.1067635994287));
#1332=CARTESIAN_POINT('',(29.9059376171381,-21.0004050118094,32.1016218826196));
#1333=CARTESIAN_POINT('',(31.0636607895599,-19.607360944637,32.0858517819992));
#1334=CARTESIAN_POINT('',(31.6424721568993,-18.9108993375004,32.075224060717));
#1335=CARTESIAN_POINT('',(32.8000442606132,-17.5180370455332,32.0486619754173));
#1336=CARTESIAN_POINT('',(33.3788049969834,-16.8216363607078,32.0327276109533));
#1337=CARTESIAN_POINT('',(35.1149597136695,-14.7325877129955,31.9773166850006));
#1338=CARTESIAN_POINT('',(36.2722578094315,-13.3400551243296,31.9302318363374));
#1339=CARTESIAN_POINT('',(38.0080037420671,-11.2514983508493,31.846294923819));
#1340=CARTESIAN_POINT('',(38.5865891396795,-10.555308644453,31.8160953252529));
#1341=CARTESIAN_POINT('',(39.7436632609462,-9.16304555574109,31.7516220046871));
#1342=CARTESIAN_POINT('',(40.3221519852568,-8.46697217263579,31.7173483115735));
#1343=CARTESIAN_POINT('',(40.9005940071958,-7.77095498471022,31.6812185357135));
#1344=B_SPLINE_CURVE_WITH_KNOTS('',3,(#1328,#1329,#1330,#1331,#1332,#1333,#1334,#1335,#1336,
#1337,#1338,#1339,#1340,#1341,#1342,#1343),.UNSPECIFIED.,.F.,.F.,(4,2,2,2,2,2,2,4),(0.,
2.71725521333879,5.43450389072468,8.15142449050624,10.8683453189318,16.3020386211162,
19.0192324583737,21.7364070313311),.UNSPECIFIED.);
#1345=EDGE_CURVE('E180',#1123,#254,#1344,.T.);
#1346=ORIENTED_EDGE('',*,*,#1345,.F.);
#1347=EDGE_LOOP('',(#1125,#1140,#1155,#1170,#1245,#1260,#1275,#1290,#1303,#1326,#1327,#1346));
#1348=FACE_BOUND('',#1347,.T.);
#1349=CARTESIAN_POINT('',(0.,0.,31.0603978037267));
#1350=DIRECTION('',(0.,0.,-1.));
#1351=DIRECTION('',(0.707106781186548,-0.707106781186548,0.));
#1352=AXIS2_PLACEMENT_3D('',#1349,#1350,#1351);
#1353=CIRCLE('',#1352,49.1642913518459);
#1354=CARTESIAN_POINT('',(34.7644038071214,-34.7644038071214,31.0603978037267));
#1355=VERTEX_POINT('',#1354);
#1356=EDGE_CURVE('E1144',#1355,#1355,#1353,.F.);
#1357=ORIENTED_EDGE('',*,*,#1356,.T.);
#1358=EDGE_LOOP('',(#1357));
#1359=FACE_BOUND('',#1358,.T.);
#1360=ADVANCED_FACE('F196',(#1112,#1348,#1359),#1101,.T.);
#1361=CARTESIAN_POINT('',(0.,0.,33.5));
#1362=DIRECTION('',(0.,0.,-1.));
#1363=DIRECTION('',(-0.707106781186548,0.707106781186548,0.));
#1364=AXIS2_PLACEMENT_3D('',#1361,#1362,#1363);
#1365=CYLINDRICAL_SURFACE('',#1364,13.5);
#1366=CARTESIAN_POINT('',(0.,0.,33.));
#1367=DIRECTION('',(0.,0.,1.));
#1368=DIRECTION('',(-0.707106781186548,0.707106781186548,0.));
#1369=AXIS2_PLACEMENT_3D('',#1366,#1367,#1368);
#1370=CIRCLE('',#1369,13.5);
#1371=CARTESIAN_POINT('',(-9.5459415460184,9.5459415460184,33.));
#1372=VERTEX_POINT('',#1371);
#1373=EDGE_CURVE('E132',#1372,#1372,#1370,.F.);
#1374=ORIENTED_EDGE('',*,*,#1373,.T.);
#1375=EDGE_LOOP('',(#1374));
#1376=FACE_BOUND('',#1375,.T.);
#1377=ORIENTED_EDGE('',*,*,#1109,.T.);
#1378=EDGE_LOOP('',(#1377));
#1379=FACE_BOUND('',#1378,.T.);
#1380=ADVANCED_FACE('F209',(#1376,#1379),#1365,.F.);
#1381=CARTESIAN_POINT('',(-2.98257317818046,0.443833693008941,50.));
#1382=DIRECTION('',(0.,0.,1.));
#1383=DIRECTION('',(0.707106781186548,-0.707106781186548,0.));
#1384=AXIS2_PLACEMENT_3D('',#1381,#1382,#1383);
#1385=CYLINDRICAL_SURFACE('',#1384,38.9999999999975);
#1386=DIRECTION('',(0.,0.,1.));
#1387=VECTOR('',#1386,1.);
#1388=CARTESIAN_POINT('',(24.5945912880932,-27.1333307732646,50.));
#1389=LINE('',#1388,#1387);
#1390=CARTESIAN_POINT('',(24.5945912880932,-27.1333307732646,20.));
#1391=VERTEX_POINT('',#1390);
#1392=EDGE_CURVE('E320',#1391,#1121,#1389,.T.);
#1393=ORIENTED_EDGE('',*,*,#1392,.T.);
#1394=ORIENTED_EDGE('',*,*,#1124,.T.);
#1395=DIRECTION('',(0.,0.,1.));
#1396=VECTOR('',#1395,1.);
#1397=CARTESIAN_POINT('',(27.0113527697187,-24.4833483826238,50.));
#1398=LINE('',#1397,#1396);
#1399=CARTESIAN_POINT('',(27.0113527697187,-24.4833483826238,20.));
#1400=VERTEX_POINT('',#1399);
#1401=EDGE_CURVE('E1012',#1400,#1123,#1398,.T.);
#1402=ORIENTED_EDGE('',*,*,#1401,.F.);
#1403=CARTESIAN_POINT('',(-2.98257317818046,0.443833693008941,20.));
#1404=DIRECTION('',(0.,0.,-1.));
#1405=DIRECTION('',(0.707106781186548,-0.707106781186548,0.));
#1406=AXIS2_PLACEMENT_3D('',#1403,#1404,#1405);
#1407=CIRCLE('',#1406,38.9999999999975);
#1408=EDGE_CURVE('E317',#1400,#1391,#1407,.T.);
#1409=ORIENTED_EDGE('',*,*,#1408,.T.);
#1410=EDGE_LOOP('',(#1393,#1394,#1402,#1409));
#1411=FACE_BOUND('',#1410,.T.);
#1412=ADVANCED_FACE('F203',(#1411),#1385,.F.);
#1413=CARTESIAN_POINT('',(43.9440537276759,-4.10887616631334,50.));
#1414=DIRECTION('',(0.769075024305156,-0.639158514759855,0.));
#1415=DIRECTION('',(-0.639158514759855,-0.769075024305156,0.));
#1416=AXIS2_PLACEMENT_3D('',#1413,#1414,#1415);
#1417=PLANE('',#1416);
#1418=ORIENTED_EDGE('',*,*,#1345,.T.);
#1419=ORIENTED_EDGE('',*,*,#255,.T.);
#1420=DIRECTION('',(0.,0.,1.));
#1421=VECTOR('',#1420,1.);
#1422=CARTESIAN_POINT('',(40.9005939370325,-7.77095506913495,50.));
#1423=LINE('',#1422,#1421);
#1424=CARTESIAN_POINT('',(40.9005939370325,-7.77095506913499,20.));
#1425=VERTEX_POINT('',#1424);
#1426=EDGE_CURVE('E316',#246,#1425,#1423,.F.);
#1427=ORIENTED_EDGE('',*,*,#1426,.T.);
#1428=DIRECTION('',(-0.639158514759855,-0.769075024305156,0.));
#1429=VECTOR('',#1428,1.);
#1430=CARTESIAN_POINT('',(43.9440537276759,-4.10887616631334,20.));
#1431=LINE('',#1430,#1429);
#1432=EDGE_CURVE('E128',#1425,#1400,#1431,.T.);
#1433=ORIENTED_EDGE('',*,*,#1432,.T.);
#1434=ORIENTED_EDGE('',*,*,#1401,.T.);
#1435=EDGE_LOOP('',(#1418,#1419,#1427,#1433,#1434));
#1436=FACE_BOUND('',#1435,.T.);
#1437=ADVANCED_FACE('F200',(#1436),#1417,.F.);
#1438=CARTESIAN_POINT('',(14.5166516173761,-11.9886472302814,50.));
#1439=DIRECTION('',(-0.639158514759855,0.769075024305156,0.));
#1440=DIRECTION('',(0.769075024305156,0.639158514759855,0.));
#1441=AXIS2_PLACEMENT_3D('',#1438,#1439,#1440);
#1442=PLANE('',#1441);
#1443=DIRECTION('',(0.769075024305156,0.639158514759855,0.));
#1444=VECTOR('',#1443,1.);
#1445=CARTESIAN_POINT('',(14.5166516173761,-11.9886472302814,20.));
#1446=LINE('',#1445,#1444);
#1447=CARTESIAN_POINT('',(14.5166516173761,-11.9886472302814,20.));
#1448=VERTEX_POINT('',#1447);
#1449=CARTESIAN_POINT('',(31.229044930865,1.90059393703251,20.));
#1450=VERTEX_POINT('',#1449);
#1451=EDGE_CURVE('E126',#1448,#1450,#1446,.T.);
#1452=ORIENTED_EDGE('',*,*,#1451,.T.);
#1453=DIRECTION('',(0.,0.,1.));
#1454=VECTOR('',#1453,1.);
#1455=CARTESIAN_POINT('',(31.229044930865,1.90059393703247,50.));
#1456=LINE('',#1455,#1454);
#1457=EDGE_CURVE('E136',#1450,#136,#1456,.T.);
#1458=ORIENTED_EDGE('',*,*,#1457,.T.);
#1459=ORIENTED_EDGE('',*,*,#404,.T.);
#1460=ORIENTED_EDGE('',*,*,#1325,.T.);
#1461=DIRECTION('',(0.,0.,1.));
#1462=VECTOR('',#1461,1.);
#1463=CARTESIAN_POINT('',(14.5166516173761,-11.9886472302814,50.));
#1464=LINE('',#1463,#1462);
#1465=EDGE_CURVE('E148',#1448,#1301,#1464,.T.);
#1466=ORIENTED_EDGE('',*,*,#1465,.F.);
#1467=EDGE_LOOP('',(#1452,#1458,#1459,#1460,#1466));
#1468=FACE_BOUND('',#1467,.T.);
#1469=ADVANCED_FACE('F147',(#1468),#1442,.F.);
#1470=CARTESIAN_POINT('',(39.4438336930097,-41.9825731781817,50.));
#1471=DIRECTION('',(0.,0.,1.));
#1472=DIRECTION('',(0.707106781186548,-0.707106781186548,0.));
#1473=AXIS2_PLACEMENT_3D('',#1470,#1471,#1472);
#1474=CYLINDRICAL_SURFACE('',#1473,38.9999999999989);
#1475=ORIENTED_EDGE('',*,*,#1465,.T.);
#1476=ORIENTED_EDGE('',*,*,#1302,.T.);
#1477=DIRECTION('',(0.,0.,1.));
#1478=VECTOR('',#1477,1.);
#1479=CARTESIAN_POINT('',(11.866669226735,-14.405408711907,50.));
#1480=LINE('',#1479,#1478);
#1481=CARTESIAN_POINT('',(11.866669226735,-14.405408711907,20.));
#1482=VERTEX_POINT('',#1481);
#1483=EDGE_CURVE('E333',#1482,#1288,#1480,.T.);
#1484=ORIENTED_EDGE('',*,*,#1483,.F.);
#1485=CARTESIAN_POINT('',(39.4438336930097,-41.9825731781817,20.));
#1486=DIRECTION('',(0.,0.,-1.));
#1487=DIRECTION('',(0.707106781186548,-0.707106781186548,0.));
#1488=AXIS2_PLACEMENT_3D('',#1485,#1486,#1487);
#1489=CIRCLE('',#1488,38.9999999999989);
#1490=EDGE_CURVE('E144',#1482,#1448,#1489,.T.);
#1491=ORIENTED_EDGE('',*,*,#1490,.T.);
#1492=EDGE_LOOP('',(#1475,#1476,#1484,#1491));
#1493=FACE_BOUND('',#1492,.T.);
#1494=ADVANCED_FACE('F296',(#1493),#1474,.F.);
#1495=CARTESIAN_POINT('',(5.83572372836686,-20.4363542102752,50.));
#1496=DIRECTION('',(-0.707106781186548,0.707106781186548,0.));
#1497=DIRECTION('',(0.707106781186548,0.707106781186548,0.));
#1498=AXIS2_PLACEMENT_3D('',#1495,#1496,#1497);
#1499=PLANE('',#1498);
#1500=ORIENTED_EDGE('',*,*,#1483,.T.);
#1501=ORIENTED_EDGE('',*,*,#1289,.T.);
#1502=DIRECTION('',(0.,0.,1.));
#1503=VECTOR('',#1502,1.);
#1504=CARTESIAN_POINT('',(5.83572372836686,-20.4363542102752,50.));
#1505=LINE('',#1504,#1503);
#1506=CARTESIAN_POINT('',(5.83572372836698,-20.4363542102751,20.));
#1507=VERTEX_POINT('',#1506);
#1508=EDGE_CURVE('E332',#1507,#1273,#1505,.T.);
#1509=ORIENTED_EDGE('',*,*,#1508,.F.);
#1510=DIRECTION('',(0.707106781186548,0.707106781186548,0.));
#1511=VECTOR('',#1510,1.);
#1512=CARTESIAN_POINT('',(5.83572372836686,-20.4363542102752,20.));
#1513=LINE('',#1512,#1511);
#1514=EDGE_CURVE('E152',#1507,#1482,#1513,.T.);
#1515=ORIENTED_EDGE('',*,*,#1514,.T.);
#1516=EDGE_LOOP('',(#1500,#1501,#1509,#1515));
#1517=FACE_BOUND('',#1516,.T.);
#1518=ADVANCED_FACE('F293',(#1517),#1499,.F.);
#1519=CARTESIAN_POINT('',(33.4128881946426,-48.0135186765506,50.));
#1520=DIRECTION('',(0.,0.,1.));
#1521=DIRECTION('',(0.707106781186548,-0.707106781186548,0.));
#1522=AXIS2_PLACEMENT_3D('',#1519,#1520,#1521);
#1523=CYLINDRICAL_SURFACE('',#1522,39.);
#1524=ORIENTED_EDGE('',*,*,#1508,.T.);
#1525=ORIENTED_EDGE('',*,*,#1274,.T.);
#1526=DIRECTION('',(0.,0.,1.));
#1527=VECTOR('',#1526,1.);
#1528=CARTESIAN_POINT('',(1.40651613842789,-25.7291710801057,50.));
#1529=LINE('',#1528,#1527);
#1530=CARTESIAN_POINT('',(1.40651613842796,-25.7291710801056,20.));
#1531=VERTEX_POINT('',#1530);
#1532=EDGE_CURVE('E329',#1531,#1258,#1529,.T.);
#1533=ORIENTED_EDGE('',*,*,#1532,.F.);
#1534=CARTESIAN_POINT('',(33.4128881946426,-48.0135186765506,20.));
#1535=DIRECTION('',(0.,0.,-1.));
#1536=DIRECTION('',(0.707106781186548,-0.707106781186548,0.));
#1537=AXIS2_PLACEMENT_3D('',#1534,#1535,#1536);
#1538=CIRCLE('',#1537,39.);
#1539=EDGE_CURVE('E330',#1531,#1507,#1538,.T.);
#1540=ORIENTED_EDGE('',*,*,#1539,.T.);
#1541=EDGE_LOOP('',(#1524,#1525,#1533,#1540));
#1542=FACE_BOUND('',#1541,.T.);
#1543=ADVANCED_FACE('F261',(#1542),#1523,.F.);
#1544=CARTESIAN_POINT('',(-5.27577561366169,-35.3267558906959,50.));
#1545=DIRECTION('',(-0.820676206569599,0.571393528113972,0.));
#1546=DIRECTION('',(0.571393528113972,0.820676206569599,0.));
#1547=AXIS2_PLACEMENT_3D('',#1544,#1545,#1546);
#1548=PLANE('',#1547);
#1549=ORIENTED_EDGE('',*,*,#1532,.T.);
#1550=ORIENTED_EDGE('',*,*,#1259,.T.);
#1551=DIRECTION('',(0.,0.,1.));
#1552=VECTOR('',#1551,1.);
#1553=CARTESIAN_POINT('',(-5.27577561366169,-35.3267558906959,50.));
#1554=LINE('',#1553,#1552);
#1555=CARTESIAN_POINT('',(-5.27577561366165,-35.3267558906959,20.));
#1556=VERTEX_POINT('',#1555);
#1557=EDGE_CURVE('E328',#1556,#1243,#1554,.T.);
#1558=ORIENTED_EDGE('',*,*,#1557,.F.);
#1559=DIRECTION('',(0.571393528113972,0.820676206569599,0.));
#1560=VECTOR('',#1559,1.);
#1561=CARTESIAN_POINT('',(-5.27577561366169,-35.3267558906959,20.));
#1562=LINE('',#1561,#1560);
#1563=EDGE_CURVE('E1128',#1556,#1531,#1562,.T.);
#1564=ORIENTED_EDGE('',*,*,#1563,.T.);
#1565=EDGE_LOOP('',(#1549,#1550,#1558,#1564));
#1566=FACE_BOUND('',#1565,.T.);
#1567=ADVANCED_FACE('F256',(#1566),#1548,.F.);
#1568=CARTESIAN_POINT('',(0.,-39.,50.));
#1569=DIRECTION('',(0.,0.,1.));
#1570=DIRECTION('',(0.707106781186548,-0.707106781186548,0.));
#1571=AXIS2_PLACEMENT_3D('',#1568,#1569,#1570);
#1572=CYLINDRICAL_SURFACE('',#1571,6.42857142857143);
#1573=ORIENTED_EDGE('',*,*,#1557,.T.);
#1574=ORIENTED_EDGE('',*,*,#1244,.T.);
#1575=DIRECTION('',(0.,0.,1.));
#1576=VECTOR('',#1575,1.);
#1577=CARTESIAN_POINT('',(3.67324410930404,-44.2757756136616,50.));
#1578=LINE('',#1577,#1576);
#1579=CARTESIAN_POINT('',(3.67324410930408,-44.2757756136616,20.));
#1580=VERTEX_POINT('',#1579);
#1581=EDGE_CURVE('E325',#1580,#1168,#1578,.T.);
#1582=ORIENTED_EDGE('',*,*,#1581,.F.);
#1583=CARTESIAN_POINT('',(0.,-39.,20.));
#1584=DIRECTION('',(0.,0.,-1.));
#1585=DIRECTION('',(0.707106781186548,-0.707106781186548,0.));
#1586=AXIS2_PLACEMENT_3D('',#1583,#1584,#1585);
#1587=CIRCLE('',#1586,6.42857142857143);
#1588=EDGE_CURVE('E326',#1580,#1556,#1587,.T.);
#1589=ORIENTED_EDGE('',*,*,#1588,.T.);
#1590=EDGE_LOOP('',(#1573,#1574,#1582,#1589));
#1591=FACE_BOUND('',#1590,.T.);
#1592=ADVANCED_FACE('F251',(#1591),#1572,.F.);
#1593=CARTESIAN_POINT('',(13.2708289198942,-37.5934838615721,50.));
#1594=DIRECTION('',(0.571393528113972,-0.820676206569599,0.));
#1595=DIRECTION('',(-0.820676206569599,-0.571393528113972,0.));
#1596=AXIS2_PLACEMENT_3D('',#1593,#1594,#1595);
#1597=PLANE('',#1596);
#1598=ORIENTED_EDGE('',*,*,#1581,.T.);
#1599=ORIENTED_EDGE('',*,*,#1169,.T.);
#1600=DIRECTION('',(0.,0.,1.));
#1601=VECTOR('',#1600,1.);
#1602=CARTESIAN_POINT('',(13.2708289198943,-37.5934838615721,50.));
#1603=LINE('',#1602,#1601);
#1604=CARTESIAN_POINT('',(13.2708289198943,-37.5934838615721,20.));
#1605=VERTEX_POINT('',#1604);
#1606=EDGE_CURVE('E324',#1605,#1153,#1603,.T.);
#1607=ORIENTED_EDGE('',*,*,#1606,.F.);
#1608=DIRECTION('',(-0.820676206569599,-0.571393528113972,0.));
#1609=VECTOR('',#1608,1.);
#1610=CARTESIAN_POINT('',(13.2708289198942,-37.5934838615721,20.));
#1611=LINE('',#1610,#1609);
#1612=EDGE_CURVE('E1127',#1605,#1580,#1611,.T.);
#1613=ORIENTED_EDGE('',*,*,#1612,.T.);
#1614=EDGE_LOOP('',(#1598,#1599,#1607,#1613));
#1615=FACE_BOUND('',#1614,.T.);
#1616=ADVANCED_FACE('F248',(#1615),#1597,.F.);
#1617=CARTESIAN_POINT('',(-9.01351867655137,-5.58711180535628,50.));
#1618=DIRECTION('',(0.,0.,1.));
#1619=DIRECTION('',(0.707106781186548,-0.707106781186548,0.));
#1620=AXIS2_PLACEMENT_3D('',#1617,#1618,#1619);
#1621=CYLINDRICAL_SURFACE('',#1620,39.0000000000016);
#1622=ORIENTED_EDGE('',*,*,#1606,.T.);
#1623=ORIENTED_EDGE('',*,*,#1154,.T.);
#1624=DIRECTION('',(0.,0.,1.));
#1625=VECTOR('',#1624,1.);
#1626=CARTESIAN_POINT('',(18.5636457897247,-33.164276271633,50.));
#1627=LINE('',#1626,#1625);
#1628=CARTESIAN_POINT('',(18.5636457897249,-33.1642762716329,20.));
#1629=VERTEX_POINT('',#1628);
#1630=EDGE_CURVE('E321',#1629,#1138,#1627,.T.);
#1631=ORIENTED_EDGE('',*,*,#1630,.F.);
#1632=CARTESIAN_POINT('',(-9.01351867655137,-5.58711180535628,20.));
#1633=DIRECTION('',(0.,0.,-1.));
#1634=DIRECTION('',(0.707106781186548,-0.707106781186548,0.));
#1635=AXIS2_PLACEMENT_3D('',#1632,#1633,#1634);
#1636=CIRCLE('',#1635,39.0000000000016);
#1637=EDGE_CURVE('E322',#1629,#1605,#1636,.T.);
#1638=ORIENTED_EDGE('',*,*,#1637,.T.);
#1639=EDGE_LOOP('',(#1622,#1623,#1631,#1638));
#1640=FACE_BOUND('',#1639,.T.);
#1641=ADVANCED_FACE('F216',(#1640),#1621,.F.);
#1642=CARTESIAN_POINT('',(24.5945912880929,-27.1333307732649,50.));
#1643=DIRECTION('',(0.707106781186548,-0.707106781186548,0.));
#1644=DIRECTION('',(-0.707106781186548,-0.707106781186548,0.));
#1645=AXIS2_PLACEMENT_3D('',#1642,#1643,#1644);
#1646=PLANE('',#1645);
#1647=ORIENTED_EDGE('',*,*,#1630,.T.);
#1648=ORIENTED_EDGE('',*,*,#1139,.T.);
#1649=ORIENTED_EDGE('',*,*,#1392,.F.);
#1650=DIRECTION('',(-0.707106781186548,-0.707106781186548,0.));
#1651=VECTOR('',#1650,1.);
#1652=CARTESIAN_POINT('',(24.5945912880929,-27.1333307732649,20.));
#1653=LINE('',#1652,#1651);
#1654=EDGE_CURVE('E1125',#1391,#1629,#1653,.T.);
#1655=ORIENTED_EDGE('',*,*,#1654,.T.);
#1656=EDGE_LOOP('',(#1647,#1648,#1649,#1655));
#1657=FACE_BOUND('',#1656,.T.);
#1658=ADVANCED_FACE('F211',(#1657),#1646,.F.);
#1659=CARTESIAN_POINT('',(0.,0.,29.0671571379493));
#1660=DIRECTION('',(0.,0.,1.));
#1661=DIRECTION('',(0.707106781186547,-0.707106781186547,0.));
#1662=AXIS2_PLACEMENT_3D('',#1659,#1660,#1661);
#1663=TOROIDAL_SURFACE('',#1662,49.,2.);
#1664=CARTESIAN_POINT('',(0.,0.,29.0671571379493));
#1665=DIRECTION('',(0.,0.,1.));
#1666=DIRECTION('',(-0.707106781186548,0.707106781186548,0.));
#1667=AXIS2_PLACEMENT_3D('',#1664,#1665,#1666);
#1668=CIRCLE('',#1667,51.);
#1669=CARTESIAN_POINT('',(-36.062445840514,36.062445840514,29.0671571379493));
#1670=VERTEX_POINT('',#1669);
#1671=EDGE_CURVE('E179',#1670,#1670,#1668,.T.);
#1672=ORIENTED_EDGE('',*,*,#1671,.T.);
#1673=EDGE_LOOP('',(#1672));
#1674=FACE_BOUND('',#1673,.T.);
#1675=ORIENTED_EDGE('',*,*,#1356,.F.);
#1676=EDGE_LOOP('',(#1675));
#1677=FACE_BOUND('',#1676,.T.);
#1678=ADVANCED_FACE('F215',(#1674,#1677),#1663,.T.);
#1679=ORIENTED_EDGE('',*,*,#480,.F.);
#1680=ORIENTED_EDGE('',*,*,#512,.T.);
#1681=ORIENTED_EDGE('',*,*,#566,.F.);
#1682=ORIENTED_EDGE('',*,*,#744,.F.);
#1683=ORIENTED_EDGE('',*,*,#768,.F.);
#1684=ORIENTED_EDGE('',*,*,#96,.T.);
#1685=EDGE_LOOP('',(#1679,#1680,#1681,#1682,#1683,#1684));
#1686=FACE_BOUND('',#1685,.T.);
#1687=CARTESIAN_POINT('',(39.,0.,20.));
#1688=DIRECTION('',(0.,0.,1.));
#1689=DIRECTION('',(-0.707106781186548,0.707106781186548,0.));
#1690=AXIS2_PLACEMENT_3D('',#1687,#1688,#1689);
#1691=CIRCLE('',#1690,8.);
#1692=EDGE_CURVE('E121',#1450,#1425,#1691,.F.);
#1693=ORIENTED_EDGE('',*,*,#1692,.F.);
#1694=ORIENTED_EDGE('',*,*,#1451,.F.);
#1695=ORIENTED_EDGE('',*,*,#1490,.F.);
#1696=ORIENTED_EDGE('',*,*,#1514,.F.);
#1697=ORIENTED_EDGE('',*,*,#1539,.F.);
#1698=ORIENTED_EDGE('',*,*,#1563,.F.);
#1699=ORIENTED_EDGE('',*,*,#1588,.F.);
#1700=ORIENTED_EDGE('',*,*,#1612,.F.);
#1701=ORIENTED_EDGE('',*,*,#1637,.F.);
#1702=ORIENTED_EDGE('',*,*,#1654,.F.);
#1703=ORIENTED_EDGE('',*,*,#1408,.F.);
#1704=ORIENTED_EDGE('',*,*,#1432,.F.);
#1705=EDGE_LOOP('',(#1693,#1694,#1695,#1696,#1697,#1698,#1699,#1700,#1701,#1702,#1703,#1704));
#1706=FACE_BOUND('',#1705,.T.);
#1707=ADVANCED_FACE('F123',(#1686,#1706),#1092,.T.);
#1708=CARTESIAN_POINT('',(39.,0.,20.));
#1709=DIRECTION('',(0.,0.,-1.));
#1710=DIRECTION('',(-0.707106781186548,0.707106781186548,0.));
#1711=AXIS2_PLACEMENT_3D('',#1708,#1709,#1710);
#1712=CYLINDRICAL_SURFACE('',#1711,8.);
#1713=ORIENTED_EDGE('',*,*,#1457,.F.);
#1714=ORIENTED_EDGE('',*,*,#1692,.T.);
#1715=ORIENTED_EDGE('',*,*,#1426,.F.);
#1716=ORIENTED_EDGE('',*,*,#441,.F.);
#1717=ORIENTED_EDGE('',*,*,#457,.F.);
#1718=ORIENTED_EDGE('',*,*,#118,.F.);
#1719=ORIENTED_EDGE('',*,*,#761,.F.);
#1720=ORIENTED_EDGE('',*,*,#423,.F.);
#1721=EDGE_LOOP('',(#1713,#1714,#1715,#1716,#1717,#1718,#1719,#1720));
#1722=FACE_BOUND('',#1721,.T.);
#1723=ADVANCED_FACE('F137',(#1722),#1712,.F.);
#1724=CARTESIAN_POINT('',(-4.7729707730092,-4.7729707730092,33.));
#1725=DIRECTION('',(0.,0.,1.));
#1726=DIRECTION('',(0.707106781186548,-0.707106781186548,0.));
#1727=AXIS2_PLACEMENT_3D('',#1724,#1725,#1726);
#1728=PLANE('',#1727);
#1729=ORIENTED_EDGE('',*,*,#1373,.F.);
#1730=EDGE_LOOP('',(#1729));
#1731=FACE_BOUND('',#1730,.T.);
#1732=ADVANCED_FACE('F839',(#1731),#1728,.T.);
#1733=CARTESIAN_POINT('',(0.,0.,20.1585785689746));
#1734=DIRECTION('',(0.,0.,-1.));
#1735=DIRECTION('',(-0.707106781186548,0.707106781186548,0.));
#1736=AXIS2_PLACEMENT_3D('',#1733,#1734,#1735);
#1737=CYLINDRICAL_SURFACE('',#1736,51.);
#1738=CARTESIAN_POINT('',(0.,0.,11.25));
#1739=DIRECTION('',(0.,0.,-1.));
#1740=DIRECTION('',(0.707106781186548,-0.707106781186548,0.));
#1741=AXIS2_PLACEMENT_3D('',#1738,#1739,#1740);
#1742=CIRCLE('',#1741,51.);
#1743=CARTESIAN_POINT('',(36.062445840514,-36.062445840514,11.25));
#1744=VERTEX_POINT('',#1743);
#1745=EDGE_CURVE('E175',#1744,#1744,#1742,.F.);
#1746=ORIENTED_EDGE('',*,*,#1745,.T.);
#1747=EDGE_LOOP('',(#1746));
#1748=FACE_BOUND('',#1747,.T.);
#1749=ORIENTED_EDGE('',*,*,#1671,.F.);
#1750=EDGE_LOOP('',(#1749));
#1751=FACE_BOUND('',#1750,.T.);
#1752=ADVANCED_FACE('F366',(#1748,#1751),#1737,.T.);
#1753=CARTESIAN_POINT('',(0.,0.,11.25));
#1754=DIRECTION('',(0.,0.,1.));
#1755=DIRECTION('',(0.707106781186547,-0.707106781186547,0.));
#1756=AXIS2_PLACEMENT_3D('',#1753,#1754,#1755);
#1757=TOROIDAL_SURFACE('',#1756,49.75,1.25);
#1758=ORIENTED_EDGE('',*,*,#1745,.F.);
#1759=EDGE_LOOP('',(#1758));
#1760=FACE_BOUND('',#1759,.T.);
#1761=CARTESIAN_POINT('',(0.,0.,10.));
#1762=DIRECTION('',(0.,0.,1.));
#1763=DIRECTION('',(0.707106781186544,-0.707106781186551,0.));
#1764=AXIS2_PLACEMENT_3D('',#1761,#1762,#1763);
#1765=CIRCLE('',#1764,49.75);
#1766=CARTESIAN_POINT('',(35.1785623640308,-35.1785623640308,10.));
#1767=VERTEX_POINT('',#1766);
#1768=CARTESIAN_POINT('',(-35.1785623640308,35.1785623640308,10.));
#1769=VERTEX_POINT('',#1768);
#1770=EDGE_CURVE('E170',#1767,#1769,#1765,.T.);
#1771=ORIENTED_EDGE('',*,*,#1770,.T.);
#1772=CARTESIAN_POINT('',(0.,0.,10.));
#1773=DIRECTION('',(0.,0.,1.));
#1774=DIRECTION('',(-0.707106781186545,0.70710678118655,0.));
#1775=AXIS2_PLACEMENT_3D('',#1772,#1773,#1774);
#1776=CIRCLE('',#1775,49.75);
#1777=CARTESIAN_POINT('',(-35.1785623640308,-35.1785623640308,10.));
#1778=VERTEX_POINT('',#1777);
#1779=EDGE_CURVE('E174',#1769,#1778,#1776,.T.);
#1780=ORIENTED_EDGE('',*,*,#1779,.T.);
#1781=CARTESIAN_POINT('',(0.,0.,10.));
#1782=DIRECTION('',(0.,0.,1.));
#1783=DIRECTION('',(-0.707106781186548,-0.707106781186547,0.));
#1784=AXIS2_PLACEMENT_3D('',#1781,#1782,#1783);
#1785=CIRCLE('',#1784,49.75);
#1786=EDGE_CURVE('E347',#1778,#1767,#1785,.T.);
#1787=ORIENTED_EDGE('',*,*,#1786,.T.);
#1788=EDGE_LOOP('',(#1771,#1780,#1787));
#1789=FACE_BOUND('',#1788,.T.);
#1790=ADVANCED_FACE('F354',(#1760,#1789),#1757,.T.);
#1791=CARTESIAN_POINT('',(-34.1780062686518,-34.1780062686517,10.));
#1792=DIRECTION('',(0.,0.,-1.));
#1793=DIRECTION('',(-0.707106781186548,-0.707106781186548,0.));
#1794=AXIS2_PLACEMENT_3D('',#1791,#1792,#1793);
#1795=PLANE('',#1794);
#1796=CARTESIAN_POINT('',(0.,0.,10.));
#1797=DIRECTION('',(0.,0.,1.));
#1798=DIRECTION('',(-0.707106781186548,0.707106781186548,0.));
#1799=AXIS2_PLACEMENT_3D('',#1796,#1797,#1798);
#1800=CIRCLE('',#1799,46.92);
#1801=CARTESIAN_POINT('',(-33.1774501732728,33.1774501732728,10.));
#1802=VERTEX_POINT('',#1801);
#1803=EDGE_CURVE('E164',#1802,#1802,#1800,.F.);
#1804=ORIENTED_EDGE('',*,*,#1803,.F.);
#1805=EDGE_LOOP('',(#1804));
#1806=FACE_BOUND('',#1805,.T.);
#1807=ORIENTED_EDGE('',*,*,#1786,.F.);
#1808=ORIENTED_EDGE('',*,*,#1779,.F.);
#1809=ORIENTED_EDGE('',*,*,#1770,.F.);
#1810=EDGE_LOOP('',(#1807,#1808,#1809));
#1811=FACE_BOUND('',#1810,.T.);
#1812=ADVANCED_FACE('F365',(#1806,#1811),#1795,.T.);
#1813=CARTESIAN_POINT('',(0.,0.,11.0005));
#1814=DIRECTION('',(0.,0.,-1.));
#1815=DIRECTION('',(-0.707106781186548,0.707106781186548,0.));
#1816=AXIS2_PLACEMENT_3D('',#1813,#1814,#1815);
#1817=CYLINDRICAL_SURFACE('',#1816,46.92);
#1818=ORIENTED_EDGE('',*,*,#1803,.T.);
#1819=EDGE_LOOP('',(#1818));
#1820=FACE_BOUND('',#1819,.T.);
#1821=CARTESIAN_POINT('',(0.,0.,12.001));
#1822=DIRECTION('',(0.,0.,1.));
#1823=DIRECTION('',(-0.707106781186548,0.707106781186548,0.));
#1824=AXIS2_PLACEMENT_3D('',#1821,#1822,#1823);
#1825=CIRCLE('',#1824,46.92);
#1826=CARTESIAN_POINT('',(-33.1774501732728,33.1774501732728,12.001));
#1827=VERTEX_POINT('',#1826);
#1828=EDGE_CURVE('E158',#1827,#1827,#1825,.T.);
#1829=ORIENTED_EDGE('',*,*,#1828,.T.);
#1830=EDGE_LOOP('',(#1829));
#1831=FACE_BOUND('',#1830,.T.);
#1832=ADVANCED_FACE('F452',(#1820,#1831),#1817,.F.);
#1833=CARTESIAN_POINT('',(-21.8920259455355,-21.8920259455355,12.001));
#1834=DIRECTION('',(0.,0.,-1.));
#1835=DIRECTION('',(-0.707106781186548,0.707106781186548,0.));
#1836=AXIS2_PLACEMENT_3D('',#1833,#1834,#1835);
#1837=PLANE('',#1836);
#1838=CARTESIAN_POINT('',(0.,0.,12.001));
#1839=DIRECTION('',(0.,0.,1.));
#1840=DIRECTION('',(-0.707106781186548,0.707106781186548,0.));
#1841=AXIS2_PLACEMENT_3D('',#1838,#1839,#1840);
#1842=CIRCLE('',#1841,15.);
#1843=CARTESIAN_POINT('',(-10.6066017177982,10.6066017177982,12.001));
#1844=VERTEX_POINT('',#1843);
#1845=EDGE_CURVE('E154',#1844,#1844,#1842,.F.);
#1846=ORIENTED_EDGE('',*,*,#1845,.F.);
#1847=EDGE_LOOP('',(#1846));
#1848=FACE_BOUND('',#1847,.T.);
#1849=ORIENTED_EDGE('',*,*,#1828,.F.);
#1850=EDGE_LOOP('',(#1849));
#1851=FACE_BOUND('',#1850,.T.);
#1852=ADVANCED_FACE('F448',(#1848,#1851),#1837,.T.);
#1853=CARTESIAN_POINT('',(0.,0.,6.1005));
#1854=DIRECTION('',(0.,0.,-1.));
#1855=DIRECTION('',(-0.707106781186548,0.707106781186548,0.));
#1856=AXIS2_PLACEMENT_3D('',#1853,#1854,#1855);
#1857=CYLINDRICAL_SURFACE('',#1856,15.);
#1858=ORIENTED_EDGE('',*,*,#1845,.T.);
#1859=EDGE_LOOP('',(#1858));
#1860=FACE_BOUND('',#1859,.T.);
#1861=CARTESIAN_POINT('',(0.,0.,0.200000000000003));
#1862=DIRECTION('',(0.,0.,1.));
#1863=DIRECTION('',(-0.707106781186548,0.707106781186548,0.));
#1864=AXIS2_PLACEMENT_3D('',#1861,#1862,#1863);
#1865=CIRCLE('',#1864,15.);
#1866=CARTESIAN_POINT('',(-10.6066017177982,10.6066017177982,0.200000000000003));
#1867=VERTEX_POINT('',#1866);
#1868=EDGE_CURVE('E161',#1867,#1867,#1865,.F.);
#1869=ORIENTED_EDGE('',*,*,#1868,.F.);
#1870=EDGE_LOOP('',(#1869));
#1871=FACE_BOUND('',#1870,.T.);
#1872=ADVANCED_FACE('F451',(#1860,#1871),#1857,.T.);
#1873=CARTESIAN_POINT('',(-9.19238815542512,-9.19238815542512,0.2));
#1874=DIRECTION('',(0.,0.,-1.));
#1875=DIRECTION('',(-0.707106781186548,-0.707106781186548,0.));
#1876=AXIS2_PLACEMENT_3D('',#1873,#1874,#1875);
#1877=PLANE('',#1876);
#1878=CARTESIAN_POINT('',(0.,0.,0.2));
#1879=DIRECTION('',(0.,0.,1.));
#1880=DIRECTION('',(-0.707106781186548,0.707106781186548,0.));
#1881=AXIS2_PLACEMENT_3D('',#1878,#1879,#1880);
#1882=CIRCLE('',#1881,11.);
#1883=CARTESIAN_POINT('',(-7.77817459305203,7.77817459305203,0.2));
#1884=VERTEX_POINT('',#1883);
#1885=EDGE_CURVE('E167',#1884,#1884,#1882,.F.);
#1886=ORIENTED_EDGE('',*,*,#1885,.F.);
#1887=EDGE_LOOP('',(#1886));
#1888=FACE_BOUND('',#1887,.T.);
#1889=ORIENTED_EDGE('',*,*,#1868,.T.);
#1890=EDGE_LOOP('',(#1889));
#1891=FACE_BOUND('',#1890,.T.);
#1892=ADVANCED_FACE('F456',(#1888,#1891),#1877,.T.);
#1893=CARTESIAN_POINT('',(0.,0.,0.1));
#1894=DIRECTION('',(0.,0.,-1.));
#1895=DIRECTION('',(-0.707106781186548,0.707106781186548,0.));
#1896=AXIS2_PLACEMENT_3D('',#1893,#1894,#1895);
#1897=CYLINDRICAL_SURFACE('',#1896,11.);
#1898=ORIENTED_EDGE('',*,*,#1885,.T.);
#1899=EDGE_LOOP('',(#1898));
#1900=FACE_BOUND('',#1899,.T.);
#1901=CARTESIAN_POINT('',(0.,0.,0.));
#1902=DIRECTION('',(0.,0.,1.));
#1903=DIRECTION('',(-0.707106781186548,0.707106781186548,0.));
#1904=AXIS2_PLACEMENT_3D('',#1901,#1902,#1903);
#1905=CIRCLE('',#1904,11.);
#1906=CARTESIAN_POINT('',(-7.77817459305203,7.77817459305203,0.));
#1907=VERTEX_POINT('',#1906);
#1908=EDGE_CURVE('E171',#1907,#1907,#1905,.F.);
#1909=ORIENTED_EDGE('',*,*,#1908,.F.);
#1910=EDGE_LOOP('',(#1909));
#1911=FACE_BOUND('',#1910,.T.);
#1912=ADVANCED_FACE('F368',(#1900,#1911),#1897,.T.);
#1913=CARTESIAN_POINT('',(-5.77470537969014,-5.77470537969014,0.));
#1914=DIRECTION('',(0.,0.,-1.));
#1915=DIRECTION('',(-0.707106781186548,0.707106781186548,0.));
#1916=AXIS2_PLACEMENT_3D('',#1913,#1914,#1915);
#1917=PLANE('',#1916);
#1918=CARTESIAN_POINT('',(0.,0.,-5.6843418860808E-11));
#1919=DIRECTION('',(0.,0.,1.));
#1920=DIRECTION('',(-0.707106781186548,0.707106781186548,0.));
#1921=AXIS2_PLACEMENT_3D('',#1918,#1919,#1920);
#1922=CIRCLE('',#1921,5.3333333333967);
#1923=CARTESIAN_POINT('',(-3.77123616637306,3.77123616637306,-5.6843418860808E-11));
#1924=VERTEX_POINT('',#1923);
#1925=EDGE_CURVE('E176',#1924,#1924,#1922,.F.);
#1926=ORIENTED_EDGE('',*,*,#1925,.F.);
#1927=EDGE_LOOP('',(#1926));
#1928=FACE_BOUND('',#1927,.T.);
#1929=ORIENTED_EDGE('',*,*,#1908,.T.);
#1930=EDGE_LOOP('',(#1929));
#1931=FACE_BOUND('',#1930,.T.);
#1932=ADVANCED_FACE('F370',(#1928,#1931),#1917,.T.);
#1933=CARTESIAN_POINT('',(0.,0.,5.6843418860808E-11));
#1934=DIRECTION('',(0.,0.,-1.));
#1935=DIRECTION('',(-0.707106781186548,0.707106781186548,0.));
#1936=AXIS2_PLACEMENT_3D('',#1933,#1934,#1935);
#1937=CONICAL_SURFACE('',#1936,5.33333333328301,0.785398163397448);
#1938=ORIENTED_EDGE('',*,*,#1925,.T.);
#1939=EDGE_LOOP('',(#1938));
#1940=FACE_BOUND('',#1939,.T.);
#1941=CARTESIAN_POINT('',(0.,0.,0.333333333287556));
#1942=DIRECTION('',(0.,0.,1.));
#1943=DIRECTION('',(-0.707106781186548,-0.707106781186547,0.));
#1944=AXIS2_PLACEMENT_3D('',#1941,#1942,#1943);
#1945=CIRCLE('',#1944,4.99999999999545);
#1946=CARTESIAN_POINT('',(-3.53553390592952,-3.53553390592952,0.333333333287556));
#1947=VERTEX_POINT('',#1946);
#1948=EDGE_CURVE('E1146',#1947,#1947,#1945,.T.);
#1949=ORIENTED_EDGE('',*,*,#1948,.T.);
#1950=EDGE_LOOP('',(#1949));
#1951=FACE_BOUND('',#1950,.T.);
#1952=ADVANCED_FACE('F398',(#1940,#1951),#1937,.F.);
#1953=CARTESIAN_POINT('',(0.,0.,11.));
#1954=DIRECTION('',(0.,0.,-1.));
#1955=DIRECTION('',(-0.707106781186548,0.707106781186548,0.));
#1956=AXIS2_PLACEMENT_3D('',#1953,#1954,#1955);
#1957=CYLINDRICAL_SURFACE('',#1956,5.);
#1958=ORIENTED_EDGE('',*,*,#1948,.F.);
#1959=EDGE_LOOP('',(#1958));
#1960=FACE_BOUND('',#1959,.T.);
#1961=CARTESIAN_POINT('',(0.,0.,21.6666666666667));
#1962=DIRECTION('',(0.,0.,1.));
#1963=DIRECTION('',(-0.707106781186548,0.707106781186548,0.));
#1964=AXIS2_PLACEMENT_3D('',#1961,#1962,#1963);
#1965=CIRCLE('',#1964,5.);
#1966=CARTESIAN_POINT('',(-3.53553390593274,3.53553390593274,21.6666666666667));
#1967=VERTEX_POINT('',#1966);
#1968=EDGE_CURVE('E188',#1967,#1967,#1965,.T.);
#1969=ORIENTED_EDGE('',*,*,#1968,.T.);
#1970=EDGE_LOOP('',(#1969));
#1971=FACE_BOUND('',#1970,.T.);
#1972=ADVANCED_FACE('F399',(#1960,#1971),#1957,.F.);
#1973=CARTESIAN_POINT('',(0.,0.,21.9999999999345));
#1974=DIRECTION('',(0.,0.,1.));
#1975=DIRECTION('',(0.707106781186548,-0.707106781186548,0.));
#1976=AXIS2_PLACEMENT_3D('',#1973,#1974,#1975);
#1977=CONICAL_SURFACE('',#1976,5.33333333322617,0.785398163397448);
#1978=ORIENTED_EDGE('',*,*,#1968,.F.);
#1979=EDGE_LOOP('',(#1978));
#1980=FACE_BOUND('',#1979,.T.);
#1981=CARTESIAN_POINT('',(0.,0.,21.9999999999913));
#1982=DIRECTION('',(0.,0.,-1.));
#1983=DIRECTION('',(0.707106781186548,-0.707106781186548,0.));
#1984=AXIS2_PLACEMENT_3D('',#1981,#1982,#1983);
#1985=CIRCLE('',#1984,5.33333333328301);
#1986=CARTESIAN_POINT('',(3.77123616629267,-3.77123616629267,21.9999999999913));
#1987=VERTEX_POINT('',#1986);
#1988=EDGE_CURVE('E313',#1987,#1987,#1985,.F.);
#1989=ORIENTED_EDGE('',*,*,#1988,.T.);
#1990=EDGE_LOOP('',(#1989));
#1991=FACE_BOUND('',#1990,.T.);
#1992=ADVANCED_FACE('F205',(#1980,#1991),#1977,.F.);
#1993=CARTESIAN_POINT('',(-5.42115198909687,-5.42115198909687,22.));
#1994=DIRECTION('',(0.,0.,1.));
#1995=DIRECTION('',(0.707106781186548,-0.707106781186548,0.));
#1996=AXIS2_PLACEMENT_3D('',#1993,#1994,#1995);
#1997=PLANE('',#1996);
#1998=CARTESIAN_POINT('',(0.,0.,22.));
#1999=DIRECTION('',(0.,0.,1.));
#2000=DIRECTION('',(-0.707106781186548,0.707106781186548,0.));
#2001=AXIS2_PLACEMENT_3D('',#1998,#1999,#2000);
#2002=CIRCLE('',#2001,10.);
#2003=CARTESIAN_POINT('',(-7.07106781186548,7.07106781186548,22.));
#2004=VERTEX_POINT('',#2003);
#2005=EDGE_CURVE('E337',#2004,#2004,#2002,.F.);
#2006=ORIENTED_EDGE('',*,*,#2005,.F.);
#2007=EDGE_LOOP('',(#2006));
#2008=FACE_BOUND('',#2007,.T.);
#2009=ORIENTED_EDGE('',*,*,#1988,.F.);
#2010=EDGE_LOOP('',(#2009));
#2011=FACE_BOUND('',#2010,.T.);
#2012=ADVANCED_FACE('F408',(#2008,#2011),#1997,.T.);
#2013=CARTESIAN_POINT('',(0.,0.,23.1));
#2014=DIRECTION('',(0.,0.,-1.));
#2015=DIRECTION('',(-0.707106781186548,0.707106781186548,0.));
#2016=AXIS2_PLACEMENT_3D('',#2013,#2014,#2015);
#2017=CYLINDRICAL_SURFACE('',#2016,10.);
#2018=ORIENTED_EDGE('',*,*,#2005,.T.);
#2019=EDGE_LOOP('',(#2018));
#2020=FACE_BOUND('',#2019,.T.);
#2021=CARTESIAN_POINT('',(0.,0.,24.2));
#2022=DIRECTION('',(0.,0.,1.));
#2023=DIRECTION('',(-0.707106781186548,0.707106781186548,0.));
#2024=AXIS2_PLACEMENT_3D('',#2021,#2022,#2023);
#2025=CIRCLE('',#2024,10.);
#2026=CARTESIAN_POINT('',(-7.07106781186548,7.07106781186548,24.2));
#2027=VERTEX_POINT('',#2026);
#2028=EDGE_CURVE('E340',#2027,#2027,#2025,.T.);
#2029=ORIENTED_EDGE('',*,*,#2028,.T.);
#2030=EDGE_LOOP('',(#2029));
#2031=FACE_BOUND('',#2030,.T.);
#2032=ADVANCED_FACE('F1165',(#2020,#2031),#2017,.F.);
#2033=CARTESIAN_POINT('',(-3.53553390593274,-3.53553390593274,24.2));
#2034=DIRECTION('',(0.,0.,-1.));
#2035=DIRECTION('',(-0.707106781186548,0.707106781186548,0.));
#2036=AXIS2_PLACEMENT_3D('',#2033,#2034,#2035);
#2037=PLANE('',#2036);
#2038=ORIENTED_EDGE('',*,*,#2028,.F.);
#2039=EDGE_LOOP('',(#2038));
#2040=FACE_BOUND('',#2039,.T.);
#2041=ADVANCED_FACE('F18',(#2040),#2037,.T.);
#2042=CLOSED_SHELL('',(#46,#66,#122,#408,#427,#446,#484,#516,#586,#642,#692,#718,#750,#774,#834,
#889,#944,#964,#989,#1014,#1031,#1043,#1061,#1075,#1087,#1096,#1360,#1380,#1412,#1437,#1469,
#1494,#1518,#1543,#1567,#1592,#1616,#1641,#1658,#1678,#1707,#1723,#1732,#1752,#1790,#1812,#1832,
#1852,#1872,#1892,#1912,#1932,#1952,#1972,#1992,#2012,#2032,#2041));
#2043=CARTESIAN_POINT('',(50.3137084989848,-11.3137084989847,28.));
#2044=DIRECTION('',(0.707106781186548,-0.707106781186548,0.));
#2045=DIRECTION('',(-0.707106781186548,-0.707106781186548,0.));
#2046=AXIS2_PLACEMENT_3D('',#2043,#2044,#2045);
#2047=CYLINDRICAL_SURFACE('',#2046,1.49);
#2048=CARTESIAN_POINT('',(33.6896280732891,5.31037192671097,28.));
#2049=DIRECTION('',(-0.707106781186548,0.707106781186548,0.));
#2050=DIRECTION('',(-0.707106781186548,-0.707106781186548,0.));
#2051=AXIS2_PLACEMENT_3D('',#2048,#2049,#2050);
#2052=CIRCLE('',#2051,1.49);
#2053=CARTESIAN_POINT('',(32.6360389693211,4.25678282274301,28.));
#2054=VERTEX_POINT('',#2053);
#2055=EDGE_CURVE('E597',#2054,#2054,#2052,.F.);
#2056=ORIENTED_EDGE('',*,*,#2055,.T.);
#2057=EDGE_LOOP('',(#2056));
#2058=FACE_BOUND('',#2057,.T.);
#2059=CARTESIAN_POINT('',(32.388538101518,4.50428369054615,28.));
#2060=CARTESIAN_POINT('',(32.3885395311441,4.50428779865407,28.0828272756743));
#2061=CARTESIAN_POINT('',(32.3925059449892,4.51012487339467,28.1657587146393));
#2062=CARTESIAN_POINT('',(32.4083448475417,4.5332406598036,28.3293484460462));
#2063=CARTESIAN_POINT('',(32.4202331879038,4.55054231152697,28.4100018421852));
#2064=CARTESIAN_POINT('',(32.4517710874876,4.59580823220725,28.5665486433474));
#2065=CARTESIAN_POINT('',(32.4714100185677,4.6237578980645,28.6424484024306));
#2066=CARTESIAN_POINT('',(32.5182148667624,4.68914387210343,28.7874975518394));
#2067=CARTESIAN_POINT('',(32.5453781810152,4.72657689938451,28.8566492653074));
#2068=CARTESIAN_POINT('',(32.6072515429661,4.80993594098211,28.9871273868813));
#2069=CARTESIAN_POINT('',(32.6420420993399,4.85595171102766,29.0483582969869));
#2070=CARTESIAN_POINT('',(32.7185139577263,4.95447421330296,29.160426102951));
#2071=CARTESIAN_POINT('',(32.7601960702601,5.00698170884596,29.2112617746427));
#2072=CARTESIAN_POINT('',(32.8501117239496,5.11702575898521,29.3014532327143));
#2073=CARTESIAN_POINT('',(32.8983920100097,5.17459704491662,29.3407201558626));
#2074=CARTESIAN_POINT('',(33.0003023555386,5.29241790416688,29.4060865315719));
#2075=CARTESIAN_POINT('',(33.053931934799,5.35266723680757,29.4321871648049));
#2076=CARTESIAN_POINT('',(33.1646373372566,5.47313023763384,29.4701883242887));
#2077=CARTESIAN_POINT('',(33.2216665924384,5.53333639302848,29.4822482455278));
#2078=CARTESIAN_POINT('',(33.3381966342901,5.65251496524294,29.4923222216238));
#2079=CARTESIAN_POINT('',(33.397697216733,5.71148748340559,29.4903374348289));
#2080=CARTESIAN_POINT('',(33.5166699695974,5.82578888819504,29.4725007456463));
#2081=CARTESIAN_POINT('',(33.5761333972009,5.88115380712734,29.4568205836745));
#2082=CARTESIAN_POINT('',(33.6939230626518,5.9876419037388,29.4123095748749));
#2083=CARTESIAN_POINT('',(33.7522492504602,6.03876489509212,29.3834781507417));
#2084=CARTESIAN_POINT('',(33.866197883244,6.13593675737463,29.3133178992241));
#2085=CARTESIAN_POINT('',(33.9218033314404,6.1819555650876,29.2719198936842));
#2086=CARTESIAN_POINT('',(34.0280769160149,6.26774696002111,29.177855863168));
#2087=CARTESIAN_POINT('',(34.0787449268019,6.30751938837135,29.1251895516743));
#2088=CARTESIAN_POINT('',(34.1740690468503,6.38075730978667,29.0091474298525));
#2089=CARTESIAN_POINT('',(34.2186239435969,6.41411961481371,28.9456232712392));
#2090=CARTESIAN_POINT('',(34.2991212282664,6.47334884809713,28.8101272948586));
#2091=CARTESIAN_POINT('',(34.3350597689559,6.49921242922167,28.7381517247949));
#2092=CARTESIAN_POINT('',(34.3969053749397,6.54316196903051,28.5875860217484));
#2093=CARTESIAN_POINT('',(34.4227876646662,6.56122873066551,28.5089801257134));
#2094=CARTESIAN_POINT('',(34.4632178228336,6.58925049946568,28.3476386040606));
#2095=CARTESIAN_POINT('',(34.4777896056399,6.59922262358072,28.2649120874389));
#2096=CARTESIAN_POINT('',(34.489501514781,6.60722417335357,28.1513071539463));
#2097=CARTESIAN_POINT('',(34.4918295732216,6.60881252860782,28.1211185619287));
#2098=CARTESIAN_POINT('',(34.4949377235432,6.61093165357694,28.0606246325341));
#2099=CARTESIAN_POINT('',(34.4957178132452,6.61146242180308,28.0303192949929));
#2100=CARTESIAN_POINT('',(34.4957122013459,6.611460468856,27.9171727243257));
#2101=CARTESIAN_POINT('',(34.4898751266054,6.60749405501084,27.8342412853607));
#2102=CARTESIAN_POINT('',(34.4667593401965,6.59165515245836,27.6706515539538));
#2103=CARTESIAN_POINT('',(34.4494576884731,6.57976681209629,27.5899981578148));
#2104=CARTESIAN_POINT('',(34.4041917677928,6.54822891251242,27.4334513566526));
#2105=CARTESIAN_POINT('',(34.3762421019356,6.5285899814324,27.3575515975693));
#2106=CARTESIAN_POINT('',(34.3108561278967,6.48178513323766,27.2125024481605));
#2107=CARTESIAN_POINT('',(34.2734231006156,6.45462181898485,27.1433507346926));
#2108=CARTESIAN_POINT('',(34.190064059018,6.39274845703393,27.0128726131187));
#2109=CARTESIAN_POINT('',(34.1440482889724,6.3579579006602,26.951641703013));
#2110=CARTESIAN_POINT('',(34.0455257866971,6.28148604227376,26.839573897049));
#2111=CARTESIAN_POINT('',(33.9930182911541,6.23980392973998,26.7887382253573));
#2112=CARTESIAN_POINT('',(33.8829742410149,6.14988827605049,26.6985467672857));
#2113=CARTESIAN_POINT('',(33.8254029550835,6.10160798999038,26.6592798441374));
#2114=CARTESIAN_POINT('',(33.7075820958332,5.99969764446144,26.5939134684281));
#2115=CARTESIAN_POINT('',(33.6473327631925,5.94606806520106,26.5678128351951));
#2116=CARTESIAN_POINT('',(33.5268697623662,5.83536266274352,26.5298116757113));
#2117=CARTESIAN_POINT('',(33.4666636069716,5.77833340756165,26.5177517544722));
#2118=CARTESIAN_POINT('',(33.3474850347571,5.66180336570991,26.5076777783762));
#2119=CARTESIAN_POINT('',(33.2885125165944,5.60230278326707,26.509662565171));
#2120=CARTESIAN_POINT('',(33.174211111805,5.48333003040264,26.5274992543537));
#2121=CARTESIAN_POINT('',(33.1188461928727,5.42386660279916,26.5431794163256));
#2122=CARTESIAN_POINT('',(33.0123580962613,5.30607693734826,26.5876904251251));
#2123=CARTESIAN_POINT('',(32.961235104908,5.24775074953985,26.6165218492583));
#2124=CARTESIAN_POINT('',(32.8640632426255,5.13380211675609,26.6866821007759));
#2125=CARTESIAN_POINT('',(32.8180444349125,5.0781966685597,26.7280801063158));
#2126=CARTESIAN_POINT('',(32.732253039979,4.97192308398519,26.822144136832));
#2127=CARTESIAN_POINT('',(32.6924806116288,4.92125507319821,26.8748104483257));
#2128=CARTESIAN_POINT('',(32.6192426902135,4.82593095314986,26.9908525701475));
#2129=CARTESIAN_POINT('',(32.5858803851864,4.78137605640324,27.0543767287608));
#2130=CARTESIAN_POINT('',(32.5266511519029,4.70087877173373,27.1898727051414));
#2131=CARTESIAN_POINT('',(32.5007875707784,4.66494023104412,27.2618482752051));
#2132=CARTESIAN_POINT('',(32.4568380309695,4.60309462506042,27.4124139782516));
#2133=CARTESIAN_POINT('',(32.4387712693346,4.57721233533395,27.4910198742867));
#2134=CARTESIAN_POINT('',(32.4107495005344,4.53678217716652,27.6523613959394));
#2135=CARTESIAN_POINT('',(32.4007773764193,4.52221039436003,27.735087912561));
#2136=CARTESIAN_POINT('',(32.3927758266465,4.51049848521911,27.8486928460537));
#2137=CARTESIAN_POINT('',(32.3911874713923,4.50817042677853,27.8788814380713));
#2138=CARTESIAN_POINT('',(32.3890683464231,4.50506227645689,27.9393753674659));
#2139=CARTESIAN_POINT('',(32.388537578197,4.50428218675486,27.9696807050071));
#2140=CARTESIAN_POINT('',(32.388538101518,4.50428369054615,28.));
#2141=B_SPLINE_CURVE_WITH_KNOTS('',3,(#2059,#2060,#2061,#2062,#2063,#2064,#2065,#2066,#2067,
#2068,#2069,#2070,#2071,#2072,#2073,#2074,#2075,#2076,#2077,#2078,#2079,#2080,#2081,#2082,#2083,
#2084,#2085,#2086,#2087,#2088,#2089,#2090,#2091,#2092,#2093,#2094,#2095,#2096,#2097,#2098,#2099,
#2100,#2101,#2102,#2103,#2104,#2105,#2106,#2107,#2108,#2109,#2110,#2111,#2112,#2113,#2114,#2115,
#2116,#2117,#2118,#2119,#2120,#2121,#2122,#2123,#2124,#2125,#2126,#2127,#2128,#2129,#2130,#2131,
#2132,#2133,#2134,#2135,#2136,#2137,#2138,#2139,#2140),.UNSPECIFIED.,.T.,.F.,(4,2,2,2,2,2,2,2,2,
2,2,2,2,2,2,2,2,2,2,2,2,2,2,2,2,2,2,2,2,2,2,2,2,2,2,2,2,2,2,2,4),(0.,0.248365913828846,
0.497230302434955,0.745754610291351,0.994193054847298,1.24539226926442,1.49662104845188,
1.74973208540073,2.00282042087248,2.25300669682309,2.50317233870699,2.75024522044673,
2.99732894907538,3.24579831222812,3.49427399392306,3.74646472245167,3.99876784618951,
4.25168868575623,4.5040732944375,4.59498862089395,4.68590407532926,4.93426998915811,
5.18313437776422,5.43165868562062,5.68009713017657,5.93129634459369,6.18252512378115,
6.43563616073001,6.68872449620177,6.93891077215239,7.1890764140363,7.43614929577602,
7.68323302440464,7.93170238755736,8.18017806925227,8.43236879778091,8.68467192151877,
8.93759276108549,9.18997736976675,9.28089269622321,9.37180815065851),.UNSPECIFIED.);
#2142=CARTESIAN_POINT('',(32.388538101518,4.50428369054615,28.));
#2143=VERTEX_POINT('',#2142);
#2144=EDGE_CURVE('E528',#2143,#2143,#2141,.T.);
#2145=ORIENTED_EDGE('',*,*,#2144,.T.);
#2146=EDGE_LOOP('',(#2145));
#2147=FACE_BOUND('',#2146,.T.);
#2148=ADVANCED_FACE('F440',(#2058,#2147),#2047,.F.);
#2149=CARTESIAN_POINT('',(33.6896280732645,5.31037192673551,28.));
#2150=DIRECTION('',(0.707106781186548,-0.707106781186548,0.));
#2151=DIRECTION('',(-0.707106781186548,-0.707106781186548,0.));
#2152=AXIS2_PLACEMENT_3D('',#2149,#2150,#2151);
#2153=CONICAL_SURFACE('',#2152,1.48999999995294,0.785398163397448);
#2154=ORIENTED_EDGE('',*,*,#2055,.F.);
#2155=EDGE_LOOP('',(#2154));
#2156=FACE_BOUND('',#2155,.T.);
#2157=CARTESIAN_POINT('',(33.9313426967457,6.18940329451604,27.327533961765));
#2158=CARTESIAN_POINT('',(33.9034835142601,6.16658840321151,27.2908212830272));
#2159=CARTESIAN_POINT('',(33.8736646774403,6.14185339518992,27.2567701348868));
#2160=CARTESIAN_POINT('',(33.8109997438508,6.08900315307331,27.1945442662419));
#2161=CARTESIAN_POINT('',(33.7781506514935,6.06088456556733,27.1663754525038));
#2162=CARTESIAN_POINT('',(33.7046871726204,5.99686616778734,27.1122162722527));
#2163=CARTESIAN_POINT('',(33.663686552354,5.96044833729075,27.0873549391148));
#2164=CARTESIAN_POINT('',(33.5800805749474,5.88452757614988,27.0466893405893));
#2165=CARTESIAN_POINT('',(33.5374746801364,5.84502360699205,27.0308881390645));
#2166=CARTESIAN_POINT('',(33.450060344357,5.76211303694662,27.0081618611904));
#2167=CARTESIAN_POINT('',(33.4052353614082,5.71861188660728,27.0016433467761));
#2168=CARTESIAN_POINT('',(33.3164691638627,5.63039913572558,26.9989036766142));
#2169=CARTESIAN_POINT('',(33.2725280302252,5.58568742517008,27.0026834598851));
#2170=CARTESIAN_POINT('',(33.1860376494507,5.49561641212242,27.0206057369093));
#2171=CARTESIAN_POINT('',(33.1435206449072,5.45025784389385,27.0349083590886));
#2172=CARTESIAN_POINT('',(33.061725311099,5.36102223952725,27.0737698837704));
#2173=CARTESIAN_POINT('',(33.022447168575,5.31714528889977,27.0983293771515));
#2174=CARTESIAN_POINT('',(32.9485262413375,5.23285563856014,27.1568844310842));
#2175=CARTESIAN_POINT('',(32.913839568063,5.19241170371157,27.1907793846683));
#2176=CARTESIAN_POINT('',(32.849527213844,5.11607060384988,27.267375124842));
#2177=CARTESIAN_POINT('',(32.8199006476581,5.08017264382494,27.3100743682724));
#2178=CARTESIAN_POINT('',(32.7676849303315,5.01596379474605,27.4012425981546));
#2179=CARTESIAN_POINT('',(32.7448496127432,4.9873947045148,27.4493880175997));
#2180=CARTESIAN_POINT('',(32.7052731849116,4.93735124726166,27.5515212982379));
#2181=CARTESIAN_POINT('',(32.6885287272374,4.91587298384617,27.6055059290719));
#2182=CARTESIAN_POINT('',(32.662676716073,4.88249414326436,27.7135863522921));
#2183=CARTESIAN_POINT('',(32.6531044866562,4.8700133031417,27.767391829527));
#2184=CARTESIAN_POINT('',(32.6400206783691,4.85291485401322,27.8769488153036));
#2185=CARTESIAN_POINT('',(32.6365063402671,4.84829366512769,27.9326994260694));
#2186=CARTESIAN_POINT('',(32.6356848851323,4.84721478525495,28.0408685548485));
#2187=CARTESIAN_POINT('',(32.6380081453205,4.85027097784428,28.0932804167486));
#2188=CARTESIAN_POINT('',(32.6480174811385,4.86337178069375,28.1966927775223));
#2189=CARTESIAN_POINT('',(32.6557032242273,4.87341595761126,28.2476933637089));
#2190=CARTESIAN_POINT('',(32.6761426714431,4.89990853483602,28.3465966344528));
#2191=CARTESIAN_POINT('',(32.6888668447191,4.91631960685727,28.3945155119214));
#2192=CARTESIAN_POINT('',(32.7190368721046,4.95480551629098,28.4864233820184));
#2193=CARTESIAN_POINT('',(32.7364836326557,4.97688144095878,28.5304116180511));
#2194=CARTESIAN_POINT('',(32.7766799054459,5.02706364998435,28.6156381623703));
#2195=CARTESIAN_POINT('',(32.7996535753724,5.05541909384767,28.6566236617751));
#2196=CARTESIAN_POINT('',(32.8498269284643,5.11633926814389,28.7324067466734));
#2197=CARTESIAN_POINT('',(32.8770279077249,5.14890528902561,28.7672024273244));
#2198=CARTESIAN_POINT('',(32.937170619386,5.21961688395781,28.8322266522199));
#2199=CARTESIAN_POINT('',(32.9703834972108,5.25799478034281,28.8619521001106));
#2200=CARTESIAN_POINT('',(33.0402795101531,5.3370889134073,28.9130310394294));
#2201=CARTESIAN_POINT('',(33.0769635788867,5.37780577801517,28.9343822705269));
#2202=CARTESIAN_POINT('',(33.1551010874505,5.46266040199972,28.9692656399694));
#2203=CARTESIAN_POINT('',(33.1967059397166,5.50686304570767,28.9823022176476));
#2204=CARTESIAN_POINT('',(33.2818514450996,5.59522504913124,28.9983720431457));
#2205=CARTESIAN_POINT('',(33.3253924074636,5.63938440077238,29.0014036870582));
#2206=CARTESIAN_POINT('',(33.4143574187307,5.72753111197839,28.9973520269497));
#2207=CARTESIAN_POINT('',(33.4598013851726,5.77148701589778,28.9900158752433));
#2208=CARTESIAN_POINT('',(33.5501706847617,5.85689576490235,28.9649178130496));
#2209=CARTESIAN_POINT('',(33.5950959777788,5.89834841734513,28.9471551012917));
#2210=CARTESIAN_POINT('',(33.6828922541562,5.97761317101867,28.9016046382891));
#2211=CARTESIAN_POINT('',(33.7257665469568,6.01543124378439,28.8738336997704));
#2212=CARTESIAN_POINT('',(33.8079866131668,6.08653872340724,28.8088429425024));
#2213=CARTESIAN_POINT('',(33.8473326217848,6.11982843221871,28.7716237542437));
#2214=CARTESIAN_POINT('',(33.9197170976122,6.18003865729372,28.6898733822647));
#2215=CARTESIAN_POINT('',(33.952912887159,6.20712418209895,28.6456036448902));
#2216=CARTESIAN_POINT('',(34.0129134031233,6.25543406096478,28.5500746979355));
#2217=CARTESIAN_POINT('',(34.0397209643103,6.27666101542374,28.4988186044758));
#2218=CARTESIAN_POINT('',(34.0840091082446,6.31140060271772,28.3943119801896));
#2219=CARTESIAN_POINT('',(34.1019827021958,6.32532499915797,28.3414076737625));
#2220=CARTESIAN_POINT('',(34.1300864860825,6.34698843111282,28.232353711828));
#2221=CARTESIAN_POINT('',(34.1402211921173,6.35473102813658,28.1762059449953));
#2222=CARTESIAN_POINT('',(34.1516222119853,6.36343298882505,28.0665911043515));
#2223=CARTESIAN_POINT('',(34.1534701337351,6.36483725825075,28.0132189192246));
#2224=CARTESIAN_POINT('',(34.14978771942,6.36203163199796,27.9068767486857));
#2225=CARTESIAN_POINT('',(34.144257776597,6.35782203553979,27.8539067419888));
#2226=CARTESIAN_POINT('',(34.1263667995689,6.34411695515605,27.7513467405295));
#2227=CARTESIAN_POINT('',(34.1141929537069,6.33476626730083,27.7017041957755));
#2228=CARTESIAN_POINT('',(34.0837330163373,6.31115579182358,27.6055916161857));
#2229=CARTESIAN_POINT('',(34.0654498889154,6.29689838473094,27.5591200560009));
#2230=CARTESIAN_POINT('',(34.0284963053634,6.26774003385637,27.4808409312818));
#2231=CARTESIAN_POINT('',(34.0109248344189,6.25377627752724,27.4481523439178));
#2232=CARTESIAN_POINT('',(33.9730697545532,6.22338828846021,27.3856286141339));
#2233=CARTESIAN_POINT('',(33.9527867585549,6.20696461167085,27.3557928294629));
#2234=CARTESIAN_POINT('',(33.9313426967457,6.18940329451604,27.327533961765));
#2235=B_SPLINE_CURVE_WITH_KNOTS('',3,(#2157,#2158,#2159,#2160,#2161,#2162,#2163,#2164,#2165,
#2166,#2167,#2168,#2169,#2170,#2171,#2172,#2173,#2174,#2175,#2176,#2177,#2178,#2179,#2180,#2181,
#2182,#2183,#2184,#2185,#2186,#2187,#2188,#2189,#2190,#2191,#2192,#2193,#2194,#2195,#2196,#2197,
#2198,#2199,#2200,#2201,#2202,#2203,#2204,#2205,#2206,#2207,#2208,#2209,#2210,#2211,#2212,#2213,
#2214,#2215,#2216,#2217,#2218,#2219,#2220,#2221,#2222,#2223,#2224,#2225,#2226,#2227,#2228,#2229,
#2230,#2231,#2232,#2233,#2234),.UNSPECIFIED.,.T.,.F.,(4,2,2,2,2,2,2,2,2,2,2,2,2,2,2,2,2,2,2,2,2,
2,2,2,2,2,2,2,2,2,2,2,2,2,2,2,2,2,4),(0.,0.154162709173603,0.308479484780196,0.488294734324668,
0.668170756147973,0.855705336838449,1.04325701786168,1.23372333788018,1.42420063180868,
1.61270049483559,1.80116734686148,1.98159976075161,2.16193286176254,2.32922594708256,
2.49644281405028,2.65334193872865,2.81023133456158,2.96621447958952,3.12222758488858,
3.28615739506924,3.45013756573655,3.62581931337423,3.80154844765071,3.9869586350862,
4.17239854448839,4.36243975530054,4.55249557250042,4.74223359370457,4.93195895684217,
5.1158224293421,5.29960416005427,5.47143946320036,5.64317569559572,5.80264831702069,
5.96211243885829,6.11729971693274,6.27241181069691,6.39110233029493,6.50976606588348),.UNSPECIFIED.);
#2236=CARTESIAN_POINT('',(33.9313426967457,6.18940329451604,27.327533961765));
#2237=VERTEX_POINT('',#2236);
#2238=EDGE_CURVE('E9',#2237,#2237,#2235,.T.);
#2239=ORIENTED_EDGE('',*,*,#2238,.F.);
#2240=EDGE_LOOP('',(#2239));
#2241=FACE_BOUND('',#2240,.T.);
#2242=ADVANCED_FACE('F437',(#2156,#2241),#2153,.T.);
#2243=ORIENTED_EDGE('',*,*,#2238,.T.);
#2244=EDGE_LOOP('',(#2243));
#2245=FACE_BOUND('',#2244,.T.);
#2246=ORIENTED_EDGE('',*,*,#2144,.F.);
#2247=EDGE_LOOP('',(#2246));
#2248=FACE_BOUND('',#2247,.T.);
#2249=ADVANCED_FACE('F304',(#2245,#2248),#1712,.F.);
#2250=CLOSED_SHELL('',(#2148,#2242,#2249));
#2251=CARTESIAN_POINT('',(50.3137084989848,-11.3137084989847,28.));
#2252=DIRECTION('',(0.707106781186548,-0.707106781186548,0.));
#2253=DIRECTION('',(-0.707106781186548,-0.707106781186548,0.));
#2254=AXIS2_PLACEMENT_3D('',#2251,#2252,#2253);
#2255=CYLINDRICAL_SURFACE('',#2254,1.49);
#2256=CARTESIAN_POINT('',(44.310371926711,-5.31037192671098,28.));
#2257=DIRECTION('',(-0.707106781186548,0.707106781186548,0.));
#2258=DIRECTION('',(-0.707106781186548,-0.707106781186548,0.));
#2259=AXIS2_PLACEMENT_3D('',#2256,#2257,#2258);
#2260=CIRCLE('',#2259,1.49);
#2261=CARTESIAN_POINT('',(43.2567828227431,-6.36396103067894,28.));
#2262=VERTEX_POINT('',#2261);
#2263=EDGE_CURVE('E784',#2262,#2262,#2260,.T.);
#2264=ORIENTED_EDGE('',*,*,#2263,.T.);
#2265=EDGE_LOOP('',(#2264));
#2266=FACE_BOUND('',#2265,.T.);
#2267=CARTESIAN_POINT('',(45.6114618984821,-4.50428369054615,28.));
#2268=CARTESIAN_POINT('',(45.6114604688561,-4.50428779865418,28.0828272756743));
#2269=CARTESIAN_POINT('',(45.6074940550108,-4.51012487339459,28.1657587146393));
#2270=CARTESIAN_POINT('',(45.5916551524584,-4.53324065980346,28.3293484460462));
#2271=CARTESIAN_POINT('',(45.5797668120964,-4.55054231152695,28.4100018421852));
#2272=CARTESIAN_POINT('',(45.5482289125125,-4.59580823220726,28.5665486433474));
#2273=CARTESIAN_POINT('',(45.5285899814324,-4.6237578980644,28.6424484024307));
#2274=CARTESIAN_POINT('',(45.4817851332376,-4.68914387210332,28.7874975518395));
#2275=CARTESIAN_POINT('',(45.4546218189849,-4.72657689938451,28.8566492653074));
#2276=CARTESIAN_POINT('',(45.392748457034,-4.80993594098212,28.9871273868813));
#2277=CARTESIAN_POINT('',(45.3579579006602,-4.85595171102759,29.048358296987));
#2278=CARTESIAN_POINT('',(45.2814860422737,-4.95447421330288,29.160426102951));
#2279=CARTESIAN_POINT('',(45.23980392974,-5.00698170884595,29.2112617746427));
#2280=CARTESIAN_POINT('',(45.1498882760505,-5.11702575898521,29.3014532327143));
#2281=CARTESIAN_POINT('',(45.1016079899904,-5.17459704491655,29.3407201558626));
#2282=CARTESIAN_POINT('',(44.9996976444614,-5.29241790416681,29.4060865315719));
#2283=CARTESIAN_POINT('',(44.9460680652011,-5.35266723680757,29.4321871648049));
#2284=CARTESIAN_POINT('',(44.8353626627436,-5.47313023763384,29.4701883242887));
#2285=CARTESIAN_POINT('',(44.7783334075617,-5.53333639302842,29.4822482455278));
#2286=CARTESIAN_POINT('',(44.6618033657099,-5.65251496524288,29.4923222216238));
#2287=CARTESIAN_POINT('',(44.6023027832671,-5.71148748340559,29.490337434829));
#2288=CARTESIAN_POINT('',(44.4833300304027,-5.82578888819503,29.4725007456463));
#2289=CARTESIAN_POINT('',(44.4238666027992,-5.88115380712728,29.4568205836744));
#2290=CARTESIAN_POINT('',(44.3060769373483,-5.98764190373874,29.4123095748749));
#2291=CARTESIAN_POINT('',(44.2477507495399,-6.03876489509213,29.3834781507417));
#2292=CARTESIAN_POINT('',(44.1338021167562,-6.13593675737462,29.3133178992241));
#2293=CARTESIAN_POINT('',(44.0781966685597,-6.18195556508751,29.2719198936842));
#2294=CARTESIAN_POINT('',(43.9719230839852,-6.26774696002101,29.177855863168));
#2295=CARTESIAN_POINT('',(43.9212550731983,-6.30751938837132,29.1251895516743));
#2296=CARTESIAN_POINT('',(43.8259309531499,-6.38075730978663,29.0091474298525));
#2297=CARTESIAN_POINT('',(43.7813760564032,-6.41411961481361,28.9456232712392));
#2298=CARTESIAN_POINT('',(43.7008787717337,-6.47334884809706,28.8101272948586));
#2299=CARTESIAN_POINT('',(43.6649402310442,-6.49921242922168,28.7381517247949));
#2300=CARTESIAN_POINT('',(43.6030946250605,-6.54316196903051,28.5875860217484));
#2301=CARTESIAN_POINT('',(43.5772123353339,-6.56122873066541,28.5089801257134));
#2302=CARTESIAN_POINT('',(43.5367821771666,-6.58925049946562,28.3476386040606));
#2303=CARTESIAN_POINT('',(43.5222103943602,-6.59922262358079,28.2649120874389));
#2304=CARTESIAN_POINT('',(43.5104984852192,-6.60722417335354,28.1513071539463));
#2305=CARTESIAN_POINT('',(43.5081704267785,-6.60881252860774,28.1211185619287));
#2306=CARTESIAN_POINT('',(43.5050622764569,-6.61093165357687,28.0606246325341));
#2307=CARTESIAN_POINT('',(43.5042821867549,-6.61146242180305,28.0303192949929));
#2308=CARTESIAN_POINT('',(43.5042877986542,-6.61146046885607,27.9171727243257));
#2309=CARTESIAN_POINT('',(43.5101248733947,-6.60749405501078,27.8342412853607));
#2310=CARTESIAN_POINT('',(43.5332406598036,-6.59165515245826,27.6706515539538));
#2311=CARTESIAN_POINT('',(43.550542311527,-6.57976681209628,27.5899981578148));
#2312=CARTESIAN_POINT('',(43.5958082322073,-6.54822891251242,27.4334513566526));
#2313=CARTESIAN_POINT('',(43.6237578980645,-6.52858998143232,27.3575515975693));
#2314=CARTESIAN_POINT('',(43.6891438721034,-6.48178513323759,27.2125024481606));
#2315=CARTESIAN_POINT('',(43.7265768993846,-6.45462181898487,27.1433507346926));
#2316=CARTESIAN_POINT('',(43.8099359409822,-6.39274845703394,27.0128726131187));
#2317=CARTESIAN_POINT('',(43.8559517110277,-6.35795790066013,26.951641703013));
#2318=CARTESIAN_POINT('',(43.954474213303,-6.28148604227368,26.839573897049));
#2319=CARTESIAN_POINT('',(44.006981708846,-6.23980392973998,26.7887382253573));
#2320=CARTESIAN_POINT('',(44.1170257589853,-6.14988827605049,26.6985467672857));
#2321=CARTESIAN_POINT('',(44.1745970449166,-6.10160798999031,26.6592798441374));
#2322=CARTESIAN_POINT('',(44.2924179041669,-5.99969764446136,26.5939134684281));
#2323=CARTESIAN_POINT('',(44.3526672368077,-5.94606806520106,26.5678128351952));
#2324=CARTESIAN_POINT('',(44.4731302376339,-5.83536266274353,26.5298116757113));
#2325=CARTESIAN_POINT('',(44.5333363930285,-5.77833340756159,26.5177517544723));
#2326=CARTESIAN_POINT('',(44.6525149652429,-5.66180336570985,26.5076777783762));
#2327=CARTESIAN_POINT('',(44.7114874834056,-5.60230278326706,26.5096625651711));
#2328=CARTESIAN_POINT('',(44.8257888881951,-5.48333003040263,26.5274992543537));
#2329=CARTESIAN_POINT('',(44.8811538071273,-5.4238666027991,26.5431794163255));
#2330=CARTESIAN_POINT('',(44.9876419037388,-5.3060769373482,26.5876904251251));
#2331=CARTESIAN_POINT('',(45.0387648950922,-5.24775074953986,26.6165218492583));
#2332=CARTESIAN_POINT('',(45.1359367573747,-5.13380211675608,26.6866821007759));
#2333=CARTESIAN_POINT('',(45.1819555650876,-5.0781966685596,26.7280801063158));
#2334=CARTESIAN_POINT('',(45.2677469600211,-4.9719230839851,26.822144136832));
#2335=CARTESIAN_POINT('',(45.3075193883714,-4.92125507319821,26.8748104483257));
#2336=CARTESIAN_POINT('',(45.3807573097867,-4.82593095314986,26.9908525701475));
#2337=CARTESIAN_POINT('',(45.4141196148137,-4.78137605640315,27.0543767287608));
#2338=CARTESIAN_POINT('',(45.4733488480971,-4.70087877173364,27.1898727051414));
#2339=CARTESIAN_POINT('',(45.4992124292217,-4.66494023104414,27.2618482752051));
#2340=CARTESIAN_POINT('',(45.5431619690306,-4.6030946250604,27.4124139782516));
#2341=CARTESIAN_POINT('',(45.5612287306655,-4.57721233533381,27.4910198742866));
#2342=CARTESIAN_POINT('',(45.5892504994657,-4.53678217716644,27.6523613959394));
#2343=CARTESIAN_POINT('',(45.5992226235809,-4.52221039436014,27.735087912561));
#2344=CARTESIAN_POINT('',(45.6072241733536,-4.51049848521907,27.8486928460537));
#2345=CARTESIAN_POINT('',(45.6088125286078,-4.50817042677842,27.8788814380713));
#2346=CARTESIAN_POINT('',(45.6109316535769,-4.50506227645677,27.9393753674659));
#2347=CARTESIAN_POINT('',(45.6114624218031,-4.50428218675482,27.9696807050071));
#2348=CARTESIAN_POINT('',(45.6114618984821,-4.50428369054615,28.));
#2349=B_SPLINE_CURVE_WITH_KNOTS('',3,(#2267,#2268,#2269,#2270,#2271,#2272,#2273,#2274,#2275,
#2276,#2277,#2278,#2279,#2280,#2281,#2282,#2283,#2284,#2285,#2286,#2287,#2288,#2289,#2290,#2291,
#2292,#2293,#2294,#2295,#2296,#2297,#2298,#2299,#2300,#2301,#2302,#2303,#2304,#2305,#2306,#2307,
#2308,#2309,#2310,#2311,#2312,#2313,#2314,#2315,#2316,#2317,#2318,#2319,#2320,#2321,#2322,#2323,
#2324,#2325,#2326,#2327,#2328,#2329,#2330,#2331,#2332,#2333,#2334,#2335,#2336,#2337,#2338,#2339,
#2340,#2341,#2342,#2343,#2344,#2345,#2346,#2347,#2348),.UNSPECIFIED.,.T.,.F.,(4,2,2,2,2,2,2,2,2,
2,2,2,2,2,2,2,2,2,2,2,2,2,2,2,2,2,2,2,2,2,2,2,2,2,2,2,2,2,2,2,4),(0.,0.24836591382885,
0.49723030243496,0.745754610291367,0.99419305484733,1.24539226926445,1.49662104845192,
1.74973208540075,2.00282042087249,2.25300669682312,2.50317233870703,2.75024522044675,
2.99732894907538,3.2457983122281,3.49427399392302,3.74646472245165,3.9987678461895,
4.25168868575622,4.50407329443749,4.59498862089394,4.68590407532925,4.93426998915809,
5.1831343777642,5.4316586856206,5.68009713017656,5.93129634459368,6.18252512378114,
6.43563616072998,6.68872449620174,6.93891077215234,7.18907641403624,7.43614929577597,
7.68323302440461,7.93170238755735,8.18017806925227,8.43236879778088,8.68467192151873,
8.93759276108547,9.18997736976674,9.28089269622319,9.3718081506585),.UNSPECIFIED.);
#2350=CARTESIAN_POINT('',(45.6114618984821,-4.50428369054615,28.));
#2351=VERTEX_POINT('',#2350);
#2352=EDGE_CURVE('E496',#2351,#2351,#2349,.T.);
#2353=ORIENTED_EDGE('',*,*,#2352,.T.);
#2354=EDGE_LOOP('',(#2353));
#2355=FACE_BOUND('',#2354,.T.);
#2356=ADVANCED_FACE('F505',(#2266,#2355),#2255,.F.);
#2357=CARTESIAN_POINT('',(44.3103719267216,-5.31037192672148,28.));
#2358=DIRECTION('',(-0.707106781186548,0.707106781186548,0.));
#2359=DIRECTION('',(0.707106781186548,0.707106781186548,0.));
#2360=AXIS2_PLACEMENT_3D('',#2357,#2358,#2359);
#2361=CONICAL_SURFACE('',#2360,1.48999999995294,0.785398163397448);
#2362=ORIENTED_EDGE('',*,*,#2263,.F.);
#2363=EDGE_LOOP('',(#2362));
#2364=FACE_BOUND('',#2363,.T.);
#2365=CARTESIAN_POINT('',(45.1894032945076,-5.06865730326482,27.327533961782));
#2366=CARTESIAN_POINT('',(45.2122610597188,-5.04074567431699,27.3643172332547));
#2367=CARTESIAN_POINT('',(45.2331992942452,-5.01479140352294,27.4037857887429));
#2368=CARTESIAN_POINT('',(45.2708052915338,-4.96768671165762,27.4873834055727));
#2369=CARTESIAN_POINT('',(45.2874717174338,-4.94653779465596,27.5315139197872));
#2370=CARTESIAN_POINT('',(45.3175426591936,-4.90808643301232,27.6280540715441));
#2371=CARTESIAN_POINT('',(45.3304638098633,-4.89136850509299,27.6808510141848));
#2372=CARTESIAN_POINT('',(45.3502261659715,-4.8656854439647,27.7893937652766));
#2373=CARTESIAN_POINT('',(45.3570683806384,-4.85671902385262,27.8451390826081));
#2374=CARTESIAN_POINT('',(45.3641953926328,-4.84737538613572,27.9541625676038));
#2375=CARTESIAN_POINT('',(45.364869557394,-4.84648817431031,28.0073721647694));
#2376=CARTESIAN_POINT('',(45.3606539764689,-4.8520194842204,28.1131776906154));
#2377=CARTESIAN_POINT('',(45.3557653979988,-4.85843647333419,28.1657737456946));
#2378=CARTESIAN_POINT('',(45.3407596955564,-4.87800285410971,28.2676410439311));
#2379=CARTESIAN_POINT('',(45.3307644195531,-4.89099528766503,28.3169607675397));
#2380=CARTESIAN_POINT('',(45.3059027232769,-4.92300713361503,28.4122984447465));
#2381=CARTESIAN_POINT('',(45.2910355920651,-4.94202742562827,28.4583159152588));
#2382=CARTESIAN_POINT('',(45.2561518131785,-4.98611888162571,28.5476845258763));
#2383=CARTESIAN_POINT('',(45.2359600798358,-5.01139351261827,28.5908665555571));
#2384=CARTESIAN_POINT('',(45.1912140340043,-5.06656975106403,28.6716465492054));
#2385=CARTESIAN_POINT('',(45.1666584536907,-5.09647270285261,28.709242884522));
#2386=CARTESIAN_POINT('',(45.1118449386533,-5.16210235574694,28.7805742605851));
#2387=CARTESIAN_POINT('',(45.0813081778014,-5.1980901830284,28.8138548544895));
#2388=CARTESIAN_POINT('',(45.016504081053,-5.27296222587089,28.8726063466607));
#2389=CARTESIAN_POINT('',(44.9822356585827,-5.31184728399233,28.898074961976));
#2390=CARTESIAN_POINT('',(44.9084686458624,-5.39381297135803,28.9420770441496));
#2391=CARTESIAN_POINT('',(44.8687775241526,-5.43700425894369,28.9600827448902));
#2392=CARTESIAN_POINT('',(44.7869517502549,-5.52401645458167,28.9864315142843));
#2393=CARTESIAN_POINT('',(44.7448166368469,-5.5678374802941,28.9947727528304));
#2394=CARTESIAN_POINT('',(44.6577401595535,-5.65631960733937,29.0017441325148));
#2395=CARTESIAN_POINT('',(44.6127520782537,-5.70096095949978,29.0000459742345));
#2396=CARTESIAN_POINT('',(44.5225600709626,-5.78837424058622,28.9861995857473));
#2397=CARTESIAN_POINT('',(44.4773561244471,-5.83114598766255,28.9740503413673));
#2398=CARTESIAN_POINT('',(44.3878913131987,-5.91391247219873,28.9394569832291));
#2399=CARTESIAN_POINT('',(44.3436364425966,-5.95389191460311,28.9169606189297));
#2400=CARTESIAN_POINT('',(44.2578233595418,-6.02980743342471,28.8621186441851));
#2401=CARTESIAN_POINT('',(44.2162651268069,-6.06574354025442,28.8297731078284));
#2402=CARTESIAN_POINT('',(44.1383302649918,-6.13189374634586,28.7567576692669));
#2403=CARTESIAN_POINT('',(44.1018595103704,-6.16221663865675,28.716287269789));
#2404=CARTESIAN_POINT('',(44.034619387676,-6.21727428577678,28.627542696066));
#2405=CARTESIAN_POINT('',(44.0038481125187,-6.24201091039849,28.5792711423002));
#2406=CARTESIAN_POINT('',(43.9511097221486,-6.28391491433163,28.479156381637));
#2407=CARTESIAN_POINT('',(43.9287421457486,-6.30143211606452,28.4276712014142));
#2408=CARTESIAN_POINT('',(43.8916653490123,-6.33025805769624,28.3203871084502));
#2409=CARTESIAN_POINT('',(43.8769516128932,-6.3415704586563,28.2645907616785));
#2410=CARTESIAN_POINT('',(43.8568378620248,-6.35698628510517,28.1547730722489));
#2411=CARTESIAN_POINT('',(43.8508246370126,-6.36156477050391,28.1009300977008));
#2412=CARTESIAN_POINT('',(43.846435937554,-6.36490910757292,27.9927603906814));
#2413=CARTESIAN_POINT('',(43.8480582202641,-6.36367666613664,27.9384338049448));
#2414=CARTESIAN_POINT('',(43.8586102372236,-6.3556231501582,27.8333005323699));
#2415=CARTESIAN_POINT('',(43.8672236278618,-6.34904399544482,27.7824428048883));
#2416=CARTESIAN_POINT('',(43.8909210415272,-6.33080665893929,27.6832139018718));
#2417=CARTESIAN_POINT('',(43.9060054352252,-6.31914818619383,27.634842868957));
#2418=CARTESIAN_POINT('',(43.9423059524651,-6.29079879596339,27.5408722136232));
#2419=CARTESIAN_POINT('',(43.9636361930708,-6.27401394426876,27.4953452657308));
#2420=CARTESIAN_POINT('',(44.0114074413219,-6.23592228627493,27.409128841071));
#2421=CARTESIAN_POINT('',(44.0378497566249,-6.21461432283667,27.3684406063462));
#2422=CARTESIAN_POINT('',(44.0967106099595,-6.16644747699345,27.2902617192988));
#2423=CARTESIAN_POINT('',(44.129403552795,-6.13932035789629,27.2531431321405));
#2424=CARTESIAN_POINT('',(44.198317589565,-6.08107963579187,27.1859885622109));
#2425=CARTESIAN_POINT('',(44.2345397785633,-6.04996479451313,27.1559547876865));
#2426=CARTESIAN_POINT('',(44.3119453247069,-5.98214486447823,27.1017030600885));
#2427=CARTESIAN_POINT('',(44.3532985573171,-5.94520308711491,27.0780225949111));
#2428=CARTESIAN_POINT('',(44.4374386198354,-5.86834807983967,27.0397949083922));
#2429=CARTESIAN_POINT('',(44.4802257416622,-5.82843424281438,27.0252495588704));
#2430=CARTESIAN_POINT('',(44.5678667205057,-5.74479603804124,27.005136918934));
#2431=CARTESIAN_POINT('',(44.6127301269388,-5.70098157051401,26.9999838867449));
#2432=CARTESIAN_POINT('',(44.7014117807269,-5.61229350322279,27.0000161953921));
#2433=CARTESIAN_POINT('',(44.7452297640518,-5.56741964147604,27.0052041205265));
#2434=CARTESIAN_POINT('',(44.8312376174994,-5.47728061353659,27.0259617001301));
#2435=CARTESIAN_POINT('',(44.8733963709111,-5.43201868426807,27.041674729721));
#2436=CARTESIAN_POINT('',(44.9543126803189,-5.34319818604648,27.0833049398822));
#2437=CARTESIAN_POINT('',(44.9930720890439,-5.29963869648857,27.1092165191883));
#2438=CARTESIAN_POINT('',(45.0595275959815,-5.22342832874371,27.1650641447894));
#2439=CARTESIAN_POINT('',(45.0879527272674,-5.19023595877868,27.1934066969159));
#2440=CARTESIAN_POINT('',(45.1413687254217,-5.12691950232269,27.25610325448));
#2441=CARTESIAN_POINT('',(45.166361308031,-5.09679388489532,27.2904542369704));
#2442=CARTESIAN_POINT('',(45.1894032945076,-5.06865730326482,27.327533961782));
#2443=B_SPLINE_CURVE_WITH_KNOTS('',3,(#2365,#2366,#2367,#2368,#2369,#2370,#2371,#2372,#2373,
#2374,#2375,#2376,#2377,#2378,#2379,#2380,#2381,#2382,#2383,#2384,#2385,#2386,#2387,#2388,#2389,
#2390,#2391,#2392,#2393,#2394,#2395,#2396,#2397,#2398,#2399,#2400,#2401,#2402,#2403,#2404,#2405,
#2406,#2407,#2408,#2409,#2410,#2411,#2412,#2413,#2414,#2415,#2416,#2417,#2418,#2419,#2420,#2421,
#2422,#2423,#2424,#2425,#2426,#2427,#2428,#2429,#2430,#2431,#2432,#2433,#2434,#2435,#2436,#2437,
#2438,#2439,#2440,#2441,#2442),.UNSPECIFIED.,.T.,.F.,(4,2,2,2,2,2,2,2,2,2,2,2,2,2,2,2,2,2,2,2,2,
2,2,2,2,2,2,2,2,2,2,2,2,2,2,2,2,2,4),(0.,0.154420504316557,0.308889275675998,0.478581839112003,
0.648246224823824,0.80712018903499,0.965960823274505,1.12117709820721,1.27641603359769,
1.43758775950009,1.59880638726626,1.77130915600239,1.94386228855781,2.12711175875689,
2.31039592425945,2.49970613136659,2.68903471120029,2.87933003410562,3.06962392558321,
3.25571746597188,3.44174862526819,3.61722511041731,3.79259794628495,3.95488080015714,
4.11711598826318,4.27239415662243,4.42768122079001,4.58600434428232,4.7443680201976,
4.91288130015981,5.08144703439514,5.26152857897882,5.44164701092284,5.62953355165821,
5.81746705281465,6.00801414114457,6.19845672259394,6.35419990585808,6.50986495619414),.UNSPECIFIED.);
#2444=CARTESIAN_POINT('',(45.1894032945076,-5.06865730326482,27.327533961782));
#2445=VERTEX_POINT('',#2444);
#2446=EDGE_CURVE('E31',#2445,#2445,#2443,.T.);
#2447=ORIENTED_EDGE('',*,*,#2446,.F.);
#2448=EDGE_LOOP('',(#2447));
#2449=FACE_BOUND('',#2448,.T.);
#2450=ADVANCED_FACE('F825',(#2364,#2449),#2361,.T.);
#2451=ORIENTED_EDGE('',*,*,#2446,.T.);
#2452=EDGE_LOOP('',(#2451));
#2453=FACE_BOUND('',#2452,.T.);
#2454=ORIENTED_EDGE('',*,*,#2352,.F.);
#2455=EDGE_LOOP('',(#2454));
#2456=FACE_BOUND('',#2455,.T.);
#2457=ADVANCED_FACE('F823',(#2453,#2456),#1712,.F.);
#2458=CLOSED_SHELL('',(#2356,#2450,#2457));
#2459=CARTESIAN_POINT('',(42.8890872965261,3.88908729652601,20.));
#2460=DIRECTION('',(0.,0.,-1.));
#2461=DIRECTION('',(0.707106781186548,-0.707106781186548,0.));
#2462=AXIS2_PLACEMENT_3D('',#2459,#2460,#2461);
#2463=CIRCLE('',#2462,1.5);
#2464=CARTESIAN_POINT('',(43.9497474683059,2.82842712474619,20.));
#2465=VERTEX_POINT('',#2464);
#2466=EDGE_CURVE('E1036',#2465,#2465,#2463,.T.);
#2467=ORIENTED_EDGE('',*,*,#2466,.F.);
#2468=EDGE_LOOP('',(#2467));
#2469=FACE_BOUND('',#2468,.T.);
#2470=ADVANCED_FACE('F446',(#2469),#1092,.T.);
#2471=CARTESIAN_POINT('',(42.8890872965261,3.88908729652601,20.7000000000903));
#2472=DIRECTION('',(0.,0.,-1.));
#2473=DIRECTION('',(-0.707106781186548,0.707106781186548,0.));
#2474=AXIS2_PLACEMENT_3D('',#2471,#2472,#2473);
#2475=CONICAL_SURFACE('',#2474,1.49999999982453,1.04719755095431);
#2476=CARTESIAN_POINT('',(42.8890872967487,3.88908729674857,21.5660254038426));
#2477=VERTEX_POINT('',#2476);
#2478=VERTEX_LOOP('',#2477);
#2479=FACE_BOUND('',#2478,.T.);
#2480=CARTESIAN_POINT('',(42.8890872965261,3.88908729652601,20.7));
#2481=DIRECTION('',(0.,0.,-1.));
#2482=DIRECTION('',(0.707106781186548,-0.707106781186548,0.));
#2483=AXIS2_PLACEMENT_3D('',#2480,#2481,#2482);
#2484=CIRCLE('',#2483,1.5);
#2485=CARTESIAN_POINT('',(43.9497474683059,2.82842712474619,20.7));
#2486=VERTEX_POINT('',#2485);
#2487=EDGE_CURVE('E157',#2486,#2486,#2484,.F.);
#2488=ORIENTED_EDGE('',*,*,#2487,.F.);
#2489=EDGE_LOOP('',(#2488));
#2490=FACE_BOUND('',#2489,.T.);
#2491=ADVANCED_FACE('F433',(#2479,#2490),#2475,.F.);
#2492=CARTESIAN_POINT('',(42.8890872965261,3.88908729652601,20.35));
#2493=DIRECTION('',(0.,0.,1.));
#2494=DIRECTION('',(0.707106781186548,-0.707106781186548,0.));
#2495=AXIS2_PLACEMENT_3D('',#2492,#2493,#2494);
#2496=CYLINDRICAL_SURFACE('',#2495,1.5);
#2497=ORIENTED_EDGE('',*,*,#2466,.T.);
#2498=EDGE_LOOP('',(#2497));
#2499=FACE_BOUND('',#2498,.T.);
#2500=ORIENTED_EDGE('',*,*,#2487,.T.);
#2501=EDGE_LOOP('',(#2500));
#2502=FACE_BOUND('',#2501,.T.);
#2503=ADVANCED_FACE('F431',(#2499,#2502),#2496,.F.);
#2504=CLOSED_SHELL('',(#2470,#2491,#2503));
#2505=ORIENTED_CLOSED_SHELL('',*,#2250,.T.);
#2506=ORIENTED_CLOSED_SHELL('',*,#2458,.T.);
#2507=ORIENTED_CLOSED_SHELL('',*,#2504,.T.);
#2508=BREP_WITH_VOIDS('B1',#2042,(#2505,#2506,#2507));
#2509=ADVANCED_BREP_SHAPE_REPRESENTATION('',(#18,#2508),#14);
#2510=SHAPE_DEFINITION_REPRESENTATION(#9,#2509);
ENDSEC;
END-ISO-10303-21;
